VERSION 5.8 ;
BUSBITCHARS "[]" ;
DIVIDERCHAR "/" ;
UNITS
    DATABASE MICRONS 1000 ;
END UNITS

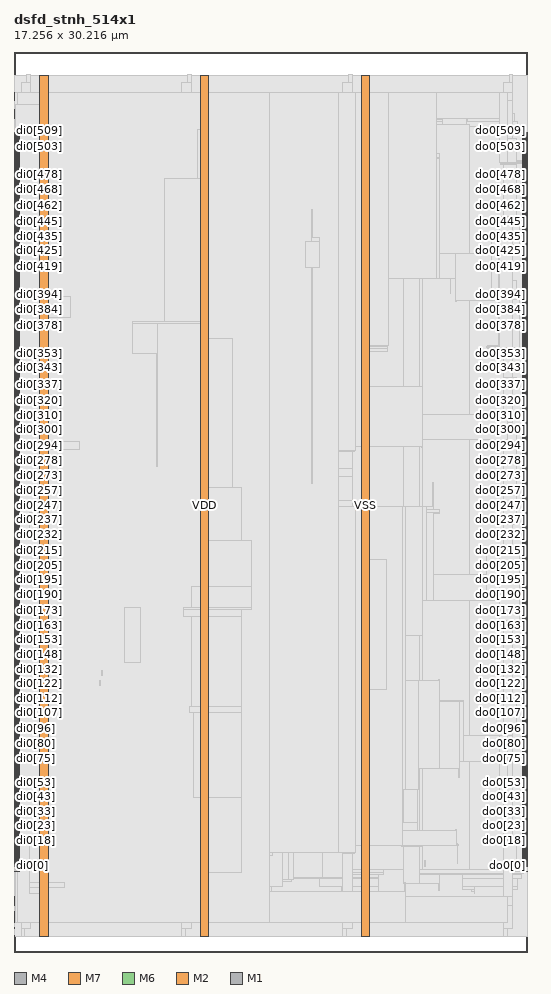
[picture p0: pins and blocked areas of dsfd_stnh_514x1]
MACRO dsfd_stnh_514x1
  FOREIGN dsfd_stnh_514x1 0 0 ;
  CLASS BLOCK ;
  SIZE 17.256 BY 30.216 ;
  PIN di0[0]
    DIRECTION INPUT ;
    USE SIGNAL ;
    PORT
      LAYER M4 ;
        RECT  0 2.88 0.192 2.904 ;
    END
  END di0[0]
  PIN di0[100]
    DIRECTION INPUT ;
    USE SIGNAL ;
    PORT
      LAYER M4 ;
        RECT  0 7.68 0.192 7.704 ;
    END
  END di0[100]
  PIN di0[101]
    DIRECTION INPUT ;
    USE SIGNAL ;
    PORT
      LAYER M4 ;
        RECT  0 7.728 0.192 7.752 ;
    END
  END di0[101]
  PIN di0[102]
    DIRECTION INPUT ;
    USE SIGNAL ;
    PORT
      LAYER M4 ;
        RECT  0 7.776 0.192 7.8 ;
    END
  END di0[102]
  PIN di0[103]
    DIRECTION INPUT ;
    USE SIGNAL ;
    PORT
      LAYER M4 ;
        RECT  0 7.824 0.192 7.848 ;
    END
  END di0[103]
  PIN di0[104]
    DIRECTION INPUT ;
    USE SIGNAL ;
    PORT
      LAYER M4 ;
        RECT  0 7.872 0.192 7.896 ;
    END
  END di0[104]
  PIN di0[105]
    DIRECTION INPUT ;
    USE SIGNAL ;
    PORT
      LAYER M4 ;
        RECT  0 7.92 0.192 7.944 ;
    END
  END di0[105]
  PIN di0[106]
    DIRECTION INPUT ;
    USE SIGNAL ;
    PORT
      LAYER M4 ;
        RECT  0 7.968 0.192 7.992 ;
    END
  END di0[106]
  PIN di0[107]
    DIRECTION INPUT ;
    USE SIGNAL ;
    PORT
      LAYER M4 ;
        RECT  0 8.016 0.192 8.04 ;
    END
  END di0[107]
  PIN di0[108]
    DIRECTION INPUT ;
    USE SIGNAL ;
    PORT
      LAYER M4 ;
        RECT  0 8.064 0.192 8.088 ;
    END
  END di0[108]
  PIN di0[109]
    DIRECTION INPUT ;
    USE SIGNAL ;
    PORT
      LAYER M4 ;
        RECT  0 8.112 0.192 8.136 ;
    END
  END di0[109]
  PIN di0[10]
    DIRECTION INPUT ;
    USE SIGNAL ;
    PORT
      LAYER M4 ;
        RECT  0 3.36 0.192 3.384 ;
    END
  END di0[10]
  PIN di0[110]
    DIRECTION INPUT ;
    USE SIGNAL ;
    PORT
      LAYER M4 ;
        RECT  0 8.16 0.192 8.184 ;
    END
  END di0[110]
  PIN di0[111]
    DIRECTION INPUT ;
    USE SIGNAL ;
    PORT
      LAYER M4 ;
        RECT  0 8.208 0.192 8.232 ;
    END
  END di0[111]
  PIN di0[112]
    DIRECTION INPUT ;
    USE SIGNAL ;
    PORT
      LAYER M4 ;
        RECT  0 8.256 0.192 8.28 ;
    END
  END di0[112]
  PIN di0[113]
    DIRECTION INPUT ;
    USE SIGNAL ;
    PORT
      LAYER M4 ;
        RECT  0 8.304 0.192 8.328 ;
    END
  END di0[113]
  PIN di0[114]
    DIRECTION INPUT ;
    USE SIGNAL ;
    PORT
      LAYER M4 ;
        RECT  0 8.352 0.192 8.376 ;
    END
  END di0[114]
  PIN di0[115]
    DIRECTION INPUT ;
    USE SIGNAL ;
    PORT
      LAYER M4 ;
        RECT  0 8.4 0.192 8.424 ;
    END
  END di0[115]
  PIN di0[116]
    DIRECTION INPUT ;
    USE SIGNAL ;
    PORT
      LAYER M4 ;
        RECT  0 8.448 0.192 8.472 ;
    END
  END di0[116]
  PIN di0[117]
    DIRECTION INPUT ;
    USE SIGNAL ;
    PORT
      LAYER M4 ;
        RECT  0 8.496 0.192 8.52 ;
    END
  END di0[117]
  PIN di0[118]
    DIRECTION INPUT ;
    USE SIGNAL ;
    PORT
      LAYER M4 ;
        RECT  0 8.544 0.192 8.568 ;
    END
  END di0[118]
  PIN di0[119]
    DIRECTION INPUT ;
    USE SIGNAL ;
    PORT
      LAYER M4 ;
        RECT  0 8.592 0.192 8.616 ;
    END
  END di0[119]
  PIN di0[11]
    DIRECTION INPUT ;
    USE SIGNAL ;
    PORT
      LAYER M4 ;
        RECT  0 3.408 0.192 3.432 ;
    END
  END di0[11]
  PIN di0[120]
    DIRECTION INPUT ;
    USE SIGNAL ;
    PORT
      LAYER M4 ;
        RECT  0 8.64 0.192 8.664 ;
    END
  END di0[120]
  PIN di0[121]
    DIRECTION INPUT ;
    USE SIGNAL ;
    PORT
      LAYER M4 ;
        RECT  0 8.688 0.192 8.712 ;
    END
  END di0[121]
  PIN di0[122]
    DIRECTION INPUT ;
    USE SIGNAL ;
    PORT
      LAYER M4 ;
        RECT  0 8.736 0.192 8.76 ;
    END
  END di0[122]
  PIN di0[123]
    DIRECTION INPUT ;
    USE SIGNAL ;
    PORT
      LAYER M4 ;
        RECT  0 8.784 0.192 8.808 ;
    END
  END di0[123]
  PIN di0[124]
    DIRECTION INPUT ;
    USE SIGNAL ;
    PORT
      LAYER M4 ;
        RECT  0 8.832 0.192 8.856 ;
    END
  END di0[124]
  PIN di0[125]
    DIRECTION INPUT ;
    USE SIGNAL ;
    PORT
      LAYER M4 ;
        RECT  0 8.88 0.192 8.904 ;
    END
  END di0[125]
  PIN di0[126]
    DIRECTION INPUT ;
    USE SIGNAL ;
    PORT
      LAYER M4 ;
        RECT  0 8.928 0.192 8.952 ;
    END
  END di0[126]
  PIN di0[127]
    DIRECTION INPUT ;
    USE SIGNAL ;
    PORT
      LAYER M4 ;
        RECT  0 8.976 0.192 9 ;
    END
  END di0[127]
  PIN di0[128]
    DIRECTION INPUT ;
    USE SIGNAL ;
    PORT
      LAYER M4 ;
        RECT  0 9.024 0.192 9.048 ;
    END
  END di0[128]
  PIN di0[129]
    DIRECTION INPUT ;
    USE SIGNAL ;
    PORT
      LAYER M4 ;
        RECT  0 9.072 0.192 9.096 ;
    END
  END di0[129]
  PIN di0[12]
    DIRECTION INPUT ;
    USE SIGNAL ;
    PORT
      LAYER M4 ;
        RECT  0 3.456 0.192 3.48 ;
    END
  END di0[12]
  PIN di0[130]
    DIRECTION INPUT ;
    USE SIGNAL ;
    PORT
      LAYER M4 ;
        RECT  0 9.12 0.192 9.144 ;
    END
  END di0[130]
  PIN di0[131]
    DIRECTION INPUT ;
    USE SIGNAL ;
    PORT
      LAYER M4 ;
        RECT  0 9.168 0.192 9.192 ;
    END
  END di0[131]
  PIN di0[132]
    DIRECTION INPUT ;
    USE SIGNAL ;
    PORT
      LAYER M4 ;
        RECT  0 9.216 0.192 9.24 ;
    END
  END di0[132]
  PIN di0[133]
    DIRECTION INPUT ;
    USE SIGNAL ;
    PORT
      LAYER M4 ;
        RECT  0 9.264 0.192 9.288 ;
    END
  END di0[133]
  PIN di0[134]
    DIRECTION INPUT ;
    USE SIGNAL ;
    PORT
      LAYER M4 ;
        RECT  0 9.312 0.192 9.336 ;
    END
  END di0[134]
  PIN di0[135]
    DIRECTION INPUT ;
    USE SIGNAL ;
    PORT
      LAYER M4 ;
        RECT  0 9.36 0.192 9.384 ;
    END
  END di0[135]
  PIN di0[136]
    DIRECTION INPUT ;
    USE SIGNAL ;
    PORT
      LAYER M4 ;
        RECT  0 9.408 0.192 9.432 ;
    END
  END di0[136]
  PIN di0[137]
    DIRECTION INPUT ;
    USE SIGNAL ;
    PORT
      LAYER M4 ;
        RECT  0 9.456 0.192 9.48 ;
    END
  END di0[137]
  PIN di0[138]
    DIRECTION INPUT ;
    USE SIGNAL ;
    PORT
      LAYER M4 ;
        RECT  0 9.504 0.192 9.528 ;
    END
  END di0[138]
  PIN di0[139]
    DIRECTION INPUT ;
    USE SIGNAL ;
    PORT
      LAYER M4 ;
        RECT  0 9.552 0.192 9.576 ;
    END
  END di0[139]
  PIN di0[13]
    DIRECTION INPUT ;
    USE SIGNAL ;
    PORT
      LAYER M4 ;
        RECT  0 3.504 0.192 3.528 ;
    END
  END di0[13]
  PIN di0[140]
    DIRECTION INPUT ;
    USE SIGNAL ;
    PORT
      LAYER M4 ;
        RECT  0 9.6 0.192 9.624 ;
    END
  END di0[140]
  PIN di0[141]
    DIRECTION INPUT ;
    USE SIGNAL ;
    PORT
      LAYER M4 ;
        RECT  0 9.648 0.192 9.672 ;
    END
  END di0[141]
  PIN di0[142]
    DIRECTION INPUT ;
    USE SIGNAL ;
    PORT
      LAYER M4 ;
        RECT  0 9.696 0.192 9.72 ;
    END
  END di0[142]
  PIN di0[143]
    DIRECTION INPUT ;
    USE SIGNAL ;
    PORT
      LAYER M4 ;
        RECT  0 9.744 0.192 9.768 ;
    END
  END di0[143]
  PIN di0[144]
    DIRECTION INPUT ;
    USE SIGNAL ;
    PORT
      LAYER M4 ;
        RECT  0 9.792 0.192 9.816 ;
    END
  END di0[144]
  PIN di0[145]
    DIRECTION INPUT ;
    USE SIGNAL ;
    PORT
      LAYER M4 ;
        RECT  0 9.84 0.192 9.864 ;
    END
  END di0[145]
  PIN di0[146]
    DIRECTION INPUT ;
    USE SIGNAL ;
    PORT
      LAYER M4 ;
        RECT  0 9.888 0.192 9.912 ;
    END
  END di0[146]
  PIN di0[147]
    DIRECTION INPUT ;
    USE SIGNAL ;
    PORT
      LAYER M4 ;
        RECT  0 9.936 0.192 9.96 ;
    END
  END di0[147]
  PIN di0[148]
    DIRECTION INPUT ;
    USE SIGNAL ;
    PORT
      LAYER M4 ;
        RECT  0 9.984 0.192 10.008 ;
    END
  END di0[148]
  PIN di0[149]
    DIRECTION INPUT ;
    USE SIGNAL ;
    PORT
      LAYER M4 ;
        RECT  0 10.032 0.192 10.056 ;
    END
  END di0[149]
  PIN di0[14]
    DIRECTION INPUT ;
    USE SIGNAL ;
    PORT
      LAYER M4 ;
        RECT  0 3.552 0.192 3.576 ;
    END
  END di0[14]
  PIN di0[150]
    DIRECTION INPUT ;
    USE SIGNAL ;
    PORT
      LAYER M4 ;
        RECT  0 10.08 0.192 10.104 ;
    END
  END di0[150]
  PIN di0[151]
    DIRECTION INPUT ;
    USE SIGNAL ;
    PORT
      LAYER M4 ;
        RECT  0 10.128 0.192 10.152 ;
    END
  END di0[151]
  PIN di0[152]
    DIRECTION INPUT ;
    USE SIGNAL ;
    PORT
      LAYER M4 ;
        RECT  0 10.176 0.192 10.2 ;
    END
  END di0[152]
  PIN di0[153]
    DIRECTION INPUT ;
    USE SIGNAL ;
    PORT
      LAYER M4 ;
        RECT  0 10.224 0.192 10.248 ;
    END
  END di0[153]
  PIN di0[154]
    DIRECTION INPUT ;
    USE SIGNAL ;
    PORT
      LAYER M4 ;
        RECT  0 10.272 0.192 10.296 ;
    END
  END di0[154]
  PIN di0[155]
    DIRECTION INPUT ;
    USE SIGNAL ;
    PORT
      LAYER M4 ;
        RECT  0 10.32 0.192 10.344 ;
    END
  END di0[155]
  PIN di0[156]
    DIRECTION INPUT ;
    USE SIGNAL ;
    PORT
      LAYER M4 ;
        RECT  0 10.368 0.192 10.392 ;
    END
  END di0[156]
  PIN di0[157]
    DIRECTION INPUT ;
    USE SIGNAL ;
    PORT
      LAYER M4 ;
        RECT  0 10.416 0.192 10.44 ;
    END
  END di0[157]
  PIN di0[158]
    DIRECTION INPUT ;
    USE SIGNAL ;
    PORT
      LAYER M4 ;
        RECT  0 10.464 0.192 10.488 ;
    END
  END di0[158]
  PIN di0[159]
    DIRECTION INPUT ;
    USE SIGNAL ;
    PORT
      LAYER M4 ;
        RECT  0 10.512 0.192 10.536 ;
    END
  END di0[159]
  PIN di0[15]
    DIRECTION INPUT ;
    USE SIGNAL ;
    PORT
      LAYER M4 ;
        RECT  0 3.6 0.192 3.624 ;
    END
  END di0[15]
  PIN di0[160]
    DIRECTION INPUT ;
    USE SIGNAL ;
    PORT
      LAYER M4 ;
        RECT  0 10.56 0.192 10.584 ;
    END
  END di0[160]
  PIN di0[161]
    DIRECTION INPUT ;
    USE SIGNAL ;
    PORT
      LAYER M4 ;
        RECT  0 10.608 0.192 10.632 ;
    END
  END di0[161]
  PIN di0[162]
    DIRECTION INPUT ;
    USE SIGNAL ;
    PORT
      LAYER M4 ;
        RECT  0 10.656 0.192 10.68 ;
    END
  END di0[162]
  PIN di0[163]
    DIRECTION INPUT ;
    USE SIGNAL ;
    PORT
      LAYER M4 ;
        RECT  0 10.704 0.192 10.728 ;
    END
  END di0[163]
  PIN di0[164]
    DIRECTION INPUT ;
    USE SIGNAL ;
    PORT
      LAYER M4 ;
        RECT  0 10.752 0.192 10.776 ;
    END
  END di0[164]
  PIN di0[165]
    DIRECTION INPUT ;
    USE SIGNAL ;
    PORT
      LAYER M4 ;
        RECT  0 10.8 0.192 10.824 ;
    END
  END di0[165]
  PIN di0[166]
    DIRECTION INPUT ;
    USE SIGNAL ;
    PORT
      LAYER M4 ;
        RECT  0 10.848 0.192 10.872 ;
    END
  END di0[166]
  PIN di0[167]
    DIRECTION INPUT ;
    USE SIGNAL ;
    PORT
      LAYER M4 ;
        RECT  0 10.896 0.192 10.92 ;
    END
  END di0[167]
  PIN di0[168]
    DIRECTION INPUT ;
    USE SIGNAL ;
    PORT
      LAYER M4 ;
        RECT  0 10.944 0.192 10.968 ;
    END
  END di0[168]
  PIN di0[169]
    DIRECTION INPUT ;
    USE SIGNAL ;
    PORT
      LAYER M4 ;
        RECT  0 10.992 0.192 11.016 ;
    END
  END di0[169]
  PIN di0[16]
    DIRECTION INPUT ;
    USE SIGNAL ;
    PORT
      LAYER M4 ;
        RECT  0 3.648 0.192 3.672 ;
    END
  END di0[16]
  PIN di0[170]
    DIRECTION INPUT ;
    USE SIGNAL ;
    PORT
      LAYER M4 ;
        RECT  0 11.04 0.192 11.064 ;
    END
  END di0[170]
  PIN di0[171]
    DIRECTION INPUT ;
    USE SIGNAL ;
    PORT
      LAYER M4 ;
        RECT  0 11.088 0.192 11.112 ;
    END
  END di0[171]
  PIN di0[172]
    DIRECTION INPUT ;
    USE SIGNAL ;
    PORT
      LAYER M4 ;
        RECT  0 11.136 0.192 11.16 ;
    END
  END di0[172]
  PIN di0[173]
    DIRECTION INPUT ;
    USE SIGNAL ;
    PORT
      LAYER M4 ;
        RECT  0 11.184 0.192 11.208 ;
    END
  END di0[173]
  PIN di0[174]
    DIRECTION INPUT ;
    USE SIGNAL ;
    PORT
      LAYER M4 ;
        RECT  0 11.232 0.192 11.256 ;
    END
  END di0[174]
  PIN di0[175]
    DIRECTION INPUT ;
    USE SIGNAL ;
    PORT
      LAYER M4 ;
        RECT  0 11.28 0.192 11.304 ;
    END
  END di0[175]
  PIN di0[176]
    DIRECTION INPUT ;
    USE SIGNAL ;
    PORT
      LAYER M4 ;
        RECT  0 11.328 0.192 11.352 ;
    END
  END di0[176]
  PIN di0[177]
    DIRECTION INPUT ;
    USE SIGNAL ;
    PORT
      LAYER M4 ;
        RECT  0 11.376 0.192 11.4 ;
    END
  END di0[177]
  PIN di0[178]
    DIRECTION INPUT ;
    USE SIGNAL ;
    PORT
      LAYER M4 ;
        RECT  0 11.424 0.192 11.448 ;
    END
  END di0[178]
  PIN di0[179]
    DIRECTION INPUT ;
    USE SIGNAL ;
    PORT
      LAYER M4 ;
        RECT  0 11.472 0.192 11.496 ;
    END
  END di0[179]
  PIN di0[17]
    DIRECTION INPUT ;
    USE SIGNAL ;
    PORT
      LAYER M4 ;
        RECT  0 3.696 0.192 3.72 ;
    END
  END di0[17]
  PIN di0[180]
    DIRECTION INPUT ;
    USE SIGNAL ;
    PORT
      LAYER M4 ;
        RECT  0 11.52 0.192 11.544 ;
    END
  END di0[180]
  PIN di0[181]
    DIRECTION INPUT ;
    USE SIGNAL ;
    PORT
      LAYER M4 ;
        RECT  0 11.568 0.192 11.592 ;
    END
  END di0[181]
  PIN di0[182]
    DIRECTION INPUT ;
    USE SIGNAL ;
    PORT
      LAYER M4 ;
        RECT  0 11.616 0.192 11.64 ;
    END
  END di0[182]
  PIN di0[183]
    DIRECTION INPUT ;
    USE SIGNAL ;
    PORT
      LAYER M4 ;
        RECT  0 11.664 0.192 11.688 ;
    END
  END di0[183]
  PIN di0[184]
    DIRECTION INPUT ;
    USE SIGNAL ;
    PORT
      LAYER M4 ;
        RECT  0 11.712 0.192 11.736 ;
    END
  END di0[184]
  PIN di0[185]
    DIRECTION INPUT ;
    USE SIGNAL ;
    PORT
      LAYER M4 ;
        RECT  0 11.76 0.192 11.784 ;
    END
  END di0[185]
  PIN di0[186]
    DIRECTION INPUT ;
    USE SIGNAL ;
    PORT
      LAYER M4 ;
        RECT  0 11.808 0.192 11.832 ;
    END
  END di0[186]
  PIN di0[187]
    DIRECTION INPUT ;
    USE SIGNAL ;
    PORT
      LAYER M4 ;
        RECT  0 11.856 0.192 11.88 ;
    END
  END di0[187]
  PIN di0[188]
    DIRECTION INPUT ;
    USE SIGNAL ;
    PORT
      LAYER M4 ;
        RECT  0 11.904 0.192 11.928 ;
    END
  END di0[188]
  PIN di0[189]
    DIRECTION INPUT ;
    USE SIGNAL ;
    PORT
      LAYER M4 ;
        RECT  0 11.952 0.192 11.976 ;
    END
  END di0[189]
  PIN di0[18]
    DIRECTION INPUT ;
    USE SIGNAL ;
    PORT
      LAYER M4 ;
        RECT  0 3.744 0.192 3.768 ;
    END
  END di0[18]
  PIN di0[190]
    DIRECTION INPUT ;
    USE SIGNAL ;
    PORT
      LAYER M4 ;
        RECT  0 12 0.192 12.024 ;
    END
  END di0[190]
  PIN di0[191]
    DIRECTION INPUT ;
    USE SIGNAL ;
    PORT
      LAYER M4 ;
        RECT  0 12.048 0.192 12.072 ;
    END
  END di0[191]
  PIN di0[192]
    DIRECTION INPUT ;
    USE SIGNAL ;
    PORT
      LAYER M4 ;
        RECT  0 12.096 0.192 12.12 ;
    END
  END di0[192]
  PIN di0[193]
    DIRECTION INPUT ;
    USE SIGNAL ;
    PORT
      LAYER M4 ;
        RECT  0 12.144 0.192 12.168 ;
    END
  END di0[193]
  PIN di0[194]
    DIRECTION INPUT ;
    USE SIGNAL ;
    PORT
      LAYER M4 ;
        RECT  0 12.192 0.192 12.216 ;
    END
  END di0[194]
  PIN di0[195]
    DIRECTION INPUT ;
    USE SIGNAL ;
    PORT
      LAYER M4 ;
        RECT  0 12.24 0.192 12.264 ;
    END
  END di0[195]
  PIN di0[196]
    DIRECTION INPUT ;
    USE SIGNAL ;
    PORT
      LAYER M4 ;
        RECT  0 12.288 0.192 12.312 ;
    END
  END di0[196]
  PIN di0[197]
    DIRECTION INPUT ;
    USE SIGNAL ;
    PORT
      LAYER M4 ;
        RECT  0 12.336 0.192 12.36 ;
    END
  END di0[197]
  PIN di0[198]
    DIRECTION INPUT ;
    USE SIGNAL ;
    PORT
      LAYER M4 ;
        RECT  0 12.384 0.192 12.408 ;
    END
  END di0[198]
  PIN di0[199]
    DIRECTION INPUT ;
    USE SIGNAL ;
    PORT
      LAYER M4 ;
        RECT  0 12.432 0.192 12.456 ;
    END
  END di0[199]
  PIN di0[19]
    DIRECTION INPUT ;
    USE SIGNAL ;
    PORT
      LAYER M4 ;
        RECT  0 3.792 0.192 3.816 ;
    END
  END di0[19]
  PIN di0[1]
    DIRECTION INPUT ;
    USE SIGNAL ;
    PORT
      LAYER M4 ;
        RECT  0 2.928 0.192 2.952 ;
    END
  END di0[1]
  PIN di0[200]
    DIRECTION INPUT ;
    USE SIGNAL ;
    PORT
      LAYER M4 ;
        RECT  0 12.48 0.192 12.504 ;
    END
  END di0[200]
  PIN di0[201]
    DIRECTION INPUT ;
    USE SIGNAL ;
    PORT
      LAYER M4 ;
        RECT  0 12.528 0.192 12.552 ;
    END
  END di0[201]
  PIN di0[202]
    DIRECTION INPUT ;
    USE SIGNAL ;
    PORT
      LAYER M4 ;
        RECT  0 12.576 0.192 12.6 ;
    END
  END di0[202]
  PIN di0[203]
    DIRECTION INPUT ;
    USE SIGNAL ;
    PORT
      LAYER M4 ;
        RECT  0 12.624 0.192 12.648 ;
    END
  END di0[203]
  PIN di0[204]
    DIRECTION INPUT ;
    USE SIGNAL ;
    PORT
      LAYER M4 ;
        RECT  0 12.672 0.192 12.696 ;
    END
  END di0[204]
  PIN di0[205]
    DIRECTION INPUT ;
    USE SIGNAL ;
    PORT
      LAYER M4 ;
        RECT  0 12.72 0.192 12.744 ;
    END
  END di0[205]
  PIN di0[206]
    DIRECTION INPUT ;
    USE SIGNAL ;
    PORT
      LAYER M4 ;
        RECT  0 12.768 0.192 12.792 ;
    END
  END di0[206]
  PIN di0[207]
    DIRECTION INPUT ;
    USE SIGNAL ;
    PORT
      LAYER M4 ;
        RECT  0 12.816 0.192 12.84 ;
    END
  END di0[207]
  PIN di0[208]
    DIRECTION INPUT ;
    USE SIGNAL ;
    PORT
      LAYER M4 ;
        RECT  0 12.864 0.192 12.888 ;
    END
  END di0[208]
  PIN di0[209]
    DIRECTION INPUT ;
    USE SIGNAL ;
    PORT
      LAYER M4 ;
        RECT  0 12.912 0.192 12.936 ;
    END
  END di0[209]
  PIN di0[20]
    DIRECTION INPUT ;
    USE SIGNAL ;
    PORT
      LAYER M4 ;
        RECT  0 3.84 0.192 3.864 ;
    END
  END di0[20]
  PIN di0[210]
    DIRECTION INPUT ;
    USE SIGNAL ;
    PORT
      LAYER M4 ;
        RECT  0 12.96 0.192 12.984 ;
    END
  END di0[210]
  PIN di0[211]
    DIRECTION INPUT ;
    USE SIGNAL ;
    PORT
      LAYER M4 ;
        RECT  0 13.008 0.192 13.032 ;
    END
  END di0[211]
  PIN di0[212]
    DIRECTION INPUT ;
    USE SIGNAL ;
    PORT
      LAYER M4 ;
        RECT  0 13.056 0.192 13.08 ;
    END
  END di0[212]
  PIN di0[213]
    DIRECTION INPUT ;
    USE SIGNAL ;
    PORT
      LAYER M4 ;
        RECT  0 13.104 0.192 13.128 ;
    END
  END di0[213]
  PIN di0[214]
    DIRECTION INPUT ;
    USE SIGNAL ;
    PORT
      LAYER M4 ;
        RECT  0 13.152 0.192 13.176 ;
    END
  END di0[214]
  PIN di0[215]
    DIRECTION INPUT ;
    USE SIGNAL ;
    PORT
      LAYER M4 ;
        RECT  0 13.2 0.192 13.224 ;
    END
  END di0[215]
  PIN di0[216]
    DIRECTION INPUT ;
    USE SIGNAL ;
    PORT
      LAYER M4 ;
        RECT  0 13.248 0.192 13.272 ;
    END
  END di0[216]
  PIN di0[217]
    DIRECTION INPUT ;
    USE SIGNAL ;
    PORT
      LAYER M4 ;
        RECT  0 13.296 0.192 13.32 ;
    END
  END di0[217]
  PIN di0[218]
    DIRECTION INPUT ;
    USE SIGNAL ;
    PORT
      LAYER M4 ;
        RECT  0 13.344 0.192 13.368 ;
    END
  END di0[218]
  PIN di0[219]
    DIRECTION INPUT ;
    USE SIGNAL ;
    PORT
      LAYER M4 ;
        RECT  0 13.392 0.192 13.416 ;
    END
  END di0[219]
  PIN di0[21]
    DIRECTION INPUT ;
    USE SIGNAL ;
    PORT
      LAYER M4 ;
        RECT  0 3.888 0.192 3.912 ;
    END
  END di0[21]
  PIN di0[220]
    DIRECTION INPUT ;
    USE SIGNAL ;
    PORT
      LAYER M4 ;
        RECT  0 13.44 0.192 13.464 ;
    END
  END di0[220]
  PIN di0[221]
    DIRECTION INPUT ;
    USE SIGNAL ;
    PORT
      LAYER M4 ;
        RECT  0 13.488 0.192 13.512 ;
    END
  END di0[221]
  PIN di0[222]
    DIRECTION INPUT ;
    USE SIGNAL ;
    PORT
      LAYER M4 ;
        RECT  0 13.536 0.192 13.56 ;
    END
  END di0[222]
  PIN di0[223]
    DIRECTION INPUT ;
    USE SIGNAL ;
    PORT
      LAYER M4 ;
        RECT  0 13.584 0.192 13.608 ;
    END
  END di0[223]
  PIN di0[224]
    DIRECTION INPUT ;
    USE SIGNAL ;
    PORT
      LAYER M4 ;
        RECT  0 13.632 0.192 13.656 ;
    END
  END di0[224]
  PIN di0[225]
    DIRECTION INPUT ;
    USE SIGNAL ;
    PORT
      LAYER M4 ;
        RECT  0 13.68 0.192 13.704 ;
    END
  END di0[225]
  PIN di0[226]
    DIRECTION INPUT ;
    USE SIGNAL ;
    PORT
      LAYER M4 ;
        RECT  0 13.728 0.192 13.752 ;
    END
  END di0[226]
  PIN di0[227]
    DIRECTION INPUT ;
    USE SIGNAL ;
    PORT
      LAYER M4 ;
        RECT  0 13.776 0.192 13.8 ;
    END
  END di0[227]
  PIN di0[228]
    DIRECTION INPUT ;
    USE SIGNAL ;
    PORT
      LAYER M4 ;
        RECT  0 13.824 0.192 13.848 ;
    END
  END di0[228]
  PIN di0[229]
    DIRECTION INPUT ;
    USE SIGNAL ;
    PORT
      LAYER M4 ;
        RECT  0 13.872 0.192 13.896 ;
    END
  END di0[229]
  PIN di0[22]
    DIRECTION INPUT ;
    USE SIGNAL ;
    PORT
      LAYER M4 ;
        RECT  0 3.936 0.192 3.96 ;
    END
  END di0[22]
  PIN di0[230]
    DIRECTION INPUT ;
    USE SIGNAL ;
    PORT
      LAYER M4 ;
        RECT  0 13.92 0.192 13.944 ;
    END
  END di0[230]
  PIN di0[231]
    DIRECTION INPUT ;
    USE SIGNAL ;
    PORT
      LAYER M4 ;
        RECT  0 13.968 0.192 13.992 ;
    END
  END di0[231]
  PIN di0[232]
    DIRECTION INPUT ;
    USE SIGNAL ;
    PORT
      LAYER M4 ;
        RECT  0 14.016 0.192 14.04 ;
    END
  END di0[232]
  PIN di0[233]
    DIRECTION INPUT ;
    USE SIGNAL ;
    PORT
      LAYER M4 ;
        RECT  0 14.064 0.192 14.088 ;
    END
  END di0[233]
  PIN di0[234]
    DIRECTION INPUT ;
    USE SIGNAL ;
    PORT
      LAYER M4 ;
        RECT  0 14.112 0.192 14.136 ;
    END
  END di0[234]
  PIN di0[235]
    DIRECTION INPUT ;
    USE SIGNAL ;
    PORT
      LAYER M4 ;
        RECT  0 14.16 0.192 14.184 ;
    END
  END di0[235]
  PIN di0[236]
    DIRECTION INPUT ;
    USE SIGNAL ;
    PORT
      LAYER M4 ;
        RECT  0 14.208 0.192 14.232 ;
    END
  END di0[236]
  PIN di0[237]
    DIRECTION INPUT ;
    USE SIGNAL ;
    PORT
      LAYER M4 ;
        RECT  0 14.256 0.192 14.28 ;
    END
  END di0[237]
  PIN di0[238]
    DIRECTION INPUT ;
    USE SIGNAL ;
    PORT
      LAYER M4 ;
        RECT  0 14.304 0.192 14.328 ;
    END
  END di0[238]
  PIN di0[239]
    DIRECTION INPUT ;
    USE SIGNAL ;
    PORT
      LAYER M4 ;
        RECT  0 14.352 0.192 14.376 ;
    END
  END di0[239]
  PIN di0[23]
    DIRECTION INPUT ;
    USE SIGNAL ;
    PORT
      LAYER M4 ;
        RECT  0 3.984 0.192 4.008 ;
    END
  END di0[23]
  PIN di0[240]
    DIRECTION INPUT ;
    USE SIGNAL ;
    PORT
      LAYER M4 ;
        RECT  0 14.4 0.192 14.424 ;
    END
  END di0[240]
  PIN di0[241]
    DIRECTION INPUT ;
    USE SIGNAL ;
    PORT
      LAYER M4 ;
        RECT  0 14.448 0.192 14.472 ;
    END
  END di0[241]
  PIN di0[242]
    DIRECTION INPUT ;
    USE SIGNAL ;
    PORT
      LAYER M4 ;
        RECT  0 14.496 0.192 14.52 ;
    END
  END di0[242]
  PIN di0[243]
    DIRECTION INPUT ;
    USE SIGNAL ;
    PORT
      LAYER M4 ;
        RECT  0 14.544 0.192 14.568 ;
    END
  END di0[243]
  PIN di0[244]
    DIRECTION INPUT ;
    USE SIGNAL ;
    PORT
      LAYER M4 ;
        RECT  0 14.592 0.192 14.616 ;
    END
  END di0[244]
  PIN di0[245]
    DIRECTION INPUT ;
    USE SIGNAL ;
    PORT
      LAYER M4 ;
        RECT  0 14.64 0.192 14.664 ;
    END
  END di0[245]
  PIN di0[246]
    DIRECTION INPUT ;
    USE SIGNAL ;
    PORT
      LAYER M4 ;
        RECT  0 14.688 0.192 14.712 ;
    END
  END di0[246]
  PIN di0[247]
    DIRECTION INPUT ;
    USE SIGNAL ;
    PORT
      LAYER M4 ;
        RECT  0 14.736 0.192 14.76 ;
    END
  END di0[247]
  PIN di0[248]
    DIRECTION INPUT ;
    USE SIGNAL ;
    PORT
      LAYER M4 ;
        RECT  0 14.784 0.192 14.808 ;
    END
  END di0[248]
  PIN di0[249]
    DIRECTION INPUT ;
    USE SIGNAL ;
    PORT
      LAYER M4 ;
        RECT  0 14.832 0.192 14.856 ;
    END
  END di0[249]
  PIN di0[24]
    DIRECTION INPUT ;
    USE SIGNAL ;
    PORT
      LAYER M4 ;
        RECT  0 4.032 0.192 4.056 ;
    END
  END di0[24]
  PIN di0[250]
    DIRECTION INPUT ;
    USE SIGNAL ;
    PORT
      LAYER M4 ;
        RECT  0 14.88 0.192 14.904 ;
    END
  END di0[250]
  PIN di0[251]
    DIRECTION INPUT ;
    USE SIGNAL ;
    PORT
      LAYER M4 ;
        RECT  0 14.928 0.192 14.952 ;
    END
  END di0[251]
  PIN di0[252]
    DIRECTION INPUT ;
    USE SIGNAL ;
    PORT
      LAYER M4 ;
        RECT  0 14.976 0.192 15 ;
    END
  END di0[252]
  PIN di0[253]
    DIRECTION INPUT ;
    USE SIGNAL ;
    PORT
      LAYER M4 ;
        RECT  0 15.024 0.192 15.048 ;
    END
  END di0[253]
  PIN di0[254]
    DIRECTION INPUT ;
    USE SIGNAL ;
    PORT
      LAYER M4 ;
        RECT  0 15.072 0.192 15.096 ;
    END
  END di0[254]
  PIN di0[255]
    DIRECTION INPUT ;
    USE SIGNAL ;
    PORT
      LAYER M4 ;
        RECT  0 15.12 0.192 15.144 ;
    END
  END di0[255]
  PIN di0[256]
    DIRECTION INPUT ;
    USE SIGNAL ;
    PORT
      LAYER M4 ;
        RECT  0 15.168 0.192 15.192 ;
    END
  END di0[256]
  PIN di0[257]
    DIRECTION INPUT ;
    USE SIGNAL ;
    PORT
      LAYER M4 ;
        RECT  0 15.216 0.192 15.24 ;
    END
  END di0[257]
  PIN di0[258]
    DIRECTION INPUT ;
    USE SIGNAL ;
    PORT
      LAYER M4 ;
        RECT  0 15.264 0.192 15.288 ;
    END
  END di0[258]
  PIN di0[259]
    DIRECTION INPUT ;
    USE SIGNAL ;
    PORT
      LAYER M4 ;
        RECT  0 15.312 0.192 15.336 ;
    END
  END di0[259]
  PIN di0[25]
    DIRECTION INPUT ;
    USE SIGNAL ;
    PORT
      LAYER M4 ;
        RECT  0 4.08 0.192 4.104 ;
    END
  END di0[25]
  PIN di0[260]
    DIRECTION INPUT ;
    USE SIGNAL ;
    PORT
      LAYER M4 ;
        RECT  0 15.36 0.192 15.384 ;
    END
  END di0[260]
  PIN di0[261]
    DIRECTION INPUT ;
    USE SIGNAL ;
    PORT
      LAYER M4 ;
        RECT  0 15.408 0.192 15.432 ;
    END
  END di0[261]
  PIN di0[262]
    DIRECTION INPUT ;
    USE SIGNAL ;
    PORT
      LAYER M4 ;
        RECT  0 15.456 0.192 15.48 ;
    END
  END di0[262]
  PIN di0[263]
    DIRECTION INPUT ;
    USE SIGNAL ;
    PORT
      LAYER M4 ;
        RECT  0 15.504 0.192 15.528 ;
    END
  END di0[263]
  PIN di0[264]
    DIRECTION INPUT ;
    USE SIGNAL ;
    PORT
      LAYER M4 ;
        RECT  0 15.552 0.192 15.576 ;
    END
  END di0[264]
  PIN di0[265]
    DIRECTION INPUT ;
    USE SIGNAL ;
    PORT
      LAYER M4 ;
        RECT  0 15.6 0.192 15.624 ;
    END
  END di0[265]
  PIN di0[266]
    DIRECTION INPUT ;
    USE SIGNAL ;
    PORT
      LAYER M4 ;
        RECT  0 15.648 0.192 15.672 ;
    END
  END di0[266]
  PIN di0[267]
    DIRECTION INPUT ;
    USE SIGNAL ;
    PORT
      LAYER M4 ;
        RECT  0 15.696 0.192 15.72 ;
    END
  END di0[267]
  PIN di0[268]
    DIRECTION INPUT ;
    USE SIGNAL ;
    PORT
      LAYER M4 ;
        RECT  0 15.744 0.192 15.768 ;
    END
  END di0[268]
  PIN di0[269]
    DIRECTION INPUT ;
    USE SIGNAL ;
    PORT
      LAYER M4 ;
        RECT  0 15.792 0.192 15.816 ;
    END
  END di0[269]
  PIN di0[26]
    DIRECTION INPUT ;
    USE SIGNAL ;
    PORT
      LAYER M4 ;
        RECT  0 4.128 0.192 4.152 ;
    END
  END di0[26]
  PIN di0[270]
    DIRECTION INPUT ;
    USE SIGNAL ;
    PORT
      LAYER M4 ;
        RECT  0 15.84 0.192 15.864 ;
    END
  END di0[270]
  PIN di0[271]
    DIRECTION INPUT ;
    USE SIGNAL ;
    PORT
      LAYER M4 ;
        RECT  0 15.888 0.192 15.912 ;
    END
  END di0[271]
  PIN di0[272]
    DIRECTION INPUT ;
    USE SIGNAL ;
    PORT
      LAYER M4 ;
        RECT  0 15.936 0.192 15.96 ;
    END
  END di0[272]
  PIN di0[273]
    DIRECTION INPUT ;
    USE SIGNAL ;
    PORT
      LAYER M4 ;
        RECT  0 15.984 0.192 16.008 ;
    END
  END di0[273]
  PIN di0[274]
    DIRECTION INPUT ;
    USE SIGNAL ;
    PORT
      LAYER M4 ;
        RECT  0 16.032 0.192 16.056 ;
    END
  END di0[274]
  PIN di0[275]
    DIRECTION INPUT ;
    USE SIGNAL ;
    PORT
      LAYER M4 ;
        RECT  0 16.08 0.192 16.104 ;
    END
  END di0[275]
  PIN di0[276]
    DIRECTION INPUT ;
    USE SIGNAL ;
    PORT
      LAYER M4 ;
        RECT  0 16.128 0.192 16.152 ;
    END
  END di0[276]
  PIN di0[277]
    DIRECTION INPUT ;
    USE SIGNAL ;
    PORT
      LAYER M4 ;
        RECT  0 16.176 0.192 16.2 ;
    END
  END di0[277]
  PIN di0[278]
    DIRECTION INPUT ;
    USE SIGNAL ;
    PORT
      LAYER M4 ;
        RECT  0 16.224 0.192 16.248 ;
    END
  END di0[278]
  PIN di0[279]
    DIRECTION INPUT ;
    USE SIGNAL ;
    PORT
      LAYER M4 ;
        RECT  0 16.272 0.192 16.296 ;
    END
  END di0[279]
  PIN di0[27]
    DIRECTION INPUT ;
    USE SIGNAL ;
    PORT
      LAYER M4 ;
        RECT  0 4.176 0.192 4.2 ;
    END
  END di0[27]
  PIN di0[280]
    DIRECTION INPUT ;
    USE SIGNAL ;
    PORT
      LAYER M4 ;
        RECT  0 16.32 0.192 16.344 ;
    END
  END di0[280]
  PIN di0[281]
    DIRECTION INPUT ;
    USE SIGNAL ;
    PORT
      LAYER M4 ;
        RECT  0 16.368 0.192 16.392 ;
    END
  END di0[281]
  PIN di0[282]
    DIRECTION INPUT ;
    USE SIGNAL ;
    PORT
      LAYER M4 ;
        RECT  0 16.416 0.192 16.44 ;
    END
  END di0[282]
  PIN di0[283]
    DIRECTION INPUT ;
    USE SIGNAL ;
    PORT
      LAYER M4 ;
        RECT  0 16.464 0.192 16.488 ;
    END
  END di0[283]
  PIN di0[284]
    DIRECTION INPUT ;
    USE SIGNAL ;
    PORT
      LAYER M4 ;
        RECT  0 16.512 0.192 16.536 ;
    END
  END di0[284]
  PIN di0[285]
    DIRECTION INPUT ;
    USE SIGNAL ;
    PORT
      LAYER M4 ;
        RECT  0 16.56 0.192 16.584 ;
    END
  END di0[285]
  PIN di0[286]
    DIRECTION INPUT ;
    USE SIGNAL ;
    PORT
      LAYER M4 ;
        RECT  0 16.608 0.192 16.632 ;
    END
  END di0[286]
  PIN di0[287]
    DIRECTION INPUT ;
    USE SIGNAL ;
    PORT
      LAYER M4 ;
        RECT  0 16.656 0.192 16.68 ;
    END
  END di0[287]
  PIN di0[288]
    DIRECTION INPUT ;
    USE SIGNAL ;
    PORT
      LAYER M4 ;
        RECT  0 16.704 0.192 16.728 ;
    END
  END di0[288]
  PIN di0[289]
    DIRECTION INPUT ;
    USE SIGNAL ;
    PORT
      LAYER M4 ;
        RECT  0 16.752 0.192 16.776 ;
    END
  END di0[289]
  PIN di0[28]
    DIRECTION INPUT ;
    USE SIGNAL ;
    PORT
      LAYER M4 ;
        RECT  0 4.224 0.192 4.248 ;
    END
  END di0[28]
  PIN di0[290]
    DIRECTION INPUT ;
    USE SIGNAL ;
    PORT
      LAYER M4 ;
        RECT  0 16.8 0.192 16.824 ;
    END
  END di0[290]
  PIN di0[291]
    DIRECTION INPUT ;
    USE SIGNAL ;
    PORT
      LAYER M4 ;
        RECT  0 16.848 0.192 16.872 ;
    END
  END di0[291]
  PIN di0[292]
    DIRECTION INPUT ;
    USE SIGNAL ;
    PORT
      LAYER M4 ;
        RECT  0 16.896 0.192 16.92 ;
    END
  END di0[292]
  PIN di0[293]
    DIRECTION INPUT ;
    USE SIGNAL ;
    PORT
      LAYER M4 ;
        RECT  0 16.944 0.192 16.968 ;
    END
  END di0[293]
  PIN di0[294]
    DIRECTION INPUT ;
    USE SIGNAL ;
    PORT
      LAYER M4 ;
        RECT  0 16.992 0.192 17.016 ;
    END
  END di0[294]
  PIN di0[295]
    DIRECTION INPUT ;
    USE SIGNAL ;
    PORT
      LAYER M4 ;
        RECT  0 17.04 0.192 17.064 ;
    END
  END di0[295]
  PIN di0[296]
    DIRECTION INPUT ;
    USE SIGNAL ;
    PORT
      LAYER M4 ;
        RECT  0 17.088 0.192 17.112 ;
    END
  END di0[296]
  PIN di0[297]
    DIRECTION INPUT ;
    USE SIGNAL ;
    PORT
      LAYER M4 ;
        RECT  0 17.136 0.192 17.16 ;
    END
  END di0[297]
  PIN di0[298]
    DIRECTION INPUT ;
    USE SIGNAL ;
    PORT
      LAYER M4 ;
        RECT  0 17.184 0.192 17.208 ;
    END
  END di0[298]
  PIN di0[299]
    DIRECTION INPUT ;
    USE SIGNAL ;
    PORT
      LAYER M4 ;
        RECT  0 17.232 0.192 17.256 ;
    END
  END di0[299]
  PIN di0[29]
    DIRECTION INPUT ;
    USE SIGNAL ;
    PORT
      LAYER M4 ;
        RECT  0 4.272 0.192 4.296 ;
    END
  END di0[29]
  PIN di0[2]
    DIRECTION INPUT ;
    USE SIGNAL ;
    PORT
      LAYER M4 ;
        RECT  0 2.976 0.192 3 ;
    END
  END di0[2]
  PIN di0[300]
    DIRECTION INPUT ;
    USE SIGNAL ;
    PORT
      LAYER M4 ;
        RECT  0 17.28 0.192 17.304 ;
    END
  END di0[300]
  PIN di0[301]
    DIRECTION INPUT ;
    USE SIGNAL ;
    PORT
      LAYER M4 ;
        RECT  0 17.328 0.192 17.352 ;
    END
  END di0[301]
  PIN di0[302]
    DIRECTION INPUT ;
    USE SIGNAL ;
    PORT
      LAYER M4 ;
        RECT  0 17.376 0.192 17.4 ;
    END
  END di0[302]
  PIN di0[303]
    DIRECTION INPUT ;
    USE SIGNAL ;
    PORT
      LAYER M4 ;
        RECT  0 17.424 0.192 17.448 ;
    END
  END di0[303]
  PIN di0[304]
    DIRECTION INPUT ;
    USE SIGNAL ;
    PORT
      LAYER M4 ;
        RECT  0 17.472 0.192 17.496 ;
    END
  END di0[304]
  PIN di0[305]
    DIRECTION INPUT ;
    USE SIGNAL ;
    PORT
      LAYER M4 ;
        RECT  0 17.52 0.192 17.544 ;
    END
  END di0[305]
  PIN di0[306]
    DIRECTION INPUT ;
    USE SIGNAL ;
    PORT
      LAYER M4 ;
        RECT  0 17.568 0.192 17.592 ;
    END
  END di0[306]
  PIN di0[307]
    DIRECTION INPUT ;
    USE SIGNAL ;
    PORT
      LAYER M4 ;
        RECT  0 17.616 0.192 17.64 ;
    END
  END di0[307]
  PIN di0[308]
    DIRECTION INPUT ;
    USE SIGNAL ;
    PORT
      LAYER M4 ;
        RECT  0 17.664 0.192 17.688 ;
    END
  END di0[308]
  PIN di0[309]
    DIRECTION INPUT ;
    USE SIGNAL ;
    PORT
      LAYER M4 ;
        RECT  0 17.712 0.192 17.736 ;
    END
  END di0[309]
  PIN di0[30]
    DIRECTION INPUT ;
    USE SIGNAL ;
    PORT
      LAYER M4 ;
        RECT  0 4.32 0.192 4.344 ;
    END
  END di0[30]
  PIN di0[310]
    DIRECTION INPUT ;
    USE SIGNAL ;
    PORT
      LAYER M4 ;
        RECT  0 17.76 0.192 17.784 ;
    END
  END di0[310]
  PIN di0[311]
    DIRECTION INPUT ;
    USE SIGNAL ;
    PORT
      LAYER M4 ;
        RECT  0 17.808 0.192 17.832 ;
    END
  END di0[311]
  PIN di0[312]
    DIRECTION INPUT ;
    USE SIGNAL ;
    PORT
      LAYER M4 ;
        RECT  0 17.856 0.192 17.88 ;
    END
  END di0[312]
  PIN di0[313]
    DIRECTION INPUT ;
    USE SIGNAL ;
    PORT
      LAYER M4 ;
        RECT  0 17.904 0.192 17.928 ;
    END
  END di0[313]
  PIN di0[314]
    DIRECTION INPUT ;
    USE SIGNAL ;
    PORT
      LAYER M4 ;
        RECT  0 17.952 0.192 17.976 ;
    END
  END di0[314]
  PIN di0[315]
    DIRECTION INPUT ;
    USE SIGNAL ;
    PORT
      LAYER M4 ;
        RECT  0 18 0.192 18.024 ;
    END
  END di0[315]
  PIN di0[316]
    DIRECTION INPUT ;
    USE SIGNAL ;
    PORT
      LAYER M4 ;
        RECT  0 18.048 0.192 18.072 ;
    END
  END di0[316]
  PIN di0[317]
    DIRECTION INPUT ;
    USE SIGNAL ;
    PORT
      LAYER M4 ;
        RECT  0 18.096 0.192 18.12 ;
    END
  END di0[317]
  PIN di0[318]
    DIRECTION INPUT ;
    USE SIGNAL ;
    PORT
      LAYER M4 ;
        RECT  0 18.144 0.192 18.168 ;
    END
  END di0[318]
  PIN di0[319]
    DIRECTION INPUT ;
    USE SIGNAL ;
    PORT
      LAYER M4 ;
        RECT  0 18.192 0.192 18.216 ;
    END
  END di0[319]
  PIN di0[31]
    DIRECTION INPUT ;
    USE SIGNAL ;
    PORT
      LAYER M4 ;
        RECT  0 4.368 0.192 4.392 ;
    END
  END di0[31]
  PIN di0[320]
    DIRECTION INPUT ;
    USE SIGNAL ;
    PORT
      LAYER M4 ;
        RECT  0 18.24 0.192 18.264 ;
    END
  END di0[320]
  PIN di0[321]
    DIRECTION INPUT ;
    USE SIGNAL ;
    PORT
      LAYER M4 ;
        RECT  0 18.288 0.192 18.312 ;
    END
  END di0[321]
  PIN di0[322]
    DIRECTION INPUT ;
    USE SIGNAL ;
    PORT
      LAYER M4 ;
        RECT  0 18.336 0.192 18.36 ;
    END
  END di0[322]
  PIN di0[323]
    DIRECTION INPUT ;
    USE SIGNAL ;
    PORT
      LAYER M4 ;
        RECT  0 18.384 0.192 18.408 ;
    END
  END di0[323]
  PIN di0[324]
    DIRECTION INPUT ;
    USE SIGNAL ;
    PORT
      LAYER M4 ;
        RECT  0 18.432 0.192 18.456 ;
    END
  END di0[324]
  PIN di0[325]
    DIRECTION INPUT ;
    USE SIGNAL ;
    PORT
      LAYER M4 ;
        RECT  0 18.48 0.192 18.504 ;
    END
  END di0[325]
  PIN di0[326]
    DIRECTION INPUT ;
    USE SIGNAL ;
    PORT
      LAYER M4 ;
        RECT  0 18.528 0.192 18.552 ;
    END
  END di0[326]
  PIN di0[327]
    DIRECTION INPUT ;
    USE SIGNAL ;
    PORT
      LAYER M4 ;
        RECT  0 18.576 0.192 18.6 ;
    END
  END di0[327]
  PIN di0[328]
    DIRECTION INPUT ;
    USE SIGNAL ;
    PORT
      LAYER M4 ;
        RECT  0 18.624 0.192 18.648 ;
    END
  END di0[328]
  PIN di0[329]
    DIRECTION INPUT ;
    USE SIGNAL ;
    PORT
      LAYER M4 ;
        RECT  0 18.672 0.192 18.696 ;
    END
  END di0[329]
  PIN di0[32]
    DIRECTION INPUT ;
    USE SIGNAL ;
    PORT
      LAYER M4 ;
        RECT  0 4.416 0.192 4.44 ;
    END
  END di0[32]
  PIN di0[330]
    DIRECTION INPUT ;
    USE SIGNAL ;
    PORT
      LAYER M4 ;
        RECT  0 18.72 0.192 18.744 ;
    END
  END di0[330]
  PIN di0[331]
    DIRECTION INPUT ;
    USE SIGNAL ;
    PORT
      LAYER M4 ;
        RECT  0 18.768 0.192 18.792 ;
    END
  END di0[331]
  PIN di0[332]
    DIRECTION INPUT ;
    USE SIGNAL ;
    PORT
      LAYER M4 ;
        RECT  0 18.816 0.192 18.84 ;
    END
  END di0[332]
  PIN di0[333]
    DIRECTION INPUT ;
    USE SIGNAL ;
    PORT
      LAYER M4 ;
        RECT  0 18.864 0.192 18.888 ;
    END
  END di0[333]
  PIN di0[334]
    DIRECTION INPUT ;
    USE SIGNAL ;
    PORT
      LAYER M4 ;
        RECT  0 18.912 0.192 18.936 ;
    END
  END di0[334]
  PIN di0[335]
    DIRECTION INPUT ;
    USE SIGNAL ;
    PORT
      LAYER M4 ;
        RECT  0 18.96 0.192 18.984 ;
    END
  END di0[335]
  PIN di0[336]
    DIRECTION INPUT ;
    USE SIGNAL ;
    PORT
      LAYER M4 ;
        RECT  0 19.008 0.192 19.032 ;
    END
  END di0[336]
  PIN di0[337]
    DIRECTION INPUT ;
    USE SIGNAL ;
    PORT
      LAYER M4 ;
        RECT  0 19.056 0.192 19.08 ;
    END
  END di0[337]
  PIN di0[338]
    DIRECTION INPUT ;
    USE SIGNAL ;
    PORT
      LAYER M4 ;
        RECT  0 19.104 0.192 19.128 ;
    END
  END di0[338]
  PIN di0[339]
    DIRECTION INPUT ;
    USE SIGNAL ;
    PORT
      LAYER M4 ;
        RECT  0 19.152 0.192 19.176 ;
    END
  END di0[339]
  PIN di0[33]
    DIRECTION INPUT ;
    USE SIGNAL ;
    PORT
      LAYER M4 ;
        RECT  0 4.464 0.192 4.488 ;
    END
  END di0[33]
  PIN di0[340]
    DIRECTION INPUT ;
    USE SIGNAL ;
    PORT
      LAYER M4 ;
        RECT  0 19.2 0.192 19.224 ;
    END
  END di0[340]
  PIN di0[341]
    DIRECTION INPUT ;
    USE SIGNAL ;
    PORT
      LAYER M4 ;
        RECT  0 19.248 0.192 19.272 ;
    END
  END di0[341]
  PIN di0[342]
    DIRECTION INPUT ;
    USE SIGNAL ;
    PORT
      LAYER M4 ;
        RECT  0 19.296 0.192 19.32 ;
    END
  END di0[342]
  PIN di0[343]
    DIRECTION INPUT ;
    USE SIGNAL ;
    PORT
      LAYER M4 ;
        RECT  0 19.344 0.192 19.368 ;
    END
  END di0[343]
  PIN di0[344]
    DIRECTION INPUT ;
    USE SIGNAL ;
    PORT
      LAYER M4 ;
        RECT  0 19.392 0.192 19.416 ;
    END
  END di0[344]
  PIN di0[345]
    DIRECTION INPUT ;
    USE SIGNAL ;
    PORT
      LAYER M4 ;
        RECT  0 19.44 0.192 19.464 ;
    END
  END di0[345]
  PIN di0[346]
    DIRECTION INPUT ;
    USE SIGNAL ;
    PORT
      LAYER M4 ;
        RECT  0 19.488 0.192 19.512 ;
    END
  END di0[346]
  PIN di0[347]
    DIRECTION INPUT ;
    USE SIGNAL ;
    PORT
      LAYER M4 ;
        RECT  0 19.536 0.192 19.56 ;
    END
  END di0[347]
  PIN di0[348]
    DIRECTION INPUT ;
    USE SIGNAL ;
    PORT
      LAYER M4 ;
        RECT  0 19.584 0.192 19.608 ;
    END
  END di0[348]
  PIN di0[349]
    DIRECTION INPUT ;
    USE SIGNAL ;
    PORT
      LAYER M4 ;
        RECT  0 19.632 0.192 19.656 ;
    END
  END di0[349]
  PIN di0[34]
    DIRECTION INPUT ;
    USE SIGNAL ;
    PORT
      LAYER M4 ;
        RECT  0 4.512 0.192 4.536 ;
    END
  END di0[34]
  PIN di0[350]
    DIRECTION INPUT ;
    USE SIGNAL ;
    PORT
      LAYER M4 ;
        RECT  0 19.68 0.192 19.704 ;
    END
  END di0[350]
  PIN di0[351]
    DIRECTION INPUT ;
    USE SIGNAL ;
    PORT
      LAYER M4 ;
        RECT  0 19.728 0.192 19.752 ;
    END
  END di0[351]
  PIN di0[352]
    DIRECTION INPUT ;
    USE SIGNAL ;
    PORT
      LAYER M4 ;
        RECT  0 19.776 0.192 19.8 ;
    END
  END di0[352]
  PIN di0[353]
    DIRECTION INPUT ;
    USE SIGNAL ;
    PORT
      LAYER M4 ;
        RECT  0 19.824 0.192 19.848 ;
    END
  END di0[353]
  PIN di0[354]
    DIRECTION INPUT ;
    USE SIGNAL ;
    PORT
      LAYER M4 ;
        RECT  0 19.872 0.192 19.896 ;
    END
  END di0[354]
  PIN di0[355]
    DIRECTION INPUT ;
    USE SIGNAL ;
    PORT
      LAYER M4 ;
        RECT  0 19.92 0.192 19.944 ;
    END
  END di0[355]
  PIN di0[356]
    DIRECTION INPUT ;
    USE SIGNAL ;
    PORT
      LAYER M4 ;
        RECT  0 19.968 0.192 19.992 ;
    END
  END di0[356]
  PIN di0[357]
    DIRECTION INPUT ;
    USE SIGNAL ;
    PORT
      LAYER M4 ;
        RECT  0 20.016 0.192 20.04 ;
    END
  END di0[357]
  PIN di0[358]
    DIRECTION INPUT ;
    USE SIGNAL ;
    PORT
      LAYER M4 ;
        RECT  0 20.064 0.192 20.088 ;
    END
  END di0[358]
  PIN di0[359]
    DIRECTION INPUT ;
    USE SIGNAL ;
    PORT
      LAYER M4 ;
        RECT  0 20.112 0.192 20.136 ;
    END
  END di0[359]
  PIN di0[35]
    DIRECTION INPUT ;
    USE SIGNAL ;
    PORT
      LAYER M4 ;
        RECT  0 4.56 0.192 4.584 ;
    END
  END di0[35]
  PIN di0[360]
    DIRECTION INPUT ;
    USE SIGNAL ;
    PORT
      LAYER M4 ;
        RECT  0 20.16 0.192 20.184 ;
    END
  END di0[360]
  PIN di0[361]
    DIRECTION INPUT ;
    USE SIGNAL ;
    PORT
      LAYER M4 ;
        RECT  0 20.208 0.192 20.232 ;
    END
  END di0[361]
  PIN di0[362]
    DIRECTION INPUT ;
    USE SIGNAL ;
    PORT
      LAYER M4 ;
        RECT  0 20.256 0.192 20.28 ;
    END
  END di0[362]
  PIN di0[363]
    DIRECTION INPUT ;
    USE SIGNAL ;
    PORT
      LAYER M4 ;
        RECT  0 20.304 0.192 20.328 ;
    END
  END di0[363]
  PIN di0[364]
    DIRECTION INPUT ;
    USE SIGNAL ;
    PORT
      LAYER M4 ;
        RECT  0 20.352 0.192 20.376 ;
    END
  END di0[364]
  PIN di0[365]
    DIRECTION INPUT ;
    USE SIGNAL ;
    PORT
      LAYER M4 ;
        RECT  0 20.4 0.192 20.424 ;
    END
  END di0[365]
  PIN di0[366]
    DIRECTION INPUT ;
    USE SIGNAL ;
    PORT
      LAYER M4 ;
        RECT  0 20.448 0.192 20.472 ;
    END
  END di0[366]
  PIN di0[367]
    DIRECTION INPUT ;
    USE SIGNAL ;
    PORT
      LAYER M4 ;
        RECT  0 20.496 0.192 20.52 ;
    END
  END di0[367]
  PIN di0[368]
    DIRECTION INPUT ;
    USE SIGNAL ;
    PORT
      LAYER M4 ;
        RECT  0 20.544 0.192 20.568 ;
    END
  END di0[368]
  PIN di0[369]
    DIRECTION INPUT ;
    USE SIGNAL ;
    PORT
      LAYER M4 ;
        RECT  0 20.592 0.192 20.616 ;
    END
  END di0[369]
  PIN di0[36]
    DIRECTION INPUT ;
    USE SIGNAL ;
    PORT
      LAYER M4 ;
        RECT  0 4.608 0.192 4.632 ;
    END
  END di0[36]
  PIN di0[370]
    DIRECTION INPUT ;
    USE SIGNAL ;
    PORT
      LAYER M4 ;
        RECT  0 20.64 0.192 20.664 ;
    END
  END di0[370]
  PIN di0[371]
    DIRECTION INPUT ;
    USE SIGNAL ;
    PORT
      LAYER M4 ;
        RECT  0 20.688 0.192 20.712 ;
    END
  END di0[371]
  PIN di0[372]
    DIRECTION INPUT ;
    USE SIGNAL ;
    PORT
      LAYER M4 ;
        RECT  0 20.736 0.192 20.76 ;
    END
  END di0[372]
  PIN di0[373]
    DIRECTION INPUT ;
    USE SIGNAL ;
    PORT
      LAYER M4 ;
        RECT  0 20.784 0.192 20.808 ;
    END
  END di0[373]
  PIN di0[374]
    DIRECTION INPUT ;
    USE SIGNAL ;
    PORT
      LAYER M4 ;
        RECT  0 20.832 0.192 20.856 ;
    END
  END di0[374]
  PIN di0[375]
    DIRECTION INPUT ;
    USE SIGNAL ;
    PORT
      LAYER M4 ;
        RECT  0 20.88 0.192 20.904 ;
    END
  END di0[375]
  PIN di0[376]
    DIRECTION INPUT ;
    USE SIGNAL ;
    PORT
      LAYER M4 ;
        RECT  0 20.928 0.192 20.952 ;
    END
  END di0[376]
  PIN di0[377]
    DIRECTION INPUT ;
    USE SIGNAL ;
    PORT
      LAYER M4 ;
        RECT  0 20.976 0.192 21 ;
    END
  END di0[377]
  PIN di0[378]
    DIRECTION INPUT ;
    USE SIGNAL ;
    PORT
      LAYER M4 ;
        RECT  0 21.024 0.192 21.048 ;
    END
  END di0[378]
  PIN di0[379]
    DIRECTION INPUT ;
    USE SIGNAL ;
    PORT
      LAYER M4 ;
        RECT  0 21.072 0.192 21.096 ;
    END
  END di0[379]
  PIN di0[37]
    DIRECTION INPUT ;
    USE SIGNAL ;
    PORT
      LAYER M4 ;
        RECT  0 4.656 0.192 4.68 ;
    END
  END di0[37]
  PIN di0[380]
    DIRECTION INPUT ;
    USE SIGNAL ;
    PORT
      LAYER M4 ;
        RECT  0 21.12 0.192 21.144 ;
    END
  END di0[380]
  PIN di0[381]
    DIRECTION INPUT ;
    USE SIGNAL ;
    PORT
      LAYER M4 ;
        RECT  0 21.168 0.192 21.192 ;
    END
  END di0[381]
  PIN di0[382]
    DIRECTION INPUT ;
    USE SIGNAL ;
    PORT
      LAYER M4 ;
        RECT  0 21.216 0.192 21.24 ;
    END
  END di0[382]
  PIN di0[383]
    DIRECTION INPUT ;
    USE SIGNAL ;
    PORT
      LAYER M4 ;
        RECT  0 21.264 0.192 21.288 ;
    END
  END di0[383]
  PIN di0[384]
    DIRECTION INPUT ;
    USE SIGNAL ;
    PORT
      LAYER M4 ;
        RECT  0 21.312 0.192 21.336 ;
    END
  END di0[384]
  PIN di0[385]
    DIRECTION INPUT ;
    USE SIGNAL ;
    PORT
      LAYER M4 ;
        RECT  0 21.36 0.192 21.384 ;
    END
  END di0[385]
  PIN di0[386]
    DIRECTION INPUT ;
    USE SIGNAL ;
    PORT
      LAYER M4 ;
        RECT  0 21.408 0.192 21.432 ;
    END
  END di0[386]
  PIN di0[387]
    DIRECTION INPUT ;
    USE SIGNAL ;
    PORT
      LAYER M4 ;
        RECT  0 21.456 0.192 21.48 ;
    END
  END di0[387]
  PIN di0[388]
    DIRECTION INPUT ;
    USE SIGNAL ;
    PORT
      LAYER M4 ;
        RECT  0 21.504 0.192 21.528 ;
    END
  END di0[388]
  PIN di0[389]
    DIRECTION INPUT ;
    USE SIGNAL ;
    PORT
      LAYER M4 ;
        RECT  0 21.552 0.192 21.576 ;
    END
  END di0[389]
  PIN di0[38]
    DIRECTION INPUT ;
    USE SIGNAL ;
    PORT
      LAYER M4 ;
        RECT  0 4.704 0.192 4.728 ;
    END
  END di0[38]
  PIN di0[390]
    DIRECTION INPUT ;
    USE SIGNAL ;
    PORT
      LAYER M4 ;
        RECT  0 21.6 0.192 21.624 ;
    END
  END di0[390]
  PIN di0[391]
    DIRECTION INPUT ;
    USE SIGNAL ;
    PORT
      LAYER M4 ;
        RECT  0 21.648 0.192 21.672 ;
    END
  END di0[391]
  PIN di0[392]
    DIRECTION INPUT ;
    USE SIGNAL ;
    PORT
      LAYER M4 ;
        RECT  0 21.696 0.192 21.72 ;
    END
  END di0[392]
  PIN di0[393]
    DIRECTION INPUT ;
    USE SIGNAL ;
    PORT
      LAYER M4 ;
        RECT  0 21.744 0.192 21.768 ;
    END
  END di0[393]
  PIN di0[394]
    DIRECTION INPUT ;
    USE SIGNAL ;
    PORT
      LAYER M4 ;
        RECT  0 21.792 0.192 21.816 ;
    END
  END di0[394]
  PIN di0[395]
    DIRECTION INPUT ;
    USE SIGNAL ;
    PORT
      LAYER M4 ;
        RECT  0 21.84 0.192 21.864 ;
    END
  END di0[395]
  PIN di0[396]
    DIRECTION INPUT ;
    USE SIGNAL ;
    PORT
      LAYER M4 ;
        RECT  0 21.888 0.192 21.912 ;
    END
  END di0[396]
  PIN di0[397]
    DIRECTION INPUT ;
    USE SIGNAL ;
    PORT
      LAYER M4 ;
        RECT  0 21.936 0.192 21.96 ;
    END
  END di0[397]
  PIN di0[398]
    DIRECTION INPUT ;
    USE SIGNAL ;
    PORT
      LAYER M4 ;
        RECT  0 21.984 0.192 22.008 ;
    END
  END di0[398]
  PIN di0[399]
    DIRECTION INPUT ;
    USE SIGNAL ;
    PORT
      LAYER M4 ;
        RECT  0 22.032 0.192 22.056 ;
    END
  END di0[399]
  PIN di0[39]
    DIRECTION INPUT ;
    USE SIGNAL ;
    PORT
      LAYER M4 ;
        RECT  0 4.752 0.192 4.776 ;
    END
  END di0[39]
  PIN di0[3]
    DIRECTION INPUT ;
    USE SIGNAL ;
    PORT
      LAYER M4 ;
        RECT  0 3.024 0.192 3.048 ;
    END
  END di0[3]
  PIN di0[400]
    DIRECTION INPUT ;
    USE SIGNAL ;
    PORT
      LAYER M4 ;
        RECT  0 22.08 0.192 22.104 ;
    END
  END di0[400]
  PIN di0[401]
    DIRECTION INPUT ;
    USE SIGNAL ;
    PORT
      LAYER M4 ;
        RECT  0 22.128 0.192 22.152 ;
    END
  END di0[401]
  PIN di0[402]
    DIRECTION INPUT ;
    USE SIGNAL ;
    PORT
      LAYER M4 ;
        RECT  0 22.176 0.192 22.2 ;
    END
  END di0[402]
  PIN di0[403]
    DIRECTION INPUT ;
    USE SIGNAL ;
    PORT
      LAYER M4 ;
        RECT  0 22.224 0.192 22.248 ;
    END
  END di0[403]
  PIN di0[404]
    DIRECTION INPUT ;
    USE SIGNAL ;
    PORT
      LAYER M4 ;
        RECT  0 22.272 0.192 22.296 ;
    END
  END di0[404]
  PIN di0[405]
    DIRECTION INPUT ;
    USE SIGNAL ;
    PORT
      LAYER M4 ;
        RECT  0 22.32 0.192 22.344 ;
    END
  END di0[405]
  PIN di0[406]
    DIRECTION INPUT ;
    USE SIGNAL ;
    PORT
      LAYER M4 ;
        RECT  0 22.368 0.192 22.392 ;
    END
  END di0[406]
  PIN di0[407]
    DIRECTION INPUT ;
    USE SIGNAL ;
    PORT
      LAYER M4 ;
        RECT  0 22.416 0.192 22.44 ;
    END
  END di0[407]
  PIN di0[408]
    DIRECTION INPUT ;
    USE SIGNAL ;
    PORT
      LAYER M4 ;
        RECT  0 22.464 0.192 22.488 ;
    END
  END di0[408]
  PIN di0[409]
    DIRECTION INPUT ;
    USE SIGNAL ;
    PORT
      LAYER M4 ;
        RECT  0 22.512 0.192 22.536 ;
    END
  END di0[409]
  PIN di0[40]
    DIRECTION INPUT ;
    USE SIGNAL ;
    PORT
      LAYER M4 ;
        RECT  0 4.8 0.192 4.824 ;
    END
  END di0[40]
  PIN di0[410]
    DIRECTION INPUT ;
    USE SIGNAL ;
    PORT
      LAYER M4 ;
        RECT  0 22.56 0.192 22.584 ;
    END
  END di0[410]
  PIN di0[411]
    DIRECTION INPUT ;
    USE SIGNAL ;
    PORT
      LAYER M4 ;
        RECT  0 22.608 0.192 22.632 ;
    END
  END di0[411]
  PIN di0[412]
    DIRECTION INPUT ;
    USE SIGNAL ;
    PORT
      LAYER M4 ;
        RECT  0 22.656 0.192 22.68 ;
    END
  END di0[412]
  PIN di0[413]
    DIRECTION INPUT ;
    USE SIGNAL ;
    PORT
      LAYER M4 ;
        RECT  0 22.704 0.192 22.728 ;
    END
  END di0[413]
  PIN di0[414]
    DIRECTION INPUT ;
    USE SIGNAL ;
    PORT
      LAYER M4 ;
        RECT  0 22.752 0.192 22.776 ;
    END
  END di0[414]
  PIN di0[415]
    DIRECTION INPUT ;
    USE SIGNAL ;
    PORT
      LAYER M4 ;
        RECT  0 22.8 0.192 22.824 ;
    END
  END di0[415]
  PIN di0[416]
    DIRECTION INPUT ;
    USE SIGNAL ;
    PORT
      LAYER M4 ;
        RECT  0 22.848 0.192 22.872 ;
    END
  END di0[416]
  PIN di0[417]
    DIRECTION INPUT ;
    USE SIGNAL ;
    PORT
      LAYER M4 ;
        RECT  0 22.896 0.192 22.92 ;
    END
  END di0[417]
  PIN di0[418]
    DIRECTION INPUT ;
    USE SIGNAL ;
    PORT
      LAYER M4 ;
        RECT  0 22.944 0.192 22.968 ;
    END
  END di0[418]
  PIN di0[419]
    DIRECTION INPUT ;
    USE SIGNAL ;
    PORT
      LAYER M4 ;
        RECT  0 22.992 0.192 23.016 ;
    END
  END di0[419]
  PIN di0[41]
    DIRECTION INPUT ;
    USE SIGNAL ;
    PORT
      LAYER M4 ;
        RECT  0 4.848 0.192 4.872 ;
    END
  END di0[41]
  PIN di0[420]
    DIRECTION INPUT ;
    USE SIGNAL ;
    PORT
      LAYER M4 ;
        RECT  0 23.04 0.192 23.064 ;
    END
  END di0[420]
  PIN di0[421]
    DIRECTION INPUT ;
    USE SIGNAL ;
    PORT
      LAYER M4 ;
        RECT  0 23.088 0.192 23.112 ;
    END
  END di0[421]
  PIN di0[422]
    DIRECTION INPUT ;
    USE SIGNAL ;
    PORT
      LAYER M4 ;
        RECT  0 23.136 0.192 23.16 ;
    END
  END di0[422]
  PIN di0[423]
    DIRECTION INPUT ;
    USE SIGNAL ;
    PORT
      LAYER M4 ;
        RECT  0 23.184 0.192 23.208 ;
    END
  END di0[423]
  PIN di0[424]
    DIRECTION INPUT ;
    USE SIGNAL ;
    PORT
      LAYER M4 ;
        RECT  0 23.232 0.192 23.256 ;
    END
  END di0[424]
  PIN di0[425]
    DIRECTION INPUT ;
    USE SIGNAL ;
    PORT
      LAYER M4 ;
        RECT  0 23.28 0.192 23.304 ;
    END
  END di0[425]
  PIN di0[426]
    DIRECTION INPUT ;
    USE SIGNAL ;
    PORT
      LAYER M4 ;
        RECT  0 23.328 0.192 23.352 ;
    END
  END di0[426]
  PIN di0[427]
    DIRECTION INPUT ;
    USE SIGNAL ;
    PORT
      LAYER M4 ;
        RECT  0 23.376 0.192 23.4 ;
    END
  END di0[427]
  PIN di0[428]
    DIRECTION INPUT ;
    USE SIGNAL ;
    PORT
      LAYER M4 ;
        RECT  0 23.424 0.192 23.448 ;
    END
  END di0[428]
  PIN di0[429]
    DIRECTION INPUT ;
    USE SIGNAL ;
    PORT
      LAYER M4 ;
        RECT  0 23.472 0.192 23.496 ;
    END
  END di0[429]
  PIN di0[42]
    DIRECTION INPUT ;
    USE SIGNAL ;
    PORT
      LAYER M4 ;
        RECT  0 4.896 0.192 4.92 ;
    END
  END di0[42]
  PIN di0[430]
    DIRECTION INPUT ;
    USE SIGNAL ;
    PORT
      LAYER M4 ;
        RECT  0 23.52 0.192 23.544 ;
    END
  END di0[430]
  PIN di0[431]
    DIRECTION INPUT ;
    USE SIGNAL ;
    PORT
      LAYER M4 ;
        RECT  0 23.568 0.192 23.592 ;
    END
  END di0[431]
  PIN di0[432]
    DIRECTION INPUT ;
    USE SIGNAL ;
    PORT
      LAYER M4 ;
        RECT  0 23.616 0.192 23.64 ;
    END
  END di0[432]
  PIN di0[433]
    DIRECTION INPUT ;
    USE SIGNAL ;
    PORT
      LAYER M4 ;
        RECT  0 23.664 0.192 23.688 ;
    END
  END di0[433]
  PIN di0[434]
    DIRECTION INPUT ;
    USE SIGNAL ;
    PORT
      LAYER M4 ;
        RECT  0 23.712 0.192 23.736 ;
    END
  END di0[434]
  PIN di0[435]
    DIRECTION INPUT ;
    USE SIGNAL ;
    PORT
      LAYER M4 ;
        RECT  0 23.76 0.192 23.784 ;
    END
  END di0[435]
  PIN di0[436]
    DIRECTION INPUT ;
    USE SIGNAL ;
    PORT
      LAYER M4 ;
        RECT  0 23.808 0.192 23.832 ;
    END
  END di0[436]
  PIN di0[437]
    DIRECTION INPUT ;
    USE SIGNAL ;
    PORT
      LAYER M4 ;
        RECT  0 23.856 0.192 23.88 ;
    END
  END di0[437]
  PIN di0[438]
    DIRECTION INPUT ;
    USE SIGNAL ;
    PORT
      LAYER M4 ;
        RECT  0 23.904 0.192 23.928 ;
    END
  END di0[438]
  PIN di0[439]
    DIRECTION INPUT ;
    USE SIGNAL ;
    PORT
      LAYER M4 ;
        RECT  0 23.952 0.192 23.976 ;
    END
  END di0[439]
  PIN di0[43]
    DIRECTION INPUT ;
    USE SIGNAL ;
    PORT
      LAYER M4 ;
        RECT  0 4.944 0.192 4.968 ;
    END
  END di0[43]
  PIN di0[440]
    DIRECTION INPUT ;
    USE SIGNAL ;
    PORT
      LAYER M4 ;
        RECT  0 24 0.192 24.024 ;
    END
  END di0[440]
  PIN di0[441]
    DIRECTION INPUT ;
    USE SIGNAL ;
    PORT
      LAYER M4 ;
        RECT  0 24.048 0.192 24.072 ;
    END
  END di0[441]
  PIN di0[442]
    DIRECTION INPUT ;
    USE SIGNAL ;
    PORT
      LAYER M4 ;
        RECT  0 24.096 0.192 24.12 ;
    END
  END di0[442]
  PIN di0[443]
    DIRECTION INPUT ;
    USE SIGNAL ;
    PORT
      LAYER M4 ;
        RECT  0 24.144 0.192 24.168 ;
    END
  END di0[443]
  PIN di0[444]
    DIRECTION INPUT ;
    USE SIGNAL ;
    PORT
      LAYER M4 ;
        RECT  0 24.192 0.192 24.216 ;
    END
  END di0[444]
  PIN di0[445]
    DIRECTION INPUT ;
    USE SIGNAL ;
    PORT
      LAYER M4 ;
        RECT  0 24.24 0.192 24.264 ;
    END
  END di0[445]
  PIN di0[446]
    DIRECTION INPUT ;
    USE SIGNAL ;
    PORT
      LAYER M4 ;
        RECT  0 24.288 0.192 24.312 ;
    END
  END di0[446]
  PIN di0[447]
    DIRECTION INPUT ;
    USE SIGNAL ;
    PORT
      LAYER M4 ;
        RECT  0 24.336 0.192 24.36 ;
    END
  END di0[447]
  PIN di0[448]
    DIRECTION INPUT ;
    USE SIGNAL ;
    PORT
      LAYER M4 ;
        RECT  0 24.384 0.192 24.408 ;
    END
  END di0[448]
  PIN di0[449]
    DIRECTION INPUT ;
    USE SIGNAL ;
    PORT
      LAYER M4 ;
        RECT  0 24.432 0.192 24.456 ;
    END
  END di0[449]
  PIN di0[44]
    DIRECTION INPUT ;
    USE SIGNAL ;
    PORT
      LAYER M4 ;
        RECT  0 4.992 0.192 5.016 ;
    END
  END di0[44]
  PIN di0[450]
    DIRECTION INPUT ;
    USE SIGNAL ;
    PORT
      LAYER M4 ;
        RECT  0 24.48 0.192 24.504 ;
    END
  END di0[450]
  PIN di0[451]
    DIRECTION INPUT ;
    USE SIGNAL ;
    PORT
      LAYER M4 ;
        RECT  0 24.528 0.192 24.552 ;
    END
  END di0[451]
  PIN di0[452]
    DIRECTION INPUT ;
    USE SIGNAL ;
    PORT
      LAYER M4 ;
        RECT  0 24.576 0.192 24.6 ;
    END
  END di0[452]
  PIN di0[453]
    DIRECTION INPUT ;
    USE SIGNAL ;
    PORT
      LAYER M4 ;
        RECT  0 24.624 0.192 24.648 ;
    END
  END di0[453]
  PIN di0[454]
    DIRECTION INPUT ;
    USE SIGNAL ;
    PORT
      LAYER M4 ;
        RECT  0 24.672 0.192 24.696 ;
    END
  END di0[454]
  PIN di0[455]
    DIRECTION INPUT ;
    USE SIGNAL ;
    PORT
      LAYER M4 ;
        RECT  0 24.72 0.192 24.744 ;
    END
  END di0[455]
  PIN di0[456]
    DIRECTION INPUT ;
    USE SIGNAL ;
    PORT
      LAYER M4 ;
        RECT  0 24.768 0.192 24.792 ;
    END
  END di0[456]
  PIN di0[457]
    DIRECTION INPUT ;
    USE SIGNAL ;
    PORT
      LAYER M4 ;
        RECT  0 24.816 0.192 24.84 ;
    END
  END di0[457]
  PIN di0[458]
    DIRECTION INPUT ;
    USE SIGNAL ;
    PORT
      LAYER M4 ;
        RECT  0 24.864 0.192 24.888 ;
    END
  END di0[458]
  PIN di0[459]
    DIRECTION INPUT ;
    USE SIGNAL ;
    PORT
      LAYER M4 ;
        RECT  0 24.912 0.192 24.936 ;
    END
  END di0[459]
  PIN di0[45]
    DIRECTION INPUT ;
    USE SIGNAL ;
    PORT
      LAYER M4 ;
        RECT  0 5.04 0.192 5.064 ;
    END
  END di0[45]
  PIN di0[460]
    DIRECTION INPUT ;
    USE SIGNAL ;
    PORT
      LAYER M4 ;
        RECT  0 24.96 0.192 24.984 ;
    END
  END di0[460]
  PIN di0[461]
    DIRECTION INPUT ;
    USE SIGNAL ;
    PORT
      LAYER M4 ;
        RECT  0 25.008 0.192 25.032 ;
    END
  END di0[461]
  PIN di0[462]
    DIRECTION INPUT ;
    USE SIGNAL ;
    PORT
      LAYER M4 ;
        RECT  0 25.056 0.192 25.08 ;
    END
  END di0[462]
  PIN di0[463]
    DIRECTION INPUT ;
    USE SIGNAL ;
    PORT
      LAYER M4 ;
        RECT  0 25.104 0.192 25.128 ;
    END
  END di0[463]
  PIN di0[464]
    DIRECTION INPUT ;
    USE SIGNAL ;
    PORT
      LAYER M4 ;
        RECT  0 25.152 0.192 25.176 ;
    END
  END di0[464]
  PIN di0[465]
    DIRECTION INPUT ;
    USE SIGNAL ;
    PORT
      LAYER M4 ;
        RECT  0 25.2 0.192 25.224 ;
    END
  END di0[465]
  PIN di0[466]
    DIRECTION INPUT ;
    USE SIGNAL ;
    PORT
      LAYER M4 ;
        RECT  0 25.248 0.192 25.272 ;
    END
  END di0[466]
  PIN di0[467]
    DIRECTION INPUT ;
    USE SIGNAL ;
    PORT
      LAYER M4 ;
        RECT  0 25.296 0.192 25.32 ;
    END
  END di0[467]
  PIN di0[468]
    DIRECTION INPUT ;
    USE SIGNAL ;
    PORT
      LAYER M4 ;
        RECT  0 25.344 0.192 25.368 ;
    END
  END di0[468]
  PIN di0[469]
    DIRECTION INPUT ;
    USE SIGNAL ;
    PORT
      LAYER M4 ;
        RECT  0 25.392 0.192 25.416 ;
    END
  END di0[469]
  PIN di0[46]
    DIRECTION INPUT ;
    USE SIGNAL ;
    PORT
      LAYER M4 ;
        RECT  0 5.088 0.192 5.112 ;
    END
  END di0[46]
  PIN di0[470]
    DIRECTION INPUT ;
    USE SIGNAL ;
    PORT
      LAYER M4 ;
        RECT  0 25.44 0.192 25.464 ;
    END
  END di0[470]
  PIN di0[471]
    DIRECTION INPUT ;
    USE SIGNAL ;
    PORT
      LAYER M4 ;
        RECT  0 25.488 0.192 25.512 ;
    END
  END di0[471]
  PIN di0[472]
    DIRECTION INPUT ;
    USE SIGNAL ;
    PORT
      LAYER M4 ;
        RECT  0 25.536 0.192 25.56 ;
    END
  END di0[472]
  PIN di0[473]
    DIRECTION INPUT ;
    USE SIGNAL ;
    PORT
      LAYER M4 ;
        RECT  0 25.584 0.192 25.608 ;
    END
  END di0[473]
  PIN di0[474]
    DIRECTION INPUT ;
    USE SIGNAL ;
    PORT
      LAYER M4 ;
        RECT  0 25.632 0.192 25.656 ;
    END
  END di0[474]
  PIN di0[475]
    DIRECTION INPUT ;
    USE SIGNAL ;
    PORT
      LAYER M4 ;
        RECT  0 25.68 0.192 25.704 ;
    END
  END di0[475]
  PIN di0[476]
    DIRECTION INPUT ;
    USE SIGNAL ;
    PORT
      LAYER M4 ;
        RECT  0 25.728 0.192 25.752 ;
    END
  END di0[476]
  PIN di0[477]
    DIRECTION INPUT ;
    USE SIGNAL ;
    PORT
      LAYER M4 ;
        RECT  0 25.776 0.192 25.8 ;
    END
  END di0[477]
  PIN di0[478]
    DIRECTION INPUT ;
    USE SIGNAL ;
    PORT
      LAYER M4 ;
        RECT  0 25.824 0.192 25.848 ;
    END
  END di0[478]
  PIN di0[479]
    DIRECTION INPUT ;
    USE SIGNAL ;
    PORT
      LAYER M4 ;
        RECT  0 25.872 0.192 25.896 ;
    END
  END di0[479]
  PIN di0[47]
    DIRECTION INPUT ;
    USE SIGNAL ;
    PORT
      LAYER M4 ;
        RECT  0 5.136 0.192 5.16 ;
    END
  END di0[47]
  PIN di0[480]
    DIRECTION INPUT ;
    USE SIGNAL ;
    PORT
      LAYER M4 ;
        RECT  0 25.92 0.192 25.944 ;
    END
  END di0[480]
  PIN di0[481]
    DIRECTION INPUT ;
    USE SIGNAL ;
    PORT
      LAYER M4 ;
        RECT  0 25.968 0.192 25.992 ;
    END
  END di0[481]
  PIN di0[482]
    DIRECTION INPUT ;
    USE SIGNAL ;
    PORT
      LAYER M4 ;
        RECT  0 26.016 0.192 26.04 ;
    END
  END di0[482]
  PIN di0[483]
    DIRECTION INPUT ;
    USE SIGNAL ;
    PORT
      LAYER M4 ;
        RECT  0 26.064 0.192 26.088 ;
    END
  END di0[483]
  PIN di0[484]
    DIRECTION INPUT ;
    USE SIGNAL ;
    PORT
      LAYER M4 ;
        RECT  0 26.112 0.192 26.136 ;
    END
  END di0[484]
  PIN di0[485]
    DIRECTION INPUT ;
    USE SIGNAL ;
    PORT
      LAYER M4 ;
        RECT  0 26.16 0.192 26.184 ;
    END
  END di0[485]
  PIN di0[486]
    DIRECTION INPUT ;
    USE SIGNAL ;
    PORT
      LAYER M4 ;
        RECT  0 26.208 0.192 26.232 ;
    END
  END di0[486]
  PIN di0[487]
    DIRECTION INPUT ;
    USE SIGNAL ;
    PORT
      LAYER M4 ;
        RECT  0 26.256 0.192 26.28 ;
    END
  END di0[487]
  PIN di0[488]
    DIRECTION INPUT ;
    USE SIGNAL ;
    PORT
      LAYER M4 ;
        RECT  0 26.304 0.192 26.328 ;
    END
  END di0[488]
  PIN di0[489]
    DIRECTION INPUT ;
    USE SIGNAL ;
    PORT
      LAYER M4 ;
        RECT  0 26.352 0.192 26.376 ;
    END
  END di0[489]
  PIN di0[48]
    DIRECTION INPUT ;
    USE SIGNAL ;
    PORT
      LAYER M4 ;
        RECT  0 5.184 0.192 5.208 ;
    END
  END di0[48]
  PIN di0[490]
    DIRECTION INPUT ;
    USE SIGNAL ;
    PORT
      LAYER M4 ;
        RECT  0 26.4 0.192 26.424 ;
    END
  END di0[490]
  PIN di0[491]
    DIRECTION INPUT ;
    USE SIGNAL ;
    PORT
      LAYER M4 ;
        RECT  0 26.448 0.192 26.472 ;
    END
  END di0[491]
  PIN di0[492]
    DIRECTION INPUT ;
    USE SIGNAL ;
    PORT
      LAYER M4 ;
        RECT  0 26.496 0.192 26.52 ;
    END
  END di0[492]
  PIN di0[493]
    DIRECTION INPUT ;
    USE SIGNAL ;
    PORT
      LAYER M4 ;
        RECT  0 26.544 0.192 26.568 ;
    END
  END di0[493]
  PIN di0[494]
    DIRECTION INPUT ;
    USE SIGNAL ;
    PORT
      LAYER M4 ;
        RECT  0 26.592 0.192 26.616 ;
    END
  END di0[494]
  PIN di0[495]
    DIRECTION INPUT ;
    USE SIGNAL ;
    PORT
      LAYER M4 ;
        RECT  0 26.64 0.192 26.664 ;
    END
  END di0[495]
  PIN di0[496]
    DIRECTION INPUT ;
    USE SIGNAL ;
    PORT
      LAYER M4 ;
        RECT  0 26.688 0.192 26.712 ;
    END
  END di0[496]
  PIN di0[497]
    DIRECTION INPUT ;
    USE SIGNAL ;
    PORT
      LAYER M4 ;
        RECT  0 26.736 0.192 26.76 ;
    END
  END di0[497]
  PIN di0[498]
    DIRECTION INPUT ;
    USE SIGNAL ;
    PORT
      LAYER M4 ;
        RECT  0 26.784 0.192 26.808 ;
    END
  END di0[498]
  PIN di0[499]
    DIRECTION INPUT ;
    USE SIGNAL ;
    PORT
      LAYER M4 ;
        RECT  0 26.832 0.192 26.856 ;
    END
  END di0[499]
  PIN di0[49]
    DIRECTION INPUT ;
    USE SIGNAL ;
    PORT
      LAYER M4 ;
        RECT  0 5.232 0.192 5.256 ;
    END
  END di0[49]
  PIN di0[4]
    DIRECTION INPUT ;
    USE SIGNAL ;
    PORT
      LAYER M4 ;
        RECT  0 3.072 0.192 3.096 ;
    END
  END di0[4]
  PIN di0[500]
    DIRECTION INPUT ;
    USE SIGNAL ;
    PORT
      LAYER M4 ;
        RECT  0 26.88 0.192 26.904 ;
    END
  END di0[500]
  PIN di0[501]
    DIRECTION INPUT ;
    USE SIGNAL ;
    PORT
      LAYER M4 ;
        RECT  0 26.928 0.192 26.952 ;
    END
  END di0[501]
  PIN di0[502]
    DIRECTION INPUT ;
    USE SIGNAL ;
    PORT
      LAYER M4 ;
        RECT  0 26.976 0.192 27 ;
    END
  END di0[502]
  PIN di0[503]
    DIRECTION INPUT ;
    USE SIGNAL ;
    PORT
      LAYER M4 ;
        RECT  0 27.024 0.192 27.048 ;
    END
  END di0[503]
  PIN di0[504]
    DIRECTION INPUT ;
    USE SIGNAL ;
    PORT
      LAYER M4 ;
        RECT  0 27.072 0.192 27.096 ;
    END
  END di0[504]
  PIN di0[505]
    DIRECTION INPUT ;
    USE SIGNAL ;
    PORT
      LAYER M4 ;
        RECT  0 27.12 0.192 27.144 ;
    END
  END di0[505]
  PIN di0[506]
    DIRECTION INPUT ;
    USE SIGNAL ;
    PORT
      LAYER M4 ;
        RECT  0 27.168 0.192 27.192 ;
    END
  END di0[506]
  PIN di0[507]
    DIRECTION INPUT ;
    USE SIGNAL ;
    PORT
      LAYER M4 ;
        RECT  0 27.216 0.192 27.24 ;
    END
  END di0[507]
  PIN di0[508]
    DIRECTION INPUT ;
    USE SIGNAL ;
    PORT
      LAYER M4 ;
        RECT  0 27.264 0.192 27.288 ;
    END
  END di0[508]
  PIN di0[509]
    DIRECTION INPUT ;
    USE SIGNAL ;
    PORT
      LAYER M4 ;
        RECT  0 27.312 0.192 27.336 ;
    END
  END di0[509]
  PIN di0[50]
    DIRECTION INPUT ;
    USE SIGNAL ;
    PORT
      LAYER M4 ;
        RECT  0 5.28 0.192 5.304 ;
    END
  END di0[50]
  PIN di0[510]
    DIRECTION INPUT ;
    USE SIGNAL ;
    PORT
      LAYER M4 ;
        RECT  0 27.36 0.192 27.384 ;
    END
  END di0[510]
  PIN di0[511]
    DIRECTION INPUT ;
    USE SIGNAL ;
    PORT
      LAYER M4 ;
        RECT  0 27.408 0.192 27.432 ;
    END
  END di0[511]
  PIN di0[512]
    DIRECTION INPUT ;
    USE SIGNAL ;
    PORT
      LAYER M4 ;
        RECT  0 27.456 0.192 27.48 ;
    END
  END di0[512]
  PIN di0[513]
    DIRECTION INPUT ;
    USE SIGNAL ;
    PORT
      LAYER M4 ;
        RECT  0 27.504 0.192 27.528 ;
    END
  END di0[513]
  PIN di0[51]
    DIRECTION INPUT ;
    USE SIGNAL ;
    PORT
      LAYER M4 ;
        RECT  0 5.328 0.192 5.352 ;
    END
  END di0[51]
  PIN di0[52]
    DIRECTION INPUT ;
    USE SIGNAL ;
    PORT
      LAYER M4 ;
        RECT  0 5.376 0.192 5.4 ;
    END
  END di0[52]
  PIN di0[53]
    DIRECTION INPUT ;
    USE SIGNAL ;
    PORT
      LAYER M4 ;
        RECT  0 5.424 0.192 5.448 ;
    END
  END di0[53]
  PIN di0[54]
    DIRECTION INPUT ;
    USE SIGNAL ;
    PORT
      LAYER M4 ;
        RECT  0 5.472 0.192 5.496 ;
    END
  END di0[54]
  PIN di0[55]
    DIRECTION INPUT ;
    USE SIGNAL ;
    PORT
      LAYER M4 ;
        RECT  0 5.52 0.192 5.544 ;
    END
  END di0[55]
  PIN di0[56]
    DIRECTION INPUT ;
    USE SIGNAL ;
    PORT
      LAYER M4 ;
        RECT  0 5.568 0.192 5.592 ;
    END
  END di0[56]
  PIN di0[57]
    DIRECTION INPUT ;
    USE SIGNAL ;
    PORT
      LAYER M4 ;
        RECT  0 5.616 0.192 5.64 ;
    END
  END di0[57]
  PIN di0[58]
    DIRECTION INPUT ;
    USE SIGNAL ;
    PORT
      LAYER M4 ;
        RECT  0 5.664 0.192 5.688 ;
    END
  END di0[58]
  PIN di0[59]
    DIRECTION INPUT ;
    USE SIGNAL ;
    PORT
      LAYER M4 ;
        RECT  0 5.712 0.192 5.736 ;
    END
  END di0[59]
  PIN di0[5]
    DIRECTION INPUT ;
    USE SIGNAL ;
    PORT
      LAYER M4 ;
        RECT  0 3.12 0.192 3.144 ;
    END
  END di0[5]
  PIN di0[60]
    DIRECTION INPUT ;
    USE SIGNAL ;
    PORT
      LAYER M4 ;
        RECT  0 5.76 0.192 5.784 ;
    END
  END di0[60]
  PIN di0[61]
    DIRECTION INPUT ;
    USE SIGNAL ;
    PORT
      LAYER M4 ;
        RECT  0 5.808 0.192 5.832 ;
    END
  END di0[61]
  PIN di0[62]
    DIRECTION INPUT ;
    USE SIGNAL ;
    PORT
      LAYER M4 ;
        RECT  0 5.856 0.192 5.88 ;
    END
  END di0[62]
  PIN di0[63]
    DIRECTION INPUT ;
    USE SIGNAL ;
    PORT
      LAYER M4 ;
        RECT  0 5.904 0.192 5.928 ;
    END
  END di0[63]
  PIN di0[64]
    DIRECTION INPUT ;
    USE SIGNAL ;
    PORT
      LAYER M4 ;
        RECT  0 5.952 0.192 5.976 ;
    END
  END di0[64]
  PIN di0[65]
    DIRECTION INPUT ;
    USE SIGNAL ;
    PORT
      LAYER M4 ;
        RECT  0 6 0.192 6.024 ;
    END
  END di0[65]
  PIN di0[66]
    DIRECTION INPUT ;
    USE SIGNAL ;
    PORT
      LAYER M4 ;
        RECT  0 6.048 0.192 6.072 ;
    END
  END di0[66]
  PIN di0[67]
    DIRECTION INPUT ;
    USE SIGNAL ;
    PORT
      LAYER M4 ;
        RECT  0 6.096 0.192 6.12 ;
    END
  END di0[67]
  PIN di0[68]
    DIRECTION INPUT ;
    USE SIGNAL ;
    PORT
      LAYER M4 ;
        RECT  0 6.144 0.192 6.168 ;
    END
  END di0[68]
  PIN di0[69]
    DIRECTION INPUT ;
    USE SIGNAL ;
    PORT
      LAYER M4 ;
        RECT  0 6.192 0.192 6.216 ;
    END
  END di0[69]
  PIN di0[6]
    DIRECTION INPUT ;
    USE SIGNAL ;
    PORT
      LAYER M4 ;
        RECT  0 3.168 0.192 3.192 ;
    END
  END di0[6]
  PIN di0[70]
    DIRECTION INPUT ;
    USE SIGNAL ;
    PORT
      LAYER M4 ;
        RECT  0 6.24 0.192 6.264 ;
    END
  END di0[70]
  PIN di0[71]
    DIRECTION INPUT ;
    USE SIGNAL ;
    PORT
      LAYER M4 ;
        RECT  0 6.288 0.192 6.312 ;
    END
  END di0[71]
  PIN di0[72]
    DIRECTION INPUT ;
    USE SIGNAL ;
    PORT
      LAYER M4 ;
        RECT  0 6.336 0.192 6.36 ;
    END
  END di0[72]
  PIN di0[73]
    DIRECTION INPUT ;
    USE SIGNAL ;
    PORT
      LAYER M4 ;
        RECT  0 6.384 0.192 6.408 ;
    END
  END di0[73]
  PIN di0[74]
    DIRECTION INPUT ;
    USE SIGNAL ;
    PORT
      LAYER M4 ;
        RECT  0 6.432 0.192 6.456 ;
    END
  END di0[74]
  PIN di0[75]
    DIRECTION INPUT ;
    USE SIGNAL ;
    PORT
      LAYER M4 ;
        RECT  0 6.48 0.192 6.504 ;
    END
  END di0[75]
  PIN di0[76]
    DIRECTION INPUT ;
    USE SIGNAL ;
    PORT
      LAYER M4 ;
        RECT  0 6.528 0.192 6.552 ;
    END
  END di0[76]
  PIN di0[77]
    DIRECTION INPUT ;
    USE SIGNAL ;
    PORT
      LAYER M4 ;
        RECT  0 6.576 0.192 6.6 ;
    END
  END di0[77]
  PIN di0[78]
    DIRECTION INPUT ;
    USE SIGNAL ;
    PORT
      LAYER M4 ;
        RECT  0 6.624 0.192 6.648 ;
    END
  END di0[78]
  PIN di0[79]
    DIRECTION INPUT ;
    USE SIGNAL ;
    PORT
      LAYER M4 ;
        RECT  0 6.672 0.192 6.696 ;
    END
  END di0[79]
  PIN di0[7]
    DIRECTION INPUT ;
    USE SIGNAL ;
    PORT
      LAYER M4 ;
        RECT  0 3.216 0.192 3.24 ;
    END
  END di0[7]
  PIN di0[80]
    DIRECTION INPUT ;
    USE SIGNAL ;
    PORT
      LAYER M4 ;
        RECT  0 6.72 0.192 6.744 ;
    END
  END di0[80]
  PIN di0[81]
    DIRECTION INPUT ;
    USE SIGNAL ;
    PORT
      LAYER M4 ;
        RECT  0 6.768 0.192 6.792 ;
    END
  END di0[81]
  PIN di0[82]
    DIRECTION INPUT ;
    USE SIGNAL ;
    PORT
      LAYER M4 ;
        RECT  0 6.816 0.192 6.84 ;
    END
  END di0[82]
  PIN di0[83]
    DIRECTION INPUT ;
    USE SIGNAL ;
    PORT
      LAYER M4 ;
        RECT  0 6.864 0.192 6.888 ;
    END
  END di0[83]
  PIN di0[84]
    DIRECTION INPUT ;
    USE SIGNAL ;
    PORT
      LAYER M4 ;
        RECT  0 6.912 0.192 6.936 ;
    END
  END di0[84]
  PIN di0[85]
    DIRECTION INPUT ;
    USE SIGNAL ;
    PORT
      LAYER M4 ;
        RECT  0 6.96 0.192 6.984 ;
    END
  END di0[85]
  PIN di0[86]
    DIRECTION INPUT ;
    USE SIGNAL ;
    PORT
      LAYER M4 ;
        RECT  0 7.008 0.192 7.032 ;
    END
  END di0[86]
  PIN di0[87]
    DIRECTION INPUT ;
    USE SIGNAL ;
    PORT
      LAYER M4 ;
        RECT  0 7.056 0.192 7.08 ;
    END
  END di0[87]
  PIN di0[88]
    DIRECTION INPUT ;
    USE SIGNAL ;
    PORT
      LAYER M4 ;
        RECT  0 7.104 0.192 7.128 ;
    END
  END di0[88]
  PIN di0[89]
    DIRECTION INPUT ;
    USE SIGNAL ;
    PORT
      LAYER M4 ;
        RECT  0 7.152 0.192 7.176 ;
    END
  END di0[89]
  PIN di0[8]
    DIRECTION INPUT ;
    USE SIGNAL ;
    PORT
      LAYER M4 ;
        RECT  0 3.264 0.192 3.288 ;
    END
  END di0[8]
  PIN di0[90]
    DIRECTION INPUT ;
    USE SIGNAL ;
    PORT
      LAYER M4 ;
        RECT  0 7.2 0.192 7.224 ;
    END
  END di0[90]
  PIN di0[91]
    DIRECTION INPUT ;
    USE SIGNAL ;
    PORT
      LAYER M4 ;
        RECT  0 7.248 0.192 7.272 ;
    END
  END di0[91]
  PIN di0[92]
    DIRECTION INPUT ;
    USE SIGNAL ;
    PORT
      LAYER M4 ;
        RECT  0 7.296 0.192 7.32 ;
    END
  END di0[92]
  PIN di0[93]
    DIRECTION INPUT ;
    USE SIGNAL ;
    PORT
      LAYER M4 ;
        RECT  0 7.344 0.192 7.368 ;
    END
  END di0[93]
  PIN di0[94]
    DIRECTION INPUT ;
    USE SIGNAL ;
    PORT
      LAYER M4 ;
        RECT  0 7.392 0.192 7.416 ;
    END
  END di0[94]
  PIN di0[95]
    DIRECTION INPUT ;
    USE SIGNAL ;
    PORT
      LAYER M4 ;
        RECT  0 7.44 0.192 7.464 ;
    END
  END di0[95]
  PIN di0[96]
    DIRECTION INPUT ;
    USE SIGNAL ;
    PORT
      LAYER M4 ;
        RECT  0 7.488 0.192 7.512 ;
    END
  END di0[96]
  PIN di0[97]
    DIRECTION INPUT ;
    USE SIGNAL ;
    PORT
      LAYER M4 ;
        RECT  0 7.536 0.192 7.56 ;
    END
  END di0[97]
  PIN di0[98]
    DIRECTION INPUT ;
    USE SIGNAL ;
    PORT
      LAYER M4 ;
        RECT  0 7.584 0.192 7.608 ;
    END
  END di0[98]
  PIN di0[99]
    DIRECTION INPUT ;
    USE SIGNAL ;
    PORT
      LAYER M4 ;
        RECT  0 7.632 0.192 7.656 ;
    END
  END di0[99]
  PIN di0[9]
    DIRECTION INPUT ;
    USE SIGNAL ;
    PORT
      LAYER M4 ;
        RECT  0 3.312 0.192 3.336 ;
    END
  END di0[9]
  PIN do0[0]
    DIRECTION OUTPUT ;
    USE SIGNAL ;
    PORT
      LAYER M4 ;
        RECT  17.064 2.88 17.256 2.904 ;
    END
  END do0[0]
  PIN do0[100]
    DIRECTION OUTPUT ;
    USE SIGNAL ;
    PORT
      LAYER M4 ;
        RECT  17.064 7.68 17.256 7.704 ;
    END
  END do0[100]
  PIN do0[101]
    DIRECTION OUTPUT ;
    USE SIGNAL ;
    PORT
      LAYER M4 ;
        RECT  17.064 7.728 17.256 7.752 ;
    END
  END do0[101]
  PIN do0[102]
    DIRECTION OUTPUT ;
    USE SIGNAL ;
    PORT
      LAYER M4 ;
        RECT  17.064 7.776 17.256 7.8 ;
    END
  END do0[102]
  PIN do0[103]
    DIRECTION OUTPUT ;
    USE SIGNAL ;
    PORT
      LAYER M4 ;
        RECT  17.064 7.824 17.256 7.848 ;
    END
  END do0[103]
  PIN do0[104]
    DIRECTION OUTPUT ;
    USE SIGNAL ;
    PORT
      LAYER M4 ;
        RECT  17.064 7.872 17.256 7.896 ;
    END
  END do0[104]
  PIN do0[105]
    DIRECTION OUTPUT ;
    USE SIGNAL ;
    PORT
      LAYER M4 ;
        RECT  17.064 7.92 17.256 7.944 ;
    END
  END do0[105]
  PIN do0[106]
    DIRECTION OUTPUT ;
    USE SIGNAL ;
    PORT
      LAYER M4 ;
        RECT  17.064 7.968 17.256 7.992 ;
    END
  END do0[106]
  PIN do0[107]
    DIRECTION OUTPUT ;
    USE SIGNAL ;
    PORT
      LAYER M4 ;
        RECT  17.064 8.016 17.256 8.04 ;
    END
  END do0[107]
  PIN do0[108]
    DIRECTION OUTPUT ;
    USE SIGNAL ;
    PORT
      LAYER M4 ;
        RECT  17.064 8.064 17.256 8.088 ;
    END
  END do0[108]
  PIN do0[109]
    DIRECTION OUTPUT ;
    USE SIGNAL ;
    PORT
      LAYER M4 ;
        RECT  17.064 8.112 17.256 8.136 ;
    END
  END do0[109]
  PIN do0[10]
    DIRECTION OUTPUT ;
    USE SIGNAL ;
    PORT
      LAYER M4 ;
        RECT  17.064 3.36 17.256 3.384 ;
    END
  END do0[10]
  PIN do0[110]
    DIRECTION OUTPUT ;
    USE SIGNAL ;
    PORT
      LAYER M4 ;
        RECT  17.064 8.16 17.256 8.184 ;
    END
  END do0[110]
  PIN do0[111]
    DIRECTION OUTPUT ;
    USE SIGNAL ;
    PORT
      LAYER M4 ;
        RECT  17.064 8.208 17.256 8.232 ;
    END
  END do0[111]
  PIN do0[112]
    DIRECTION OUTPUT ;
    USE SIGNAL ;
    PORT
      LAYER M4 ;
        RECT  17.064 8.256 17.256 8.28 ;
    END
  END do0[112]
  PIN do0[113]
    DIRECTION OUTPUT ;
    USE SIGNAL ;
    PORT
      LAYER M4 ;
        RECT  17.064 8.304 17.256 8.328 ;
    END
  END do0[113]
  PIN do0[114]
    DIRECTION OUTPUT ;
    USE SIGNAL ;
    PORT
      LAYER M4 ;
        RECT  17.064 8.352 17.256 8.376 ;
    END
  END do0[114]
  PIN do0[115]
    DIRECTION OUTPUT ;
    USE SIGNAL ;
    PORT
      LAYER M4 ;
        RECT  17.064 8.4 17.256 8.424 ;
    END
  END do0[115]
  PIN do0[116]
    DIRECTION OUTPUT ;
    USE SIGNAL ;
    PORT
      LAYER M4 ;
        RECT  17.064 8.448 17.256 8.472 ;
    END
  END do0[116]
  PIN do0[117]
    DIRECTION OUTPUT ;
    USE SIGNAL ;
    PORT
      LAYER M4 ;
        RECT  17.064 8.496 17.256 8.52 ;
    END
  END do0[117]
  PIN do0[118]
    DIRECTION OUTPUT ;
    USE SIGNAL ;
    PORT
      LAYER M4 ;
        RECT  17.064 8.544 17.256 8.568 ;
    END
  END do0[118]
  PIN do0[119]
    DIRECTION OUTPUT ;
    USE SIGNAL ;
    PORT
      LAYER M4 ;
        RECT  17.064 8.592 17.256 8.616 ;
    END
  END do0[119]
  PIN do0[11]
    DIRECTION OUTPUT ;
    USE SIGNAL ;
    PORT
      LAYER M4 ;
        RECT  17.064 3.408 17.256 3.432 ;
    END
  END do0[11]
  PIN do0[120]
    DIRECTION OUTPUT ;
    USE SIGNAL ;
    PORT
      LAYER M4 ;
        RECT  17.064 8.64 17.256 8.664 ;
    END
  END do0[120]
  PIN do0[121]
    DIRECTION OUTPUT ;
    USE SIGNAL ;
    PORT
      LAYER M4 ;
        RECT  17.064 8.688 17.256 8.712 ;
    END
  END do0[121]
  PIN do0[122]
    DIRECTION OUTPUT ;
    USE SIGNAL ;
    PORT
      LAYER M4 ;
        RECT  17.064 8.736 17.256 8.76 ;
    END
  END do0[122]
  PIN do0[123]
    DIRECTION OUTPUT ;
    USE SIGNAL ;
    PORT
      LAYER M4 ;
        RECT  17.064 8.784 17.256 8.808 ;
    END
  END do0[123]
  PIN do0[124]
    DIRECTION OUTPUT ;
    USE SIGNAL ;
    PORT
      LAYER M4 ;
        RECT  17.064 8.832 17.256 8.856 ;
    END
  END do0[124]
  PIN do0[125]
    DIRECTION OUTPUT ;
    USE SIGNAL ;
    PORT
      LAYER M4 ;
        RECT  17.064 8.88 17.256 8.904 ;
    END
  END do0[125]
  PIN do0[126]
    DIRECTION OUTPUT ;
    USE SIGNAL ;
    PORT
      LAYER M4 ;
        RECT  17.064 8.928 17.256 8.952 ;
    END
  END do0[126]
  PIN do0[127]
    DIRECTION OUTPUT ;
    USE SIGNAL ;
    PORT
      LAYER M4 ;
        RECT  17.064 8.976 17.256 9 ;
    END
  END do0[127]
  PIN do0[128]
    DIRECTION OUTPUT ;
    USE SIGNAL ;
    PORT
      LAYER M4 ;
        RECT  17.064 9.024 17.256 9.048 ;
    END
  END do0[128]
  PIN do0[129]
    DIRECTION OUTPUT ;
    USE SIGNAL ;
    PORT
      LAYER M4 ;
        RECT  17.064 9.072 17.256 9.096 ;
    END
  END do0[129]
  PIN do0[12]
    DIRECTION OUTPUT ;
    USE SIGNAL ;
    PORT
      LAYER M4 ;
        RECT  17.064 3.456 17.256 3.48 ;
    END
  END do0[12]
  PIN do0[130]
    DIRECTION OUTPUT ;
    USE SIGNAL ;
    PORT
      LAYER M4 ;
        RECT  17.064 9.12 17.256 9.144 ;
    END
  END do0[130]
  PIN do0[131]
    DIRECTION OUTPUT ;
    USE SIGNAL ;
    PORT
      LAYER M4 ;
        RECT  17.064 9.168 17.256 9.192 ;
    END
  END do0[131]
  PIN do0[132]
    DIRECTION OUTPUT ;
    USE SIGNAL ;
    PORT
      LAYER M4 ;
        RECT  17.064 9.216 17.256 9.24 ;
    END
  END do0[132]
  PIN do0[133]
    DIRECTION OUTPUT ;
    USE SIGNAL ;
    PORT
      LAYER M4 ;
        RECT  17.064 9.264 17.256 9.288 ;
    END
  END do0[133]
  PIN do0[134]
    DIRECTION OUTPUT ;
    USE SIGNAL ;
    PORT
      LAYER M4 ;
        RECT  17.064 9.312 17.256 9.336 ;
    END
  END do0[134]
  PIN do0[135]
    DIRECTION OUTPUT ;
    USE SIGNAL ;
    PORT
      LAYER M4 ;
        RECT  17.064 9.36 17.256 9.384 ;
    END
  END do0[135]
  PIN do0[136]
    DIRECTION OUTPUT ;
    USE SIGNAL ;
    PORT
      LAYER M4 ;
        RECT  17.064 9.408 17.256 9.432 ;
    END
  END do0[136]
  PIN do0[137]
    DIRECTION OUTPUT ;
    USE SIGNAL ;
    PORT
      LAYER M4 ;
        RECT  17.064 9.456 17.256 9.48 ;
    END
  END do0[137]
  PIN do0[138]
    DIRECTION OUTPUT ;
    USE SIGNAL ;
    PORT
      LAYER M4 ;
        RECT  17.064 9.504 17.256 9.528 ;
    END
  END do0[138]
  PIN do0[139]
    DIRECTION OUTPUT ;
    USE SIGNAL ;
    PORT
      LAYER M4 ;
        RECT  17.064 9.552 17.256 9.576 ;
    END
  END do0[139]
  PIN do0[13]
    DIRECTION OUTPUT ;
    USE SIGNAL ;
    PORT
      LAYER M4 ;
        RECT  17.064 3.504 17.256 3.528 ;
    END
  END do0[13]
  PIN do0[140]
    DIRECTION OUTPUT ;
    USE SIGNAL ;
    PORT
      LAYER M4 ;
        RECT  17.064 9.6 17.256 9.624 ;
    END
  END do0[140]
  PIN do0[141]
    DIRECTION OUTPUT ;
    USE SIGNAL ;
    PORT
      LAYER M4 ;
        RECT  17.064 9.648 17.256 9.672 ;
    END
  END do0[141]
  PIN do0[142]
    DIRECTION OUTPUT ;
    USE SIGNAL ;
    PORT
      LAYER M4 ;
        RECT  17.064 9.696 17.256 9.72 ;
    END
  END do0[142]
  PIN do0[143]
    DIRECTION OUTPUT ;
    USE SIGNAL ;
    PORT
      LAYER M4 ;
        RECT  17.064 9.744 17.256 9.768 ;
    END
  END do0[143]
  PIN do0[144]
    DIRECTION OUTPUT ;
    USE SIGNAL ;
    PORT
      LAYER M4 ;
        RECT  17.064 9.792 17.256 9.816 ;
    END
  END do0[144]
  PIN do0[145]
    DIRECTION OUTPUT ;
    USE SIGNAL ;
    PORT
      LAYER M4 ;
        RECT  17.064 9.84 17.256 9.864 ;
    END
  END do0[145]
  PIN do0[146]
    DIRECTION OUTPUT ;
    USE SIGNAL ;
    PORT
      LAYER M4 ;
        RECT  17.064 9.888 17.256 9.912 ;
    END
  END do0[146]
  PIN do0[147]
    DIRECTION OUTPUT ;
    USE SIGNAL ;
    PORT
      LAYER M4 ;
        RECT  17.064 9.936 17.256 9.96 ;
    END
  END do0[147]
  PIN do0[148]
    DIRECTION OUTPUT ;
    USE SIGNAL ;
    PORT
      LAYER M4 ;
        RECT  17.064 9.984 17.256 10.008 ;
    END
  END do0[148]
  PIN do0[149]
    DIRECTION OUTPUT ;
    USE SIGNAL ;
    PORT
      LAYER M4 ;
        RECT  17.064 10.032 17.256 10.056 ;
    END
  END do0[149]
  PIN do0[14]
    DIRECTION OUTPUT ;
    USE SIGNAL ;
    PORT
      LAYER M4 ;
        RECT  17.064 3.552 17.256 3.576 ;
    END
  END do0[14]
  PIN do0[150]
    DIRECTION OUTPUT ;
    USE SIGNAL ;
    PORT
      LAYER M4 ;
        RECT  17.064 10.08 17.256 10.104 ;
    END
  END do0[150]
  PIN do0[151]
    DIRECTION OUTPUT ;
    USE SIGNAL ;
    PORT
      LAYER M4 ;
        RECT  17.064 10.128 17.256 10.152 ;
    END
  END do0[151]
  PIN do0[152]
    DIRECTION OUTPUT ;
    USE SIGNAL ;
    PORT
      LAYER M4 ;
        RECT  17.064 10.176 17.256 10.2 ;
    END
  END do0[152]
  PIN do0[153]
    DIRECTION OUTPUT ;
    USE SIGNAL ;
    PORT
      LAYER M4 ;
        RECT  17.064 10.224 17.256 10.248 ;
    END
  END do0[153]
  PIN do0[154]
    DIRECTION OUTPUT ;
    USE SIGNAL ;
    PORT
      LAYER M4 ;
        RECT  17.064 10.272 17.256 10.296 ;
    END
  END do0[154]
  PIN do0[155]
    DIRECTION OUTPUT ;
    USE SIGNAL ;
    PORT
      LAYER M4 ;
        RECT  17.064 10.32 17.256 10.344 ;
    END
  END do0[155]
  PIN do0[156]
    DIRECTION OUTPUT ;
    USE SIGNAL ;
    PORT
      LAYER M4 ;
        RECT  17.064 10.368 17.256 10.392 ;
    END
  END do0[156]
  PIN do0[157]
    DIRECTION OUTPUT ;
    USE SIGNAL ;
    PORT
      LAYER M4 ;
        RECT  17.064 10.416 17.256 10.44 ;
    END
  END do0[157]
  PIN do0[158]
    DIRECTION OUTPUT ;
    USE SIGNAL ;
    PORT
      LAYER M4 ;
        RECT  17.064 10.464 17.256 10.488 ;
    END
  END do0[158]
  PIN do0[159]
    DIRECTION OUTPUT ;
    USE SIGNAL ;
    PORT
      LAYER M4 ;
        RECT  17.064 10.512 17.256 10.536 ;
    END
  END do0[159]
  PIN do0[15]
    DIRECTION OUTPUT ;
    USE SIGNAL ;
    PORT
      LAYER M4 ;
        RECT  17.064 3.6 17.256 3.624 ;
    END
  END do0[15]
  PIN do0[160]
    DIRECTION OUTPUT ;
    USE SIGNAL ;
    PORT
      LAYER M4 ;
        RECT  17.064 10.56 17.256 10.584 ;
    END
  END do0[160]
  PIN do0[161]
    DIRECTION OUTPUT ;
    USE SIGNAL ;
    PORT
      LAYER M4 ;
        RECT  17.064 10.608 17.256 10.632 ;
    END
  END do0[161]
  PIN do0[162]
    DIRECTION OUTPUT ;
    USE SIGNAL ;
    PORT
      LAYER M4 ;
        RECT  17.064 10.656 17.256 10.68 ;
    END
  END do0[162]
  PIN do0[163]
    DIRECTION OUTPUT ;
    USE SIGNAL ;
    PORT
      LAYER M4 ;
        RECT  17.064 10.704 17.256 10.728 ;
    END
  END do0[163]
  PIN do0[164]
    DIRECTION OUTPUT ;
    USE SIGNAL ;
    PORT
      LAYER M4 ;
        RECT  17.064 10.752 17.256 10.776 ;
    END
  END do0[164]
  PIN do0[165]
    DIRECTION OUTPUT ;
    USE SIGNAL ;
    PORT
      LAYER M4 ;
        RECT  17.064 10.8 17.256 10.824 ;
    END
  END do0[165]
  PIN do0[166]
    DIRECTION OUTPUT ;
    USE SIGNAL ;
    PORT
      LAYER M4 ;
        RECT  17.064 10.848 17.256 10.872 ;
    END
  END do0[166]
  PIN do0[167]
    DIRECTION OUTPUT ;
    USE SIGNAL ;
    PORT
      LAYER M4 ;
        RECT  17.064 10.896 17.256 10.92 ;
    END
  END do0[167]
  PIN do0[168]
    DIRECTION OUTPUT ;
    USE SIGNAL ;
    PORT
      LAYER M4 ;
        RECT  17.064 10.944 17.256 10.968 ;
    END
  END do0[168]
  PIN do0[169]
    DIRECTION OUTPUT ;
    USE SIGNAL ;
    PORT
      LAYER M4 ;
        RECT  17.064 10.992 17.256 11.016 ;
    END
  END do0[169]
  PIN do0[16]
    DIRECTION OUTPUT ;
    USE SIGNAL ;
    PORT
      LAYER M4 ;
        RECT  17.064 3.648 17.256 3.672 ;
    END
  END do0[16]
  PIN do0[170]
    DIRECTION OUTPUT ;
    USE SIGNAL ;
    PORT
      LAYER M4 ;
        RECT  17.064 11.04 17.256 11.064 ;
    END
  END do0[170]
  PIN do0[171]
    DIRECTION OUTPUT ;
    USE SIGNAL ;
    PORT
      LAYER M4 ;
        RECT  17.064 11.088 17.256 11.112 ;
    END
  END do0[171]
  PIN do0[172]
    DIRECTION OUTPUT ;
    USE SIGNAL ;
    PORT
      LAYER M4 ;
        RECT  17.064 11.136 17.256 11.16 ;
    END
  END do0[172]
  PIN do0[173]
    DIRECTION OUTPUT ;
    USE SIGNAL ;
    PORT
      LAYER M4 ;
        RECT  17.064 11.184 17.256 11.208 ;
    END
  END do0[173]
  PIN do0[174]
    DIRECTION OUTPUT ;
    USE SIGNAL ;
    PORT
      LAYER M4 ;
        RECT  17.064 11.232 17.256 11.256 ;
    END
  END do0[174]
  PIN do0[175]
    DIRECTION OUTPUT ;
    USE SIGNAL ;
    PORT
      LAYER M4 ;
        RECT  17.064 11.28 17.256 11.304 ;
    END
  END do0[175]
  PIN do0[176]
    DIRECTION OUTPUT ;
    USE SIGNAL ;
    PORT
      LAYER M4 ;
        RECT  17.064 11.328 17.256 11.352 ;
    END
  END do0[176]
  PIN do0[177]
    DIRECTION OUTPUT ;
    USE SIGNAL ;
    PORT
      LAYER M4 ;
        RECT  17.064 11.376 17.256 11.4 ;
    END
  END do0[177]
  PIN do0[178]
    DIRECTION OUTPUT ;
    USE SIGNAL ;
    PORT
      LAYER M4 ;
        RECT  17.064 11.424 17.256 11.448 ;
    END
  END do0[178]
  PIN do0[179]
    DIRECTION OUTPUT ;
    USE SIGNAL ;
    PORT
      LAYER M4 ;
        RECT  17.064 11.472 17.256 11.496 ;
    END
  END do0[179]
  PIN do0[17]
    DIRECTION OUTPUT ;
    USE SIGNAL ;
    PORT
      LAYER M4 ;
        RECT  17.064 3.696 17.256 3.72 ;
    END
  END do0[17]
  PIN do0[180]
    DIRECTION OUTPUT ;
    USE SIGNAL ;
    PORT
      LAYER M4 ;
        RECT  17.064 11.52 17.256 11.544 ;
    END
  END do0[180]
  PIN do0[181]
    DIRECTION OUTPUT ;
    USE SIGNAL ;
    PORT
      LAYER M4 ;
        RECT  17.064 11.568 17.256 11.592 ;
    END
  END do0[181]
  PIN do0[182]
    DIRECTION OUTPUT ;
    USE SIGNAL ;
    PORT
      LAYER M4 ;
        RECT  17.064 11.616 17.256 11.64 ;
    END
  END do0[182]
  PIN do0[183]
    DIRECTION OUTPUT ;
    USE SIGNAL ;
    PORT
      LAYER M4 ;
        RECT  17.064 11.664 17.256 11.688 ;
    END
  END do0[183]
  PIN do0[184]
    DIRECTION OUTPUT ;
    USE SIGNAL ;
    PORT
      LAYER M4 ;
        RECT  17.064 11.712 17.256 11.736 ;
    END
  END do0[184]
  PIN do0[185]
    DIRECTION OUTPUT ;
    USE SIGNAL ;
    PORT
      LAYER M4 ;
        RECT  17.064 11.76 17.256 11.784 ;
    END
  END do0[185]
  PIN do0[186]
    DIRECTION OUTPUT ;
    USE SIGNAL ;
    PORT
      LAYER M4 ;
        RECT  17.064 11.808 17.256 11.832 ;
    END
  END do0[186]
  PIN do0[187]
    DIRECTION OUTPUT ;
    USE SIGNAL ;
    PORT
      LAYER M4 ;
        RECT  17.064 11.856 17.256 11.88 ;
    END
  END do0[187]
  PIN do0[188]
    DIRECTION OUTPUT ;
    USE SIGNAL ;
    PORT
      LAYER M4 ;
        RECT  17.064 11.904 17.256 11.928 ;
    END
  END do0[188]
  PIN do0[189]
    DIRECTION OUTPUT ;
    USE SIGNAL ;
    PORT
      LAYER M4 ;
        RECT  17.064 11.952 17.256 11.976 ;
    END
  END do0[189]
  PIN do0[18]
    DIRECTION OUTPUT ;
    USE SIGNAL ;
    PORT
      LAYER M4 ;
        RECT  17.064 3.744 17.256 3.768 ;
    END
  END do0[18]
  PIN do0[190]
    DIRECTION OUTPUT ;
    USE SIGNAL ;
    PORT
      LAYER M4 ;
        RECT  17.064 12 17.256 12.024 ;
    END
  END do0[190]
  PIN do0[191]
    DIRECTION OUTPUT ;
    USE SIGNAL ;
    PORT
      LAYER M4 ;
        RECT  17.064 12.048 17.256 12.072 ;
    END
  END do0[191]
  PIN do0[192]
    DIRECTION OUTPUT ;
    USE SIGNAL ;
    PORT
      LAYER M4 ;
        RECT  17.064 12.096 17.256 12.12 ;
    END
  END do0[192]
  PIN do0[193]
    DIRECTION OUTPUT ;
    USE SIGNAL ;
    PORT
      LAYER M4 ;
        RECT  17.064 12.144 17.256 12.168 ;
    END
  END do0[193]
  PIN do0[194]
    DIRECTION OUTPUT ;
    USE SIGNAL ;
    PORT
      LAYER M4 ;
        RECT  17.064 12.192 17.256 12.216 ;
    END
  END do0[194]
  PIN do0[195]
    DIRECTION OUTPUT ;
    USE SIGNAL ;
    PORT
      LAYER M4 ;
        RECT  17.064 12.24 17.256 12.264 ;
    END
  END do0[195]
  PIN do0[196]
    DIRECTION OUTPUT ;
    USE SIGNAL ;
    PORT
      LAYER M4 ;
        RECT  17.064 12.288 17.256 12.312 ;
    END
  END do0[196]
  PIN do0[197]
    DIRECTION OUTPUT ;
    USE SIGNAL ;
    PORT
      LAYER M4 ;
        RECT  17.064 12.336 17.256 12.36 ;
    END
  END do0[197]
  PIN do0[198]
    DIRECTION OUTPUT ;
    USE SIGNAL ;
    PORT
      LAYER M4 ;
        RECT  17.064 12.384 17.256 12.408 ;
    END
  END do0[198]
  PIN do0[199]
    DIRECTION OUTPUT ;
    USE SIGNAL ;
    PORT
      LAYER M4 ;
        RECT  17.064 12.432 17.256 12.456 ;
    END
  END do0[199]
  PIN do0[19]
    DIRECTION OUTPUT ;
    USE SIGNAL ;
    PORT
      LAYER M4 ;
        RECT  17.064 3.792 17.256 3.816 ;
    END
  END do0[19]
  PIN do0[1]
    DIRECTION OUTPUT ;
    USE SIGNAL ;
    PORT
      LAYER M4 ;
        RECT  17.064 2.928 17.256 2.952 ;
    END
  END do0[1]
  PIN do0[200]
    DIRECTION OUTPUT ;
    USE SIGNAL ;
    PORT
      LAYER M4 ;
        RECT  17.064 12.48 17.256 12.504 ;
    END
  END do0[200]
  PIN do0[201]
    DIRECTION OUTPUT ;
    USE SIGNAL ;
    PORT
      LAYER M4 ;
        RECT  17.064 12.528 17.256 12.552 ;
    END
  END do0[201]
  PIN do0[202]
    DIRECTION OUTPUT ;
    USE SIGNAL ;
    PORT
      LAYER M4 ;
        RECT  17.064 12.576 17.256 12.6 ;
    END
  END do0[202]
  PIN do0[203]
    DIRECTION OUTPUT ;
    USE SIGNAL ;
    PORT
      LAYER M4 ;
        RECT  17.064 12.624 17.256 12.648 ;
    END
  END do0[203]
  PIN do0[204]
    DIRECTION OUTPUT ;
    USE SIGNAL ;
    PORT
      LAYER M4 ;
        RECT  17.064 12.672 17.256 12.696 ;
    END
  END do0[204]
  PIN do0[205]
    DIRECTION OUTPUT ;
    USE SIGNAL ;
    PORT
      LAYER M4 ;
        RECT  17.064 12.72 17.256 12.744 ;
    END
  END do0[205]
  PIN do0[206]
    DIRECTION OUTPUT ;
    USE SIGNAL ;
    PORT
      LAYER M4 ;
        RECT  17.064 12.768 17.256 12.792 ;
    END
  END do0[206]
  PIN do0[207]
    DIRECTION OUTPUT ;
    USE SIGNAL ;
    PORT
      LAYER M4 ;
        RECT  17.064 12.816 17.256 12.84 ;
    END
  END do0[207]
  PIN do0[208]
    DIRECTION OUTPUT ;
    USE SIGNAL ;
    PORT
      LAYER M4 ;
        RECT  17.064 12.864 17.256 12.888 ;
    END
  END do0[208]
  PIN do0[209]
    DIRECTION OUTPUT ;
    USE SIGNAL ;
    PORT
      LAYER M4 ;
        RECT  17.064 12.912 17.256 12.936 ;
    END
  END do0[209]
  PIN do0[20]
    DIRECTION OUTPUT ;
    USE SIGNAL ;
    PORT
      LAYER M4 ;
        RECT  17.064 3.84 17.256 3.864 ;
    END
  END do0[20]
  PIN do0[210]
    DIRECTION OUTPUT ;
    USE SIGNAL ;
    PORT
      LAYER M4 ;
        RECT  17.064 12.96 17.256 12.984 ;
    END
  END do0[210]
  PIN do0[211]
    DIRECTION OUTPUT ;
    USE SIGNAL ;
    PORT
      LAYER M4 ;
        RECT  17.064 13.008 17.256 13.032 ;
    END
  END do0[211]
  PIN do0[212]
    DIRECTION OUTPUT ;
    USE SIGNAL ;
    PORT
      LAYER M4 ;
        RECT  17.064 13.056 17.256 13.08 ;
    END
  END do0[212]
  PIN do0[213]
    DIRECTION OUTPUT ;
    USE SIGNAL ;
    PORT
      LAYER M4 ;
        RECT  17.064 13.104 17.256 13.128 ;
    END
  END do0[213]
  PIN do0[214]
    DIRECTION OUTPUT ;
    USE SIGNAL ;
    PORT
      LAYER M4 ;
        RECT  17.064 13.152 17.256 13.176 ;
    END
  END do0[214]
  PIN do0[215]
    DIRECTION OUTPUT ;
    USE SIGNAL ;
    PORT
      LAYER M4 ;
        RECT  17.064 13.2 17.256 13.224 ;
    END
  END do0[215]
  PIN do0[216]
    DIRECTION OUTPUT ;
    USE SIGNAL ;
    PORT
      LAYER M4 ;
        RECT  17.064 13.248 17.256 13.272 ;
    END
  END do0[216]
  PIN do0[217]
    DIRECTION OUTPUT ;
    USE SIGNAL ;
    PORT
      LAYER M4 ;
        RECT  17.064 13.296 17.256 13.32 ;
    END
  END do0[217]
  PIN do0[218]
    DIRECTION OUTPUT ;
    USE SIGNAL ;
    PORT
      LAYER M4 ;
        RECT  17.064 13.344 17.256 13.368 ;
    END
  END do0[218]
  PIN do0[219]
    DIRECTION OUTPUT ;
    USE SIGNAL ;
    PORT
      LAYER M4 ;
        RECT  17.064 13.392 17.256 13.416 ;
    END
  END do0[219]
  PIN do0[21]
    DIRECTION OUTPUT ;
    USE SIGNAL ;
    PORT
      LAYER M4 ;
        RECT  17.064 3.888 17.256 3.912 ;
    END
  END do0[21]
  PIN do0[220]
    DIRECTION OUTPUT ;
    USE SIGNAL ;
    PORT
      LAYER M4 ;
        RECT  17.064 13.44 17.256 13.464 ;
    END
  END do0[220]
  PIN do0[221]
    DIRECTION OUTPUT ;
    USE SIGNAL ;
    PORT
      LAYER M4 ;
        RECT  17.064 13.488 17.256 13.512 ;
    END
  END do0[221]
  PIN do0[222]
    DIRECTION OUTPUT ;
    USE SIGNAL ;
    PORT
      LAYER M4 ;
        RECT  17.064 13.536 17.256 13.56 ;
    END
  END do0[222]
  PIN do0[223]
    DIRECTION OUTPUT ;
    USE SIGNAL ;
    PORT
      LAYER M4 ;
        RECT  17.064 13.584 17.256 13.608 ;
    END
  END do0[223]
  PIN do0[224]
    DIRECTION OUTPUT ;
    USE SIGNAL ;
    PORT
      LAYER M4 ;
        RECT  17.064 13.632 17.256 13.656 ;
    END
  END do0[224]
  PIN do0[225]
    DIRECTION OUTPUT ;
    USE SIGNAL ;
    PORT
      LAYER M4 ;
        RECT  17.064 13.68 17.256 13.704 ;
    END
  END do0[225]
  PIN do0[226]
    DIRECTION OUTPUT ;
    USE SIGNAL ;
    PORT
      LAYER M4 ;
        RECT  17.064 13.728 17.256 13.752 ;
    END
  END do0[226]
  PIN do0[227]
    DIRECTION OUTPUT ;
    USE SIGNAL ;
    PORT
      LAYER M4 ;
        RECT  17.064 13.776 17.256 13.8 ;
    END
  END do0[227]
  PIN do0[228]
    DIRECTION OUTPUT ;
    USE SIGNAL ;
    PORT
      LAYER M4 ;
        RECT  17.064 13.824 17.256 13.848 ;
    END
  END do0[228]
  PIN do0[229]
    DIRECTION OUTPUT ;
    USE SIGNAL ;
    PORT
      LAYER M4 ;
        RECT  17.064 13.872 17.256 13.896 ;
    END
  END do0[229]
  PIN do0[22]
    DIRECTION OUTPUT ;
    USE SIGNAL ;
    PORT
      LAYER M4 ;
        RECT  17.064 3.936 17.256 3.96 ;
    END
  END do0[22]
  PIN do0[230]
    DIRECTION OUTPUT ;
    USE SIGNAL ;
    PORT
      LAYER M4 ;
        RECT  17.064 13.92 17.256 13.944 ;
    END
  END do0[230]
  PIN do0[231]
    DIRECTION OUTPUT ;
    USE SIGNAL ;
    PORT
      LAYER M4 ;
        RECT  17.064 13.968 17.256 13.992 ;
    END
  END do0[231]
  PIN do0[232]
    DIRECTION OUTPUT ;
    USE SIGNAL ;
    PORT
      LAYER M4 ;
        RECT  17.064 14.016 17.256 14.04 ;
    END
  END do0[232]
  PIN do0[233]
    DIRECTION OUTPUT ;
    USE SIGNAL ;
    PORT
      LAYER M4 ;
        RECT  17.064 14.064 17.256 14.088 ;
    END
  END do0[233]
  PIN do0[234]
    DIRECTION OUTPUT ;
    USE SIGNAL ;
    PORT
      LAYER M4 ;
        RECT  17.064 14.112 17.256 14.136 ;
    END
  END do0[234]
  PIN do0[235]
    DIRECTION OUTPUT ;
    USE SIGNAL ;
    PORT
      LAYER M4 ;
        RECT  17.064 14.16 17.256 14.184 ;
    END
  END do0[235]
  PIN do0[236]
    DIRECTION OUTPUT ;
    USE SIGNAL ;
    PORT
      LAYER M4 ;
        RECT  17.064 14.208 17.256 14.232 ;
    END
  END do0[236]
  PIN do0[237]
    DIRECTION OUTPUT ;
    USE SIGNAL ;
    PORT
      LAYER M4 ;
        RECT  17.064 14.256 17.256 14.28 ;
    END
  END do0[237]
  PIN do0[238]
    DIRECTION OUTPUT ;
    USE SIGNAL ;
    PORT
      LAYER M4 ;
        RECT  17.064 14.304 17.256 14.328 ;
    END
  END do0[238]
  PIN do0[239]
    DIRECTION OUTPUT ;
    USE SIGNAL ;
    PORT
      LAYER M4 ;
        RECT  17.064 14.352 17.256 14.376 ;
    END
  END do0[239]
  PIN do0[23]
    DIRECTION OUTPUT ;
    USE SIGNAL ;
    PORT
      LAYER M4 ;
        RECT  17.064 3.984 17.256 4.008 ;
    END
  END do0[23]
  PIN do0[240]
    DIRECTION OUTPUT ;
    USE SIGNAL ;
    PORT
      LAYER M4 ;
        RECT  17.064 14.4 17.256 14.424 ;
    END
  END do0[240]
  PIN do0[241]
    DIRECTION OUTPUT ;
    USE SIGNAL ;
    PORT
      LAYER M4 ;
        RECT  17.064 14.448 17.256 14.472 ;
    END
  END do0[241]
  PIN do0[242]
    DIRECTION OUTPUT ;
    USE SIGNAL ;
    PORT
      LAYER M4 ;
        RECT  17.064 14.496 17.256 14.52 ;
    END
  END do0[242]
  PIN do0[243]
    DIRECTION OUTPUT ;
    USE SIGNAL ;
    PORT
      LAYER M4 ;
        RECT  17.064 14.544 17.256 14.568 ;
    END
  END do0[243]
  PIN do0[244]
    DIRECTION OUTPUT ;
    USE SIGNAL ;
    PORT
      LAYER M4 ;
        RECT  17.064 14.592 17.256 14.616 ;
    END
  END do0[244]
  PIN do0[245]
    DIRECTION OUTPUT ;
    USE SIGNAL ;
    PORT
      LAYER M4 ;
        RECT  17.064 14.64 17.256 14.664 ;
    END
  END do0[245]
  PIN do0[246]
    DIRECTION OUTPUT ;
    USE SIGNAL ;
    PORT
      LAYER M4 ;
        RECT  17.064 14.688 17.256 14.712 ;
    END
  END do0[246]
  PIN do0[247]
    DIRECTION OUTPUT ;
    USE SIGNAL ;
    PORT
      LAYER M4 ;
        RECT  17.064 14.736 17.256 14.76 ;
    END
  END do0[247]
  PIN do0[248]
    DIRECTION OUTPUT ;
    USE SIGNAL ;
    PORT
      LAYER M4 ;
        RECT  17.064 14.784 17.256 14.808 ;
    END
  END do0[248]
  PIN do0[249]
    DIRECTION OUTPUT ;
    USE SIGNAL ;
    PORT
      LAYER M4 ;
        RECT  17.064 14.832 17.256 14.856 ;
    END
  END do0[249]
  PIN do0[24]
    DIRECTION OUTPUT ;
    USE SIGNAL ;
    PORT
      LAYER M4 ;
        RECT  17.064 4.032 17.256 4.056 ;
    END
  END do0[24]
  PIN do0[250]
    DIRECTION OUTPUT ;
    USE SIGNAL ;
    PORT
      LAYER M4 ;
        RECT  17.064 14.88 17.256 14.904 ;
    END
  END do0[250]
  PIN do0[251]
    DIRECTION OUTPUT ;
    USE SIGNAL ;
    PORT
      LAYER M4 ;
        RECT  17.064 14.928 17.256 14.952 ;
    END
  END do0[251]
  PIN do0[252]
    DIRECTION OUTPUT ;
    USE SIGNAL ;
    PORT
      LAYER M4 ;
        RECT  17.064 14.976 17.256 15 ;
    END
  END do0[252]
  PIN do0[253]
    DIRECTION OUTPUT ;
    USE SIGNAL ;
    PORT
      LAYER M4 ;
        RECT  17.064 15.024 17.256 15.048 ;
    END
  END do0[253]
  PIN do0[254]
    DIRECTION OUTPUT ;
    USE SIGNAL ;
    PORT
      LAYER M4 ;
        RECT  17.064 15.072 17.256 15.096 ;
    END
  END do0[254]
  PIN do0[255]
    DIRECTION OUTPUT ;
    USE SIGNAL ;
    PORT
      LAYER M4 ;
        RECT  17.064 15.12 17.256 15.144 ;
    END
  END do0[255]
  PIN do0[256]
    DIRECTION OUTPUT ;
    USE SIGNAL ;
    PORT
      LAYER M4 ;
        RECT  17.064 15.168 17.256 15.192 ;
    END
  END do0[256]
  PIN do0[257]
    DIRECTION OUTPUT ;
    USE SIGNAL ;
    PORT
      LAYER M4 ;
        RECT  17.064 15.216 17.256 15.24 ;
    END
  END do0[257]
  PIN do0[258]
    DIRECTION OUTPUT ;
    USE SIGNAL ;
    PORT
      LAYER M4 ;
        RECT  17.064 15.264 17.256 15.288 ;
    END
  END do0[258]
  PIN do0[259]
    DIRECTION OUTPUT ;
    USE SIGNAL ;
    PORT
      LAYER M4 ;
        RECT  17.064 15.312 17.256 15.336 ;
    END
  END do0[259]
  PIN do0[25]
    DIRECTION OUTPUT ;
    USE SIGNAL ;
    PORT
      LAYER M4 ;
        RECT  17.064 4.08 17.256 4.104 ;
    END
  END do0[25]
  PIN do0[260]
    DIRECTION OUTPUT ;
    USE SIGNAL ;
    PORT
      LAYER M4 ;
        RECT  17.064 15.36 17.256 15.384 ;
    END
  END do0[260]
  PIN do0[261]
    DIRECTION OUTPUT ;
    USE SIGNAL ;
    PORT
      LAYER M4 ;
        RECT  17.064 15.408 17.256 15.432 ;
    END
  END do0[261]
  PIN do0[262]
    DIRECTION OUTPUT ;
    USE SIGNAL ;
    PORT
      LAYER M4 ;
        RECT  17.064 15.456 17.256 15.48 ;
    END
  END do0[262]
  PIN do0[263]
    DIRECTION OUTPUT ;
    USE SIGNAL ;
    PORT
      LAYER M4 ;
        RECT  17.064 15.504 17.256 15.528 ;
    END
  END do0[263]
  PIN do0[264]
    DIRECTION OUTPUT ;
    USE SIGNAL ;
    PORT
      LAYER M4 ;
        RECT  17.064 15.552 17.256 15.576 ;
    END
  END do0[264]
  PIN do0[265]
    DIRECTION OUTPUT ;
    USE SIGNAL ;
    PORT
      LAYER M4 ;
        RECT  17.064 15.6 17.256 15.624 ;
    END
  END do0[265]
  PIN do0[266]
    DIRECTION OUTPUT ;
    USE SIGNAL ;
    PORT
      LAYER M4 ;
        RECT  17.064 15.648 17.256 15.672 ;
    END
  END do0[266]
  PIN do0[267]
    DIRECTION OUTPUT ;
    USE SIGNAL ;
    PORT
      LAYER M4 ;
        RECT  17.064 15.696 17.256 15.72 ;
    END
  END do0[267]
  PIN do0[268]
    DIRECTION OUTPUT ;
    USE SIGNAL ;
    PORT
      LAYER M4 ;
        RECT  17.064 15.744 17.256 15.768 ;
    END
  END do0[268]
  PIN do0[269]
    DIRECTION OUTPUT ;
    USE SIGNAL ;
    PORT
      LAYER M4 ;
        RECT  17.064 15.792 17.256 15.816 ;
    END
  END do0[269]
  PIN do0[26]
    DIRECTION OUTPUT ;
    USE SIGNAL ;
    PORT
      LAYER M4 ;
        RECT  17.064 4.128 17.256 4.152 ;
    END
  END do0[26]
  PIN do0[270]
    DIRECTION OUTPUT ;
    USE SIGNAL ;
    PORT
      LAYER M4 ;
        RECT  17.064 15.84 17.256 15.864 ;
    END
  END do0[270]
  PIN do0[271]
    DIRECTION OUTPUT ;
    USE SIGNAL ;
    PORT
      LAYER M4 ;
        RECT  17.064 15.888 17.256 15.912 ;
    END
  END do0[271]
  PIN do0[272]
    DIRECTION OUTPUT ;
    USE SIGNAL ;
    PORT
      LAYER M4 ;
        RECT  17.064 15.936 17.256 15.96 ;
    END
  END do0[272]
  PIN do0[273]
    DIRECTION OUTPUT ;
    USE SIGNAL ;
    PORT
      LAYER M4 ;
        RECT  17.064 15.984 17.256 16.008 ;
    END
  END do0[273]
  PIN do0[274]
    DIRECTION OUTPUT ;
    USE SIGNAL ;
    PORT
      LAYER M4 ;
        RECT  17.064 16.032 17.256 16.056 ;
    END
  END do0[274]
  PIN do0[275]
    DIRECTION OUTPUT ;
    USE SIGNAL ;
    PORT
      LAYER M4 ;
        RECT  17.064 16.08 17.256 16.104 ;
    END
  END do0[275]
  PIN do0[276]
    DIRECTION OUTPUT ;
    USE SIGNAL ;
    PORT
      LAYER M4 ;
        RECT  17.064 16.128 17.256 16.152 ;
    END
  END do0[276]
  PIN do0[277]
    DIRECTION OUTPUT ;
    USE SIGNAL ;
    PORT
      LAYER M4 ;
        RECT  17.064 16.176 17.256 16.2 ;
    END
  END do0[277]
  PIN do0[278]
    DIRECTION OUTPUT ;
    USE SIGNAL ;
    PORT
      LAYER M4 ;
        RECT  17.064 16.224 17.256 16.248 ;
    END
  END do0[278]
  PIN do0[279]
    DIRECTION OUTPUT ;
    USE SIGNAL ;
    PORT
      LAYER M4 ;
        RECT  17.064 16.272 17.256 16.296 ;
    END
  END do0[279]
  PIN do0[27]
    DIRECTION OUTPUT ;
    USE SIGNAL ;
    PORT
      LAYER M4 ;
        RECT  17.064 4.176 17.256 4.2 ;
    END
  END do0[27]
  PIN do0[280]
    DIRECTION OUTPUT ;
    USE SIGNAL ;
    PORT
      LAYER M4 ;
        RECT  17.064 16.32 17.256 16.344 ;
    END
  END do0[280]
  PIN do0[281]
    DIRECTION OUTPUT ;
    USE SIGNAL ;
    PORT
      LAYER M4 ;
        RECT  17.064 16.368 17.256 16.392 ;
    END
  END do0[281]
  PIN do0[282]
    DIRECTION OUTPUT ;
    USE SIGNAL ;
    PORT
      LAYER M4 ;
        RECT  17.064 16.416 17.256 16.44 ;
    END
  END do0[282]
  PIN do0[283]
    DIRECTION OUTPUT ;
    USE SIGNAL ;
    PORT
      LAYER M4 ;
        RECT  17.064 16.464 17.256 16.488 ;
    END
  END do0[283]
  PIN do0[284]
    DIRECTION OUTPUT ;
    USE SIGNAL ;
    PORT
      LAYER M4 ;
        RECT  17.064 16.512 17.256 16.536 ;
    END
  END do0[284]
  PIN do0[285]
    DIRECTION OUTPUT ;
    USE SIGNAL ;
    PORT
      LAYER M4 ;
        RECT  17.064 16.56 17.256 16.584 ;
    END
  END do0[285]
  PIN do0[286]
    DIRECTION OUTPUT ;
    USE SIGNAL ;
    PORT
      LAYER M4 ;
        RECT  17.064 16.608 17.256 16.632 ;
    END
  END do0[286]
  PIN do0[287]
    DIRECTION OUTPUT ;
    USE SIGNAL ;
    PORT
      LAYER M4 ;
        RECT  17.064 16.656 17.256 16.68 ;
    END
  END do0[287]
  PIN do0[288]
    DIRECTION OUTPUT ;
    USE SIGNAL ;
    PORT
      LAYER M4 ;
        RECT  17.064 16.704 17.256 16.728 ;
    END
  END do0[288]
  PIN do0[289]
    DIRECTION OUTPUT ;
    USE SIGNAL ;
    PORT
      LAYER M4 ;
        RECT  17.064 16.752 17.256 16.776 ;
    END
  END do0[289]
  PIN do0[28]
    DIRECTION OUTPUT ;
    USE SIGNAL ;
    PORT
      LAYER M4 ;
        RECT  17.064 4.224 17.256 4.248 ;
    END
  END do0[28]
  PIN do0[290]
    DIRECTION OUTPUT ;
    USE SIGNAL ;
    PORT
      LAYER M4 ;
        RECT  17.064 16.8 17.256 16.824 ;
    END
  END do0[290]
  PIN do0[291]
    DIRECTION OUTPUT ;
    USE SIGNAL ;
    PORT
      LAYER M4 ;
        RECT  17.064 16.848 17.256 16.872 ;
    END
  END do0[291]
  PIN do0[292]
    DIRECTION OUTPUT ;
    USE SIGNAL ;
    PORT
      LAYER M4 ;
        RECT  17.064 16.896 17.256 16.92 ;
    END
  END do0[292]
  PIN do0[293]
    DIRECTION OUTPUT ;
    USE SIGNAL ;
    PORT
      LAYER M4 ;
        RECT  17.064 16.944 17.256 16.968 ;
    END
  END do0[293]
  PIN do0[294]
    DIRECTION OUTPUT ;
    USE SIGNAL ;
    PORT
      LAYER M4 ;
        RECT  17.064 16.992 17.256 17.016 ;
    END
  END do0[294]
  PIN do0[295]
    DIRECTION OUTPUT ;
    USE SIGNAL ;
    PORT
      LAYER M4 ;
        RECT  17.064 17.04 17.256 17.064 ;
    END
  END do0[295]
  PIN do0[296]
    DIRECTION OUTPUT ;
    USE SIGNAL ;
    PORT
      LAYER M4 ;
        RECT  17.064 17.088 17.256 17.112 ;
    END
  END do0[296]
  PIN do0[297]
    DIRECTION OUTPUT ;
    USE SIGNAL ;
    PORT
      LAYER M4 ;
        RECT  17.064 17.136 17.256 17.16 ;
    END
  END do0[297]
  PIN do0[298]
    DIRECTION OUTPUT ;
    USE SIGNAL ;
    PORT
      LAYER M4 ;
        RECT  17.064 17.184 17.256 17.208 ;
    END
  END do0[298]
  PIN do0[299]
    DIRECTION OUTPUT ;
    USE SIGNAL ;
    PORT
      LAYER M4 ;
        RECT  17.064 17.232 17.256 17.256 ;
    END
  END do0[299]
  PIN do0[29]
    DIRECTION OUTPUT ;
    USE SIGNAL ;
    PORT
      LAYER M4 ;
        RECT  17.064 4.272 17.256 4.296 ;
    END
  END do0[29]
  PIN do0[2]
    DIRECTION OUTPUT ;
    USE SIGNAL ;
    PORT
      LAYER M4 ;
        RECT  17.064 2.976 17.256 3 ;
    END
  END do0[2]
  PIN do0[300]
    DIRECTION OUTPUT ;
    USE SIGNAL ;
    PORT
      LAYER M4 ;
        RECT  17.064 17.28 17.256 17.304 ;
    END
  END do0[300]
  PIN do0[301]
    DIRECTION OUTPUT ;
    USE SIGNAL ;
    PORT
      LAYER M4 ;
        RECT  17.064 17.328 17.256 17.352 ;
    END
  END do0[301]
  PIN do0[302]
    DIRECTION OUTPUT ;
    USE SIGNAL ;
    PORT
      LAYER M4 ;
        RECT  17.064 17.376 17.256 17.4 ;
    END
  END do0[302]
  PIN do0[303]
    DIRECTION OUTPUT ;
    USE SIGNAL ;
    PORT
      LAYER M4 ;
        RECT  17.064 17.424 17.256 17.448 ;
    END
  END do0[303]
  PIN do0[304]
    DIRECTION OUTPUT ;
    USE SIGNAL ;
    PORT
      LAYER M4 ;
        RECT  17.064 17.472 17.256 17.496 ;
    END
  END do0[304]
  PIN do0[305]
    DIRECTION OUTPUT ;
    USE SIGNAL ;
    PORT
      LAYER M4 ;
        RECT  17.064 17.52 17.256 17.544 ;
    END
  END do0[305]
  PIN do0[306]
    DIRECTION OUTPUT ;
    USE SIGNAL ;
    PORT
      LAYER M4 ;
        RECT  17.064 17.568 17.256 17.592 ;
    END
  END do0[306]
  PIN do0[307]
    DIRECTION OUTPUT ;
    USE SIGNAL ;
    PORT
      LAYER M4 ;
        RECT  17.064 17.616 17.256 17.64 ;
    END
  END do0[307]
  PIN do0[308]
    DIRECTION OUTPUT ;
    USE SIGNAL ;
    PORT
      LAYER M4 ;
        RECT  17.064 17.664 17.256 17.688 ;
    END
  END do0[308]
  PIN do0[309]
    DIRECTION OUTPUT ;
    USE SIGNAL ;
    PORT
      LAYER M4 ;
        RECT  17.064 17.712 17.256 17.736 ;
    END
  END do0[309]
  PIN do0[30]
    DIRECTION OUTPUT ;
    USE SIGNAL ;
    PORT
      LAYER M4 ;
        RECT  17.064 4.32 17.256 4.344 ;
    END
  END do0[30]
  PIN do0[310]
    DIRECTION OUTPUT ;
    USE SIGNAL ;
    PORT
      LAYER M4 ;
        RECT  17.064 17.76 17.256 17.784 ;
    END
  END do0[310]
  PIN do0[311]
    DIRECTION OUTPUT ;
    USE SIGNAL ;
    PORT
      LAYER M4 ;
        RECT  17.064 17.808 17.256 17.832 ;
    END
  END do0[311]
  PIN do0[312]
    DIRECTION OUTPUT ;
    USE SIGNAL ;
    PORT
      LAYER M4 ;
        RECT  17.064 17.856 17.256 17.88 ;
    END
  END do0[312]
  PIN do0[313]
    DIRECTION OUTPUT ;
    USE SIGNAL ;
    PORT
      LAYER M4 ;
        RECT  17.064 17.904 17.256 17.928 ;
    END
  END do0[313]
  PIN do0[314]
    DIRECTION OUTPUT ;
    USE SIGNAL ;
    PORT
      LAYER M4 ;
        RECT  17.064 17.952 17.256 17.976 ;
    END
  END do0[314]
  PIN do0[315]
    DIRECTION OUTPUT ;
    USE SIGNAL ;
    PORT
      LAYER M4 ;
        RECT  17.064 18 17.256 18.024 ;
    END
  END do0[315]
  PIN do0[316]
    DIRECTION OUTPUT ;
    USE SIGNAL ;
    PORT
      LAYER M4 ;
        RECT  17.064 18.048 17.256 18.072 ;
    END
  END do0[316]
  PIN do0[317]
    DIRECTION OUTPUT ;
    USE SIGNAL ;
    PORT
      LAYER M4 ;
        RECT  17.064 18.096 17.256 18.12 ;
    END
  END do0[317]
  PIN do0[318]
    DIRECTION OUTPUT ;
    USE SIGNAL ;
    PORT
      LAYER M4 ;
        RECT  17.064 18.144 17.256 18.168 ;
    END
  END do0[318]
  PIN do0[319]
    DIRECTION OUTPUT ;
    USE SIGNAL ;
    PORT
      LAYER M4 ;
        RECT  17.064 18.192 17.256 18.216 ;
    END
  END do0[319]
  PIN do0[31]
    DIRECTION OUTPUT ;
    USE SIGNAL ;
    PORT
      LAYER M4 ;
        RECT  17.064 4.368 17.256 4.392 ;
    END
  END do0[31]
  PIN do0[320]
    DIRECTION OUTPUT ;
    USE SIGNAL ;
    PORT
      LAYER M4 ;
        RECT  17.064 18.24 17.256 18.264 ;
    END
  END do0[320]
  PIN do0[321]
    DIRECTION OUTPUT ;
    USE SIGNAL ;
    PORT
      LAYER M4 ;
        RECT  17.064 18.288 17.256 18.312 ;
    END
  END do0[321]
  PIN do0[322]
    DIRECTION OUTPUT ;
    USE SIGNAL ;
    PORT
      LAYER M4 ;
        RECT  17.064 18.336 17.256 18.36 ;
    END
  END do0[322]
  PIN do0[323]
    DIRECTION OUTPUT ;
    USE SIGNAL ;
    PORT
      LAYER M4 ;
        RECT  17.064 18.384 17.256 18.408 ;
    END
  END do0[323]
  PIN do0[324]
    DIRECTION OUTPUT ;
    USE SIGNAL ;
    PORT
      LAYER M4 ;
        RECT  17.064 18.432 17.256 18.456 ;
    END
  END do0[324]
  PIN do0[325]
    DIRECTION OUTPUT ;
    USE SIGNAL ;
    PORT
      LAYER M4 ;
        RECT  17.064 18.48 17.256 18.504 ;
    END
  END do0[325]
  PIN do0[326]
    DIRECTION OUTPUT ;
    USE SIGNAL ;
    PORT
      LAYER M4 ;
        RECT  17.064 18.528 17.256 18.552 ;
    END
  END do0[326]
  PIN do0[327]
    DIRECTION OUTPUT ;
    USE SIGNAL ;
    PORT
      LAYER M4 ;
        RECT  17.064 18.576 17.256 18.6 ;
    END
  END do0[327]
  PIN do0[328]
    DIRECTION OUTPUT ;
    USE SIGNAL ;
    PORT
      LAYER M4 ;
        RECT  17.064 18.624 17.256 18.648 ;
    END
  END do0[328]
  PIN do0[329]
    DIRECTION OUTPUT ;
    USE SIGNAL ;
    PORT
      LAYER M4 ;
        RECT  17.064 18.672 17.256 18.696 ;
    END
  END do0[329]
  PIN do0[32]
    DIRECTION OUTPUT ;
    USE SIGNAL ;
    PORT
      LAYER M4 ;
        RECT  17.064 4.416 17.256 4.44 ;
    END
  END do0[32]
  PIN do0[330]
    DIRECTION OUTPUT ;
    USE SIGNAL ;
    PORT
      LAYER M4 ;
        RECT  17.064 18.72 17.256 18.744 ;
    END
  END do0[330]
  PIN do0[331]
    DIRECTION OUTPUT ;
    USE SIGNAL ;
    PORT
      LAYER M4 ;
        RECT  17.064 18.768 17.256 18.792 ;
    END
  END do0[331]
  PIN do0[332]
    DIRECTION OUTPUT ;
    USE SIGNAL ;
    PORT
      LAYER M4 ;
        RECT  17.064 18.816 17.256 18.84 ;
    END
  END do0[332]
  PIN do0[333]
    DIRECTION OUTPUT ;
    USE SIGNAL ;
    PORT
      LAYER M4 ;
        RECT  17.064 18.864 17.256 18.888 ;
    END
  END do0[333]
  PIN do0[334]
    DIRECTION OUTPUT ;
    USE SIGNAL ;
    PORT
      LAYER M4 ;
        RECT  17.064 18.912 17.256 18.936 ;
    END
  END do0[334]
  PIN do0[335]
    DIRECTION OUTPUT ;
    USE SIGNAL ;
    PORT
      LAYER M4 ;
        RECT  17.064 18.96 17.256 18.984 ;
    END
  END do0[335]
  PIN do0[336]
    DIRECTION OUTPUT ;
    USE SIGNAL ;
    PORT
      LAYER M4 ;
        RECT  17.064 19.008 17.256 19.032 ;
    END
  END do0[336]
  PIN do0[337]
    DIRECTION OUTPUT ;
    USE SIGNAL ;
    PORT
      LAYER M4 ;
        RECT  17.064 19.056 17.256 19.08 ;
    END
  END do0[337]
  PIN do0[338]
    DIRECTION OUTPUT ;
    USE SIGNAL ;
    PORT
      LAYER M4 ;
        RECT  17.064 19.104 17.256 19.128 ;
    END
  END do0[338]
  PIN do0[339]
    DIRECTION OUTPUT ;
    USE SIGNAL ;
    PORT
      LAYER M4 ;
        RECT  17.064 19.152 17.256 19.176 ;
    END
  END do0[339]
  PIN do0[33]
    DIRECTION OUTPUT ;
    USE SIGNAL ;
    PORT
      LAYER M4 ;
        RECT  17.064 4.464 17.256 4.488 ;
    END
  END do0[33]
  PIN do0[340]
    DIRECTION OUTPUT ;
    USE SIGNAL ;
    PORT
      LAYER M4 ;
        RECT  17.064 19.2 17.256 19.224 ;
    END
  END do0[340]
  PIN do0[341]
    DIRECTION OUTPUT ;
    USE SIGNAL ;
    PORT
      LAYER M4 ;
        RECT  17.064 19.248 17.256 19.272 ;
    END
  END do0[341]
  PIN do0[342]
    DIRECTION OUTPUT ;
    USE SIGNAL ;
    PORT
      LAYER M4 ;
        RECT  17.064 19.296 17.256 19.32 ;
    END
  END do0[342]
  PIN do0[343]
    DIRECTION OUTPUT ;
    USE SIGNAL ;
    PORT
      LAYER M4 ;
        RECT  17.064 19.344 17.256 19.368 ;
    END
  END do0[343]
  PIN do0[344]
    DIRECTION OUTPUT ;
    USE SIGNAL ;
    PORT
      LAYER M4 ;
        RECT  17.064 19.392 17.256 19.416 ;
    END
  END do0[344]
  PIN do0[345]
    DIRECTION OUTPUT ;
    USE SIGNAL ;
    PORT
      LAYER M4 ;
        RECT  17.064 19.44 17.256 19.464 ;
    END
  END do0[345]
  PIN do0[346]
    DIRECTION OUTPUT ;
    USE SIGNAL ;
    PORT
      LAYER M4 ;
        RECT  17.064 19.488 17.256 19.512 ;
    END
  END do0[346]
  PIN do0[347]
    DIRECTION OUTPUT ;
    USE SIGNAL ;
    PORT
      LAYER M4 ;
        RECT  17.064 19.536 17.256 19.56 ;
    END
  END do0[347]
  PIN do0[348]
    DIRECTION OUTPUT ;
    USE SIGNAL ;
    PORT
      LAYER M4 ;
        RECT  17.064 19.584 17.256 19.608 ;
    END
  END do0[348]
  PIN do0[349]
    DIRECTION OUTPUT ;
    USE SIGNAL ;
    PORT
      LAYER M4 ;
        RECT  17.064 19.632 17.256 19.656 ;
    END
  END do0[349]
  PIN do0[34]
    DIRECTION OUTPUT ;
    USE SIGNAL ;
    PORT
      LAYER M4 ;
        RECT  17.064 4.512 17.256 4.536 ;
    END
  END do0[34]
  PIN do0[350]
    DIRECTION OUTPUT ;
    USE SIGNAL ;
    PORT
      LAYER M4 ;
        RECT  17.064 19.68 17.256 19.704 ;
    END
  END do0[350]
  PIN do0[351]
    DIRECTION OUTPUT ;
    USE SIGNAL ;
    PORT
      LAYER M4 ;
        RECT  17.064 19.728 17.256 19.752 ;
    END
  END do0[351]
  PIN do0[352]
    DIRECTION OUTPUT ;
    USE SIGNAL ;
    PORT
      LAYER M4 ;
        RECT  17.064 19.776 17.256 19.8 ;
    END
  END do0[352]
  PIN do0[353]
    DIRECTION OUTPUT ;
    USE SIGNAL ;
    PORT
      LAYER M4 ;
        RECT  17.064 19.824 17.256 19.848 ;
    END
  END do0[353]
  PIN do0[354]
    DIRECTION OUTPUT ;
    USE SIGNAL ;
    PORT
      LAYER M4 ;
        RECT  17.064 19.872 17.256 19.896 ;
    END
  END do0[354]
  PIN do0[355]
    DIRECTION OUTPUT ;
    USE SIGNAL ;
    PORT
      LAYER M4 ;
        RECT  17.064 19.92 17.256 19.944 ;
    END
  END do0[355]
  PIN do0[356]
    DIRECTION OUTPUT ;
    USE SIGNAL ;
    PORT
      LAYER M4 ;
        RECT  17.064 19.968 17.256 19.992 ;
    END
  END do0[356]
  PIN do0[357]
    DIRECTION OUTPUT ;
    USE SIGNAL ;
    PORT
      LAYER M4 ;
        RECT  17.064 20.016 17.256 20.04 ;
    END
  END do0[357]
  PIN do0[358]
    DIRECTION OUTPUT ;
    USE SIGNAL ;
    PORT
      LAYER M4 ;
        RECT  17.064 20.064 17.256 20.088 ;
    END
  END do0[358]
  PIN do0[359]
    DIRECTION OUTPUT ;
    USE SIGNAL ;
    PORT
      LAYER M4 ;
        RECT  17.064 20.112 17.256 20.136 ;
    END
  END do0[359]
  PIN do0[35]
    DIRECTION OUTPUT ;
    USE SIGNAL ;
    PORT
      LAYER M4 ;
        RECT  17.064 4.56 17.256 4.584 ;
    END
  END do0[35]
  PIN do0[360]
    DIRECTION OUTPUT ;
    USE SIGNAL ;
    PORT
      LAYER M4 ;
        RECT  17.064 20.16 17.256 20.184 ;
    END
  END do0[360]
  PIN do0[361]
    DIRECTION OUTPUT ;
    USE SIGNAL ;
    PORT
      LAYER M4 ;
        RECT  17.064 20.208 17.256 20.232 ;
    END
  END do0[361]
  PIN do0[362]
    DIRECTION OUTPUT ;
    USE SIGNAL ;
    PORT
      LAYER M4 ;
        RECT  17.064 20.256 17.256 20.28 ;
    END
  END do0[362]
  PIN do0[363]
    DIRECTION OUTPUT ;
    USE SIGNAL ;
    PORT
      LAYER M4 ;
        RECT  17.064 20.304 17.256 20.328 ;
    END
  END do0[363]
  PIN do0[364]
    DIRECTION OUTPUT ;
    USE SIGNAL ;
    PORT
      LAYER M4 ;
        RECT  17.064 20.352 17.256 20.376 ;
    END
  END do0[364]
  PIN do0[365]
    DIRECTION OUTPUT ;
    USE SIGNAL ;
    PORT
      LAYER M4 ;
        RECT  17.064 20.4 17.256 20.424 ;
    END
  END do0[365]
  PIN do0[366]
    DIRECTION OUTPUT ;
    USE SIGNAL ;
    PORT
      LAYER M4 ;
        RECT  17.064 20.448 17.256 20.472 ;
    END
  END do0[366]
  PIN do0[367]
    DIRECTION OUTPUT ;
    USE SIGNAL ;
    PORT
      LAYER M4 ;
        RECT  17.064 20.496 17.256 20.52 ;
    END
  END do0[367]
  PIN do0[368]
    DIRECTION OUTPUT ;
    USE SIGNAL ;
    PORT
      LAYER M4 ;
        RECT  17.064 20.544 17.256 20.568 ;
    END
  END do0[368]
  PIN do0[369]
    DIRECTION OUTPUT ;
    USE SIGNAL ;
    PORT
      LAYER M4 ;
        RECT  17.064 20.592 17.256 20.616 ;
    END
  END do0[369]
  PIN do0[36]
    DIRECTION OUTPUT ;
    USE SIGNAL ;
    PORT
      LAYER M4 ;
        RECT  17.064 4.608 17.256 4.632 ;
    END
  END do0[36]
  PIN do0[370]
    DIRECTION OUTPUT ;
    USE SIGNAL ;
    PORT
      LAYER M4 ;
        RECT  17.064 20.64 17.256 20.664 ;
    END
  END do0[370]
  PIN do0[371]
    DIRECTION OUTPUT ;
    USE SIGNAL ;
    PORT
      LAYER M4 ;
        RECT  17.064 20.688 17.256 20.712 ;
    END
  END do0[371]
  PIN do0[372]
    DIRECTION OUTPUT ;
    USE SIGNAL ;
    PORT
      LAYER M4 ;
        RECT  17.064 20.736 17.256 20.76 ;
    END
  END do0[372]
  PIN do0[373]
    DIRECTION OUTPUT ;
    USE SIGNAL ;
    PORT
      LAYER M4 ;
        RECT  17.064 20.784 17.256 20.808 ;
    END
  END do0[373]
  PIN do0[374]
    DIRECTION OUTPUT ;
    USE SIGNAL ;
    PORT
      LAYER M4 ;
        RECT  17.064 20.832 17.256 20.856 ;
    END
  END do0[374]
  PIN do0[375]
    DIRECTION OUTPUT ;
    USE SIGNAL ;
    PORT
      LAYER M4 ;
        RECT  17.064 20.88 17.256 20.904 ;
    END
  END do0[375]
  PIN do0[376]
    DIRECTION OUTPUT ;
    USE SIGNAL ;
    PORT
      LAYER M4 ;
        RECT  17.064 20.928 17.256 20.952 ;
    END
  END do0[376]
  PIN do0[377]
    DIRECTION OUTPUT ;
    USE SIGNAL ;
    PORT
      LAYER M4 ;
        RECT  17.064 20.976 17.256 21 ;
    END
  END do0[377]
  PIN do0[378]
    DIRECTION OUTPUT ;
    USE SIGNAL ;
    PORT
      LAYER M4 ;
        RECT  17.064 21.024 17.256 21.048 ;
    END
  END do0[378]
  PIN do0[379]
    DIRECTION OUTPUT ;
    USE SIGNAL ;
    PORT
      LAYER M4 ;
        RECT  17.064 21.072 17.256 21.096 ;
    END
  END do0[379]
  PIN do0[37]
    DIRECTION OUTPUT ;
    USE SIGNAL ;
    PORT
      LAYER M4 ;
        RECT  17.064 4.656 17.256 4.68 ;
    END
  END do0[37]
  PIN do0[380]
    DIRECTION OUTPUT ;
    USE SIGNAL ;
    PORT
      LAYER M4 ;
        RECT  17.064 21.12 17.256 21.144 ;
    END
  END do0[380]
  PIN do0[381]
    DIRECTION OUTPUT ;
    USE SIGNAL ;
    PORT
      LAYER M4 ;
        RECT  17.064 21.168 17.256 21.192 ;
    END
  END do0[381]
  PIN do0[382]
    DIRECTION OUTPUT ;
    USE SIGNAL ;
    PORT
      LAYER M4 ;
        RECT  17.064 21.216 17.256 21.24 ;
    END
  END do0[382]
  PIN do0[383]
    DIRECTION OUTPUT ;
    USE SIGNAL ;
    PORT
      LAYER M4 ;
        RECT  17.064 21.264 17.256 21.288 ;
    END
  END do0[383]
  PIN do0[384]
    DIRECTION OUTPUT ;
    USE SIGNAL ;
    PORT
      LAYER M4 ;
        RECT  17.064 21.312 17.256 21.336 ;
    END
  END do0[384]
  PIN do0[385]
    DIRECTION OUTPUT ;
    USE SIGNAL ;
    PORT
      LAYER M4 ;
        RECT  17.064 21.36 17.256 21.384 ;
    END
  END do0[385]
  PIN do0[386]
    DIRECTION OUTPUT ;
    USE SIGNAL ;
    PORT
      LAYER M4 ;
        RECT  17.064 21.408 17.256 21.432 ;
    END
  END do0[386]
  PIN do0[387]
    DIRECTION OUTPUT ;
    USE SIGNAL ;
    PORT
      LAYER M4 ;
        RECT  17.064 21.456 17.256 21.48 ;
    END
  END do0[387]
  PIN do0[388]
    DIRECTION OUTPUT ;
    USE SIGNAL ;
    PORT
      LAYER M4 ;
        RECT  17.064 21.504 17.256 21.528 ;
    END
  END do0[388]
  PIN do0[389]
    DIRECTION OUTPUT ;
    USE SIGNAL ;
    PORT
      LAYER M4 ;
        RECT  17.064 21.552 17.256 21.576 ;
    END
  END do0[389]
  PIN do0[38]
    DIRECTION OUTPUT ;
    USE SIGNAL ;
    PORT
      LAYER M4 ;
        RECT  17.064 4.704 17.256 4.728 ;
    END
  END do0[38]
  PIN do0[390]
    DIRECTION OUTPUT ;
    USE SIGNAL ;
    PORT
      LAYER M4 ;
        RECT  17.064 21.6 17.256 21.624 ;
    END
  END do0[390]
  PIN do0[391]
    DIRECTION OUTPUT ;
    USE SIGNAL ;
    PORT
      LAYER M4 ;
        RECT  17.064 21.648 17.256 21.672 ;
    END
  END do0[391]
  PIN do0[392]
    DIRECTION OUTPUT ;
    USE SIGNAL ;
    PORT
      LAYER M4 ;
        RECT  17.064 21.696 17.256 21.72 ;
    END
  END do0[392]
  PIN do0[393]
    DIRECTION OUTPUT ;
    USE SIGNAL ;
    PORT
      LAYER M4 ;
        RECT  17.064 21.744 17.256 21.768 ;
    END
  END do0[393]
  PIN do0[394]
    DIRECTION OUTPUT ;
    USE SIGNAL ;
    PORT
      LAYER M4 ;
        RECT  17.064 21.792 17.256 21.816 ;
    END
  END do0[394]
  PIN do0[395]
    DIRECTION OUTPUT ;
    USE SIGNAL ;
    PORT
      LAYER M4 ;
        RECT  17.064 21.84 17.256 21.864 ;
    END
  END do0[395]
  PIN do0[396]
    DIRECTION OUTPUT ;
    USE SIGNAL ;
    PORT
      LAYER M4 ;
        RECT  17.064 21.888 17.256 21.912 ;
    END
  END do0[396]
  PIN do0[397]
    DIRECTION OUTPUT ;
    USE SIGNAL ;
    PORT
      LAYER M4 ;
        RECT  17.064 21.936 17.256 21.96 ;
    END
  END do0[397]
  PIN do0[398]
    DIRECTION OUTPUT ;
    USE SIGNAL ;
    PORT
      LAYER M4 ;
        RECT  17.064 21.984 17.256 22.008 ;
    END
  END do0[398]
  PIN do0[399]
    DIRECTION OUTPUT ;
    USE SIGNAL ;
    PORT
      LAYER M4 ;
        RECT  17.064 22.032 17.256 22.056 ;
    END
  END do0[399]
  PIN do0[39]
    DIRECTION OUTPUT ;
    USE SIGNAL ;
    PORT
      LAYER M4 ;
        RECT  17.064 4.752 17.256 4.776 ;
    END
  END do0[39]
  PIN do0[3]
    DIRECTION OUTPUT ;
    USE SIGNAL ;
    PORT
      LAYER M4 ;
        RECT  17.064 3.024 17.256 3.048 ;
    END
  END do0[3]
  PIN do0[400]
    DIRECTION OUTPUT ;
    USE SIGNAL ;
    PORT
      LAYER M4 ;
        RECT  17.064 22.08 17.256 22.104 ;
    END
  END do0[400]
  PIN do0[401]
    DIRECTION OUTPUT ;
    USE SIGNAL ;
    PORT
      LAYER M4 ;
        RECT  17.064 22.128 17.256 22.152 ;
    END
  END do0[401]
  PIN do0[402]
    DIRECTION OUTPUT ;
    USE SIGNAL ;
    PORT
      LAYER M4 ;
        RECT  17.064 22.176 17.256 22.2 ;
    END
  END do0[402]
  PIN do0[403]
    DIRECTION OUTPUT ;
    USE SIGNAL ;
    PORT
      LAYER M4 ;
        RECT  17.064 22.224 17.256 22.248 ;
    END
  END do0[403]
  PIN do0[404]
    DIRECTION OUTPUT ;
    USE SIGNAL ;
    PORT
      LAYER M4 ;
        RECT  17.064 22.272 17.256 22.296 ;
    END
  END do0[404]
  PIN do0[405]
    DIRECTION OUTPUT ;
    USE SIGNAL ;
    PORT
      LAYER M4 ;
        RECT  17.064 22.32 17.256 22.344 ;
    END
  END do0[405]
  PIN do0[406]
    DIRECTION OUTPUT ;
    USE SIGNAL ;
    PORT
      LAYER M4 ;
        RECT  17.064 22.368 17.256 22.392 ;
    END
  END do0[406]
  PIN do0[407]
    DIRECTION OUTPUT ;
    USE SIGNAL ;
    PORT
      LAYER M4 ;
        RECT  17.064 22.416 17.256 22.44 ;
    END
  END do0[407]
  PIN do0[408]
    DIRECTION OUTPUT ;
    USE SIGNAL ;
    PORT
      LAYER M4 ;
        RECT  17.064 22.464 17.256 22.488 ;
    END
  END do0[408]
  PIN do0[409]
    DIRECTION OUTPUT ;
    USE SIGNAL ;
    PORT
      LAYER M4 ;
        RECT  17.064 22.512 17.256 22.536 ;
    END
  END do0[409]
  PIN do0[40]
    DIRECTION OUTPUT ;
    USE SIGNAL ;
    PORT
      LAYER M4 ;
        RECT  17.064 4.8 17.256 4.824 ;
    END
  END do0[40]
  PIN do0[410]
    DIRECTION OUTPUT ;
    USE SIGNAL ;
    PORT
      LAYER M4 ;
        RECT  17.064 22.56 17.256 22.584 ;
    END
  END do0[410]
  PIN do0[411]
    DIRECTION OUTPUT ;
    USE SIGNAL ;
    PORT
      LAYER M4 ;
        RECT  17.064 22.608 17.256 22.632 ;
    END
  END do0[411]
  PIN do0[412]
    DIRECTION OUTPUT ;
    USE SIGNAL ;
    PORT
      LAYER M4 ;
        RECT  17.064 22.656 17.256 22.68 ;
    END
  END do0[412]
  PIN do0[413]
    DIRECTION OUTPUT ;
    USE SIGNAL ;
    PORT
      LAYER M4 ;
        RECT  17.064 22.704 17.256 22.728 ;
    END
  END do0[413]
  PIN do0[414]
    DIRECTION OUTPUT ;
    USE SIGNAL ;
    PORT
      LAYER M4 ;
        RECT  17.064 22.752 17.256 22.776 ;
    END
  END do0[414]
  PIN do0[415]
    DIRECTION OUTPUT ;
    USE SIGNAL ;
    PORT
      LAYER M4 ;
        RECT  17.064 22.8 17.256 22.824 ;
    END
  END do0[415]
  PIN do0[416]
    DIRECTION OUTPUT ;
    USE SIGNAL ;
    PORT
      LAYER M4 ;
        RECT  17.064 22.848 17.256 22.872 ;
    END
  END do0[416]
  PIN do0[417]
    DIRECTION OUTPUT ;
    USE SIGNAL ;
    PORT
      LAYER M4 ;
        RECT  17.064 22.896 17.256 22.92 ;
    END
  END do0[417]
  PIN do0[418]
    DIRECTION OUTPUT ;
    USE SIGNAL ;
    PORT
      LAYER M4 ;
        RECT  17.064 22.944 17.256 22.968 ;
    END
  END do0[418]
  PIN do0[419]
    DIRECTION OUTPUT ;
    USE SIGNAL ;
    PORT
      LAYER M4 ;
        RECT  17.064 22.992 17.256 23.016 ;
    END
  END do0[419]
  PIN do0[41]
    DIRECTION OUTPUT ;
    USE SIGNAL ;
    PORT
      LAYER M4 ;
        RECT  17.064 4.848 17.256 4.872 ;
    END
  END do0[41]
  PIN do0[420]
    DIRECTION OUTPUT ;
    USE SIGNAL ;
    PORT
      LAYER M4 ;
        RECT  17.064 23.04 17.256 23.064 ;
    END
  END do0[420]
  PIN do0[421]
    DIRECTION OUTPUT ;
    USE SIGNAL ;
    PORT
      LAYER M4 ;
        RECT  17.064 23.088 17.256 23.112 ;
    END
  END do0[421]
  PIN do0[422]
    DIRECTION OUTPUT ;
    USE SIGNAL ;
    PORT
      LAYER M4 ;
        RECT  17.064 23.136 17.256 23.16 ;
    END
  END do0[422]
  PIN do0[423]
    DIRECTION OUTPUT ;
    USE SIGNAL ;
    PORT
      LAYER M4 ;
        RECT  17.064 23.184 17.256 23.208 ;
    END
  END do0[423]
  PIN do0[424]
    DIRECTION OUTPUT ;
    USE SIGNAL ;
    PORT
      LAYER M4 ;
        RECT  17.064 23.232 17.256 23.256 ;
    END
  END do0[424]
  PIN do0[425]
    DIRECTION OUTPUT ;
    USE SIGNAL ;
    PORT
      LAYER M4 ;
        RECT  17.064 23.28 17.256 23.304 ;
    END
  END do0[425]
  PIN do0[426]
    DIRECTION OUTPUT ;
    USE SIGNAL ;
    PORT
      LAYER M4 ;
        RECT  17.064 23.328 17.256 23.352 ;
    END
  END do0[426]
  PIN do0[427]
    DIRECTION OUTPUT ;
    USE SIGNAL ;
    PORT
      LAYER M4 ;
        RECT  17.064 23.376 17.256 23.4 ;
    END
  END do0[427]
  PIN do0[428]
    DIRECTION OUTPUT ;
    USE SIGNAL ;
    PORT
      LAYER M4 ;
        RECT  17.064 23.424 17.256 23.448 ;
    END
  END do0[428]
  PIN do0[429]
    DIRECTION OUTPUT ;
    USE SIGNAL ;
    PORT
      LAYER M4 ;
        RECT  17.064 23.472 17.256 23.496 ;
    END
  END do0[429]
  PIN do0[42]
    DIRECTION OUTPUT ;
    USE SIGNAL ;
    PORT
      LAYER M4 ;
        RECT  17.064 4.896 17.256 4.92 ;
    END
  END do0[42]
  PIN do0[430]
    DIRECTION OUTPUT ;
    USE SIGNAL ;
    PORT
      LAYER M4 ;
        RECT  17.064 23.52 17.256 23.544 ;
    END
  END do0[430]
  PIN do0[431]
    DIRECTION OUTPUT ;
    USE SIGNAL ;
    PORT
      LAYER M4 ;
        RECT  17.064 23.568 17.256 23.592 ;
    END
  END do0[431]
  PIN do0[432]
    DIRECTION OUTPUT ;
    USE SIGNAL ;
    PORT
      LAYER M4 ;
        RECT  17.064 23.616 17.256 23.64 ;
    END
  END do0[432]
  PIN do0[433]
    DIRECTION OUTPUT ;
    USE SIGNAL ;
    PORT
      LAYER M4 ;
        RECT  17.064 23.664 17.256 23.688 ;
    END
  END do0[433]
  PIN do0[434]
    DIRECTION OUTPUT ;
    USE SIGNAL ;
    PORT
      LAYER M4 ;
        RECT  17.064 23.712 17.256 23.736 ;
    END
  END do0[434]
  PIN do0[435]
    DIRECTION OUTPUT ;
    USE SIGNAL ;
    PORT
      LAYER M4 ;
        RECT  17.064 23.76 17.256 23.784 ;
    END
  END do0[435]
  PIN do0[436]
    DIRECTION OUTPUT ;
    USE SIGNAL ;
    PORT
      LAYER M4 ;
        RECT  17.064 23.808 17.256 23.832 ;
    END
  END do0[436]
  PIN do0[437]
    DIRECTION OUTPUT ;
    USE SIGNAL ;
    PORT
      LAYER M4 ;
        RECT  17.064 23.856 17.256 23.88 ;
    END
  END do0[437]
  PIN do0[438]
    DIRECTION OUTPUT ;
    USE SIGNAL ;
    PORT
      LAYER M4 ;
        RECT  17.064 23.904 17.256 23.928 ;
    END
  END do0[438]
  PIN do0[439]
    DIRECTION OUTPUT ;
    USE SIGNAL ;
    PORT
      LAYER M4 ;
        RECT  17.064 23.952 17.256 23.976 ;
    END
  END do0[439]
  PIN do0[43]
    DIRECTION OUTPUT ;
    USE SIGNAL ;
    PORT
      LAYER M4 ;
        RECT  17.064 4.944 17.256 4.968 ;
    END
  END do0[43]
  PIN do0[440]
    DIRECTION OUTPUT ;
    USE SIGNAL ;
    PORT
      LAYER M4 ;
        RECT  17.064 24 17.256 24.024 ;
    END
  END do0[440]
  PIN do0[441]
    DIRECTION OUTPUT ;
    USE SIGNAL ;
    PORT
      LAYER M4 ;
        RECT  17.064 24.048 17.256 24.072 ;
    END
  END do0[441]
  PIN do0[442]
    DIRECTION OUTPUT ;
    USE SIGNAL ;
    PORT
      LAYER M4 ;
        RECT  17.064 24.096 17.256 24.12 ;
    END
  END do0[442]
  PIN do0[443]
    DIRECTION OUTPUT ;
    USE SIGNAL ;
    PORT
      LAYER M4 ;
        RECT  17.064 24.144 17.256 24.168 ;
    END
  END do0[443]
  PIN do0[444]
    DIRECTION OUTPUT ;
    USE SIGNAL ;
    PORT
      LAYER M4 ;
        RECT  17.064 24.192 17.256 24.216 ;
    END
  END do0[444]
  PIN do0[445]
    DIRECTION OUTPUT ;
    USE SIGNAL ;
    PORT
      LAYER M4 ;
        RECT  17.064 24.24 17.256 24.264 ;
    END
  END do0[445]
  PIN do0[446]
    DIRECTION OUTPUT ;
    USE SIGNAL ;
    PORT
      LAYER M4 ;
        RECT  17.064 24.288 17.256 24.312 ;
    END
  END do0[446]
  PIN do0[447]
    DIRECTION OUTPUT ;
    USE SIGNAL ;
    PORT
      LAYER M4 ;
        RECT  17.064 24.336 17.256 24.36 ;
    END
  END do0[447]
  PIN do0[448]
    DIRECTION OUTPUT ;
    USE SIGNAL ;
    PORT
      LAYER M4 ;
        RECT  17.064 24.384 17.256 24.408 ;
    END
  END do0[448]
  PIN do0[449]
    DIRECTION OUTPUT ;
    USE SIGNAL ;
    PORT
      LAYER M4 ;
        RECT  17.064 24.432 17.256 24.456 ;
    END
  END do0[449]
  PIN do0[44]
    DIRECTION OUTPUT ;
    USE SIGNAL ;
    PORT
      LAYER M4 ;
        RECT  17.064 4.992 17.256 5.016 ;
    END
  END do0[44]
  PIN do0[450]
    DIRECTION OUTPUT ;
    USE SIGNAL ;
    PORT
      LAYER M4 ;
        RECT  17.064 24.48 17.256 24.504 ;
    END
  END do0[450]
  PIN do0[451]
    DIRECTION OUTPUT ;
    USE SIGNAL ;
    PORT
      LAYER M4 ;
        RECT  17.064 24.528 17.256 24.552 ;
    END
  END do0[451]
  PIN do0[452]
    DIRECTION OUTPUT ;
    USE SIGNAL ;
    PORT
      LAYER M4 ;
        RECT  17.064 24.576 17.256 24.6 ;
    END
  END do0[452]
  PIN do0[453]
    DIRECTION OUTPUT ;
    USE SIGNAL ;
    PORT
      LAYER M4 ;
        RECT  17.064 24.624 17.256 24.648 ;
    END
  END do0[453]
  PIN do0[454]
    DIRECTION OUTPUT ;
    USE SIGNAL ;
    PORT
      LAYER M4 ;
        RECT  17.064 24.672 17.256 24.696 ;
    END
  END do0[454]
  PIN do0[455]
    DIRECTION OUTPUT ;
    USE SIGNAL ;
    PORT
      LAYER M4 ;
        RECT  17.064 24.72 17.256 24.744 ;
    END
  END do0[455]
  PIN do0[456]
    DIRECTION OUTPUT ;
    USE SIGNAL ;
    PORT
      LAYER M4 ;
        RECT  17.064 24.768 17.256 24.792 ;
    END
  END do0[456]
  PIN do0[457]
    DIRECTION OUTPUT ;
    USE SIGNAL ;
    PORT
      LAYER M4 ;
        RECT  17.064 24.816 17.256 24.84 ;
    END
  END do0[457]
  PIN do0[458]
    DIRECTION OUTPUT ;
    USE SIGNAL ;
    PORT
      LAYER M4 ;
        RECT  17.064 24.864 17.256 24.888 ;
    END
  END do0[458]
  PIN do0[459]
    DIRECTION OUTPUT ;
    USE SIGNAL ;
    PORT
      LAYER M4 ;
        RECT  17.064 24.912 17.256 24.936 ;
    END
  END do0[459]
  PIN do0[45]
    DIRECTION OUTPUT ;
    USE SIGNAL ;
    PORT
      LAYER M4 ;
        RECT  17.064 5.04 17.256 5.064 ;
    END
  END do0[45]
  PIN do0[460]
    DIRECTION OUTPUT ;
    USE SIGNAL ;
    PORT
      LAYER M4 ;
        RECT  17.064 24.96 17.256 24.984 ;
    END
  END do0[460]
  PIN do0[461]
    DIRECTION OUTPUT ;
    USE SIGNAL ;
    PORT
      LAYER M4 ;
        RECT  17.064 25.008 17.256 25.032 ;
    END
  END do0[461]
  PIN do0[462]
    DIRECTION OUTPUT ;
    USE SIGNAL ;
    PORT
      LAYER M4 ;
        RECT  17.064 25.056 17.256 25.08 ;
    END
  END do0[462]
  PIN do0[463]
    DIRECTION OUTPUT ;
    USE SIGNAL ;
    PORT
      LAYER M4 ;
        RECT  17.064 25.104 17.256 25.128 ;
    END
  END do0[463]
  PIN do0[464]
    DIRECTION OUTPUT ;
    USE SIGNAL ;
    PORT
      LAYER M4 ;
        RECT  17.064 25.152 17.256 25.176 ;
    END
  END do0[464]
  PIN do0[465]
    DIRECTION OUTPUT ;
    USE SIGNAL ;
    PORT
      LAYER M4 ;
        RECT  17.064 25.2 17.256 25.224 ;
    END
  END do0[465]
  PIN do0[466]
    DIRECTION OUTPUT ;
    USE SIGNAL ;
    PORT
      LAYER M4 ;
        RECT  17.064 25.248 17.256 25.272 ;
    END
  END do0[466]
  PIN do0[467]
    DIRECTION OUTPUT ;
    USE SIGNAL ;
    PORT
      LAYER M4 ;
        RECT  17.064 25.296 17.256 25.32 ;
    END
  END do0[467]
  PIN do0[468]
    DIRECTION OUTPUT ;
    USE SIGNAL ;
    PORT
      LAYER M4 ;
        RECT  17.064 25.344 17.256 25.368 ;
    END
  END do0[468]
  PIN do0[469]
    DIRECTION OUTPUT ;
    USE SIGNAL ;
    PORT
      LAYER M4 ;
        RECT  17.064 25.392 17.256 25.416 ;
    END
  END do0[469]
  PIN do0[46]
    DIRECTION OUTPUT ;
    USE SIGNAL ;
    PORT
      LAYER M4 ;
        RECT  17.064 5.088 17.256 5.112 ;
    END
  END do0[46]
  PIN do0[470]
    DIRECTION OUTPUT ;
    USE SIGNAL ;
    PORT
      LAYER M4 ;
        RECT  17.064 25.44 17.256 25.464 ;
    END
  END do0[470]
  PIN do0[471]
    DIRECTION OUTPUT ;
    USE SIGNAL ;
    PORT
      LAYER M4 ;
        RECT  17.064 25.488 17.256 25.512 ;
    END
  END do0[471]
  PIN do0[472]
    DIRECTION OUTPUT ;
    USE SIGNAL ;
    PORT
      LAYER M4 ;
        RECT  17.064 25.536 17.256 25.56 ;
    END
  END do0[472]
  PIN do0[473]
    DIRECTION OUTPUT ;
    USE SIGNAL ;
    PORT
      LAYER M4 ;
        RECT  17.064 25.584 17.256 25.608 ;
    END
  END do0[473]
  PIN do0[474]
    DIRECTION OUTPUT ;
    USE SIGNAL ;
    PORT
      LAYER M4 ;
        RECT  17.064 25.632 17.256 25.656 ;
    END
  END do0[474]
  PIN do0[475]
    DIRECTION OUTPUT ;
    USE SIGNAL ;
    PORT
      LAYER M4 ;
        RECT  17.064 25.68 17.256 25.704 ;
    END
  END do0[475]
  PIN do0[476]
    DIRECTION OUTPUT ;
    USE SIGNAL ;
    PORT
      LAYER M4 ;
        RECT  17.064 25.728 17.256 25.752 ;
    END
  END do0[476]
  PIN do0[477]
    DIRECTION OUTPUT ;
    USE SIGNAL ;
    PORT
      LAYER M4 ;
        RECT  17.064 25.776 17.256 25.8 ;
    END
  END do0[477]
  PIN do0[478]
    DIRECTION OUTPUT ;
    USE SIGNAL ;
    PORT
      LAYER M4 ;
        RECT  17.064 25.824 17.256 25.848 ;
    END
  END do0[478]
  PIN do0[479]
    DIRECTION OUTPUT ;
    USE SIGNAL ;
    PORT
      LAYER M4 ;
        RECT  17.064 25.872 17.256 25.896 ;
    END
  END do0[479]
  PIN do0[47]
    DIRECTION OUTPUT ;
    USE SIGNAL ;
    PORT
      LAYER M4 ;
        RECT  17.064 5.136 17.256 5.16 ;
    END
  END do0[47]
  PIN do0[480]
    DIRECTION OUTPUT ;
    USE SIGNAL ;
    PORT
      LAYER M4 ;
        RECT  17.064 25.92 17.256 25.944 ;
    END
  END do0[480]
  PIN do0[481]
    DIRECTION OUTPUT ;
    USE SIGNAL ;
    PORT
      LAYER M4 ;
        RECT  17.064 25.968 17.256 25.992 ;
    END
  END do0[481]
  PIN do0[482]
    DIRECTION OUTPUT ;
    USE SIGNAL ;
    PORT
      LAYER M4 ;
        RECT  17.064 26.016 17.256 26.04 ;
    END
  END do0[482]
  PIN do0[483]
    DIRECTION OUTPUT ;
    USE SIGNAL ;
    PORT
      LAYER M4 ;
        RECT  17.064 26.064 17.256 26.088 ;
    END
  END do0[483]
  PIN do0[484]
    DIRECTION OUTPUT ;
    USE SIGNAL ;
    PORT
      LAYER M4 ;
        RECT  17.064 26.112 17.256 26.136 ;
    END
  END do0[484]
  PIN do0[485]
    DIRECTION OUTPUT ;
    USE SIGNAL ;
    PORT
      LAYER M4 ;
        RECT  17.064 26.16 17.256 26.184 ;
    END
  END do0[485]
  PIN do0[486]
    DIRECTION OUTPUT ;
    USE SIGNAL ;
    PORT
      LAYER M4 ;
        RECT  17.064 26.208 17.256 26.232 ;
    END
  END do0[486]
  PIN do0[487]
    DIRECTION OUTPUT ;
    USE SIGNAL ;
    PORT
      LAYER M4 ;
        RECT  17.064 26.256 17.256 26.28 ;
    END
  END do0[487]
  PIN do0[488]
    DIRECTION OUTPUT ;
    USE SIGNAL ;
    PORT
      LAYER M4 ;
        RECT  17.064 26.304 17.256 26.328 ;
    END
  END do0[488]
  PIN do0[489]
    DIRECTION OUTPUT ;
    USE SIGNAL ;
    PORT
      LAYER M4 ;
        RECT  17.064 26.352 17.256 26.376 ;
    END
  END do0[489]
  PIN do0[48]
    DIRECTION OUTPUT ;
    USE SIGNAL ;
    PORT
      LAYER M4 ;
        RECT  17.064 5.184 17.256 5.208 ;
    END
  END do0[48]
  PIN do0[490]
    DIRECTION OUTPUT ;
    USE SIGNAL ;
    PORT
      LAYER M4 ;
        RECT  17.064 26.4 17.256 26.424 ;
    END
  END do0[490]
  PIN do0[491]
    DIRECTION OUTPUT ;
    USE SIGNAL ;
    PORT
      LAYER M4 ;
        RECT  17.064 26.448 17.256 26.472 ;
    END
  END do0[491]
  PIN do0[492]
    DIRECTION OUTPUT ;
    USE SIGNAL ;
    PORT
      LAYER M4 ;
        RECT  17.064 26.496 17.256 26.52 ;
    END
  END do0[492]
  PIN do0[493]
    DIRECTION OUTPUT ;
    USE SIGNAL ;
    PORT
      LAYER M4 ;
        RECT  17.064 26.544 17.256 26.568 ;
    END
  END do0[493]
  PIN do0[494]
    DIRECTION OUTPUT ;
    USE SIGNAL ;
    PORT
      LAYER M4 ;
        RECT  17.064 26.592 17.256 26.616 ;
    END
  END do0[494]
  PIN do0[495]
    DIRECTION OUTPUT ;
    USE SIGNAL ;
    PORT
      LAYER M4 ;
        RECT  17.064 26.64 17.256 26.664 ;
    END
  END do0[495]
  PIN do0[496]
    DIRECTION OUTPUT ;
    USE SIGNAL ;
    PORT
      LAYER M4 ;
        RECT  17.064 26.688 17.256 26.712 ;
    END
  END do0[496]
  PIN do0[497]
    DIRECTION OUTPUT ;
    USE SIGNAL ;
    PORT
      LAYER M4 ;
        RECT  17.064 26.736 17.256 26.76 ;
    END
  END do0[497]
  PIN do0[498]
    DIRECTION OUTPUT ;
    USE SIGNAL ;
    PORT
      LAYER M4 ;
        RECT  17.064 26.784 17.256 26.808 ;
    END
  END do0[498]
  PIN do0[499]
    DIRECTION OUTPUT ;
    USE SIGNAL ;
    PORT
      LAYER M4 ;
        RECT  17.064 26.832 17.256 26.856 ;
    END
  END do0[499]
  PIN do0[49]
    DIRECTION OUTPUT ;
    USE SIGNAL ;
    PORT
      LAYER M4 ;
        RECT  17.064 5.232 17.256 5.256 ;
    END
  END do0[49]
  PIN do0[4]
    DIRECTION OUTPUT ;
    USE SIGNAL ;
    PORT
      LAYER M4 ;
        RECT  17.064 3.072 17.256 3.096 ;
    END
  END do0[4]
  PIN do0[500]
    DIRECTION OUTPUT ;
    USE SIGNAL ;
    PORT
      LAYER M4 ;
        RECT  17.064 26.88 17.256 26.904 ;
    END
  END do0[500]
  PIN do0[501]
    DIRECTION OUTPUT ;
    USE SIGNAL ;
    PORT
      LAYER M4 ;
        RECT  17.064 26.928 17.256 26.952 ;
    END
  END do0[501]
  PIN do0[502]
    DIRECTION OUTPUT ;
    USE SIGNAL ;
    PORT
      LAYER M4 ;
        RECT  17.064 26.976 17.256 27 ;
    END
  END do0[502]
  PIN do0[503]
    DIRECTION OUTPUT ;
    USE SIGNAL ;
    PORT
      LAYER M4 ;
        RECT  17.064 27.024 17.256 27.048 ;
    END
  END do0[503]
  PIN do0[504]
    DIRECTION OUTPUT ;
    USE SIGNAL ;
    PORT
      LAYER M4 ;
        RECT  17.064 27.072 17.256 27.096 ;
    END
  END do0[504]
  PIN do0[505]
    DIRECTION OUTPUT ;
    USE SIGNAL ;
    PORT
      LAYER M4 ;
        RECT  17.064 27.12 17.256 27.144 ;
    END
  END do0[505]
  PIN do0[506]
    DIRECTION OUTPUT ;
    USE SIGNAL ;
    PORT
      LAYER M4 ;
        RECT  17.064 27.168 17.256 27.192 ;
    END
  END do0[506]
  PIN do0[507]
    DIRECTION OUTPUT ;
    USE SIGNAL ;
    PORT
      LAYER M4 ;
        RECT  17.064 27.216 17.256 27.24 ;
    END
  END do0[507]
  PIN do0[508]
    DIRECTION OUTPUT ;
    USE SIGNAL ;
    PORT
      LAYER M4 ;
        RECT  17.064 27.264 17.256 27.288 ;
    END
  END do0[508]
  PIN do0[509]
    DIRECTION OUTPUT ;
    USE SIGNAL ;
    PORT
      LAYER M4 ;
        RECT  17.064 27.312 17.256 27.336 ;
    END
  END do0[509]
  PIN do0[50]
    DIRECTION OUTPUT ;
    USE SIGNAL ;
    PORT
      LAYER M4 ;
        RECT  17.064 5.28 17.256 5.304 ;
    END
  END do0[50]
  PIN do0[510]
    DIRECTION OUTPUT ;
    USE SIGNAL ;
    PORT
      LAYER M4 ;
        RECT  17.064 27.36 17.256 27.384 ;
    END
  END do0[510]
  PIN do0[511]
    DIRECTION OUTPUT ;
    USE SIGNAL ;
    PORT
      LAYER M4 ;
        RECT  17.064 27.408 17.256 27.432 ;
    END
  END do0[511]
  PIN do0[512]
    DIRECTION OUTPUT ;
    USE SIGNAL ;
    PORT
      LAYER M4 ;
        RECT  17.064 27.456 17.256 27.48 ;
    END
  END do0[512]
  PIN do0[513]
    DIRECTION OUTPUT ;
    USE SIGNAL ;
    PORT
      LAYER M4 ;
        RECT  17.064 27.504 17.256 27.528 ;
    END
  END do0[513]
  PIN do0[51]
    DIRECTION OUTPUT ;
    USE SIGNAL ;
    PORT
      LAYER M4 ;
        RECT  17.064 5.328 17.256 5.352 ;
    END
  END do0[51]
  PIN do0[52]
    DIRECTION OUTPUT ;
    USE SIGNAL ;
    PORT
      LAYER M4 ;
        RECT  17.064 5.376 17.256 5.4 ;
    END
  END do0[52]
  PIN do0[53]
    DIRECTION OUTPUT ;
    USE SIGNAL ;
    PORT
      LAYER M4 ;
        RECT  17.064 5.424 17.256 5.448 ;
    END
  END do0[53]
  PIN do0[54]
    DIRECTION OUTPUT ;
    USE SIGNAL ;
    PORT
      LAYER M4 ;
        RECT  17.064 5.472 17.256 5.496 ;
    END
  END do0[54]
  PIN do0[55]
    DIRECTION OUTPUT ;
    USE SIGNAL ;
    PORT
      LAYER M4 ;
        RECT  17.064 5.52 17.256 5.544 ;
    END
  END do0[55]
  PIN do0[56]
    DIRECTION OUTPUT ;
    USE SIGNAL ;
    PORT
      LAYER M4 ;
        RECT  17.064 5.568 17.256 5.592 ;
    END
  END do0[56]
  PIN do0[57]
    DIRECTION OUTPUT ;
    USE SIGNAL ;
    PORT
      LAYER M4 ;
        RECT  17.064 5.616 17.256 5.64 ;
    END
  END do0[57]
  PIN do0[58]
    DIRECTION OUTPUT ;
    USE SIGNAL ;
    PORT
      LAYER M4 ;
        RECT  17.064 5.664 17.256 5.688 ;
    END
  END do0[58]
  PIN do0[59]
    DIRECTION OUTPUT ;
    USE SIGNAL ;
    PORT
      LAYER M4 ;
        RECT  17.064 5.712 17.256 5.736 ;
    END
  END do0[59]
  PIN do0[5]
    DIRECTION OUTPUT ;
    USE SIGNAL ;
    PORT
      LAYER M4 ;
        RECT  17.064 3.12 17.256 3.144 ;
    END
  END do0[5]
  PIN do0[60]
    DIRECTION OUTPUT ;
    USE SIGNAL ;
    PORT
      LAYER M4 ;
        RECT  17.064 5.76 17.256 5.784 ;
    END
  END do0[60]
  PIN do0[61]
    DIRECTION OUTPUT ;
    USE SIGNAL ;
    PORT
      LAYER M4 ;
        RECT  17.064 5.808 17.256 5.832 ;
    END
  END do0[61]
  PIN do0[62]
    DIRECTION OUTPUT ;
    USE SIGNAL ;
    PORT
      LAYER M4 ;
        RECT  17.064 5.856 17.256 5.88 ;
    END
  END do0[62]
  PIN do0[63]
    DIRECTION OUTPUT ;
    USE SIGNAL ;
    PORT
      LAYER M4 ;
        RECT  17.064 5.904 17.256 5.928 ;
    END
  END do0[63]
  PIN do0[64]
    DIRECTION OUTPUT ;
    USE SIGNAL ;
    PORT
      LAYER M4 ;
        RECT  17.064 5.952 17.256 5.976 ;
    END
  END do0[64]
  PIN do0[65]
    DIRECTION OUTPUT ;
    USE SIGNAL ;
    PORT
      LAYER M4 ;
        RECT  17.064 6 17.256 6.024 ;
    END
  END do0[65]
  PIN do0[66]
    DIRECTION OUTPUT ;
    USE SIGNAL ;
    PORT
      LAYER M4 ;
        RECT  17.064 6.048 17.256 6.072 ;
    END
  END do0[66]
  PIN do0[67]
    DIRECTION OUTPUT ;
    USE SIGNAL ;
    PORT
      LAYER M4 ;
        RECT  17.064 6.096 17.256 6.12 ;
    END
  END do0[67]
  PIN do0[68]
    DIRECTION OUTPUT ;
    USE SIGNAL ;
    PORT
      LAYER M4 ;
        RECT  17.064 6.144 17.256 6.168 ;
    END
  END do0[68]
  PIN do0[69]
    DIRECTION OUTPUT ;
    USE SIGNAL ;
    PORT
      LAYER M4 ;
        RECT  17.064 6.192 17.256 6.216 ;
    END
  END do0[69]
  PIN do0[6]
    DIRECTION OUTPUT ;
    USE SIGNAL ;
    PORT
      LAYER M4 ;
        RECT  17.064 3.168 17.256 3.192 ;
    END
  END do0[6]
  PIN do0[70]
    DIRECTION OUTPUT ;
    USE SIGNAL ;
    PORT
      LAYER M4 ;
        RECT  17.064 6.24 17.256 6.264 ;
    END
  END do0[70]
  PIN do0[71]
    DIRECTION OUTPUT ;
    USE SIGNAL ;
    PORT
      LAYER M4 ;
        RECT  17.064 6.288 17.256 6.312 ;
    END
  END do0[71]
  PIN do0[72]
    DIRECTION OUTPUT ;
    USE SIGNAL ;
    PORT
      LAYER M4 ;
        RECT  17.064 6.336 17.256 6.36 ;
    END
  END do0[72]
  PIN do0[73]
    DIRECTION OUTPUT ;
    USE SIGNAL ;
    PORT
      LAYER M4 ;
        RECT  17.064 6.384 17.256 6.408 ;
    END
  END do0[73]
  PIN do0[74]
    DIRECTION OUTPUT ;
    USE SIGNAL ;
    PORT
      LAYER M4 ;
        RECT  17.064 6.432 17.256 6.456 ;
    END
  END do0[74]
  PIN do0[75]
    DIRECTION OUTPUT ;
    USE SIGNAL ;
    PORT
      LAYER M4 ;
        RECT  17.064 6.48 17.256 6.504 ;
    END
  END do0[75]
  PIN do0[76]
    DIRECTION OUTPUT ;
    USE SIGNAL ;
    PORT
      LAYER M4 ;
        RECT  17.064 6.528 17.256 6.552 ;
    END
  END do0[76]
  PIN do0[77]
    DIRECTION OUTPUT ;
    USE SIGNAL ;
    PORT
      LAYER M4 ;
        RECT  17.064 6.576 17.256 6.6 ;
    END
  END do0[77]
  PIN do0[78]
    DIRECTION OUTPUT ;
    USE SIGNAL ;
    PORT
      LAYER M4 ;
        RECT  17.064 6.624 17.256 6.648 ;
    END
  END do0[78]
  PIN do0[79]
    DIRECTION OUTPUT ;
    USE SIGNAL ;
    PORT
      LAYER M4 ;
        RECT  17.064 6.672 17.256 6.696 ;
    END
  END do0[79]
  PIN do0[7]
    DIRECTION OUTPUT ;
    USE SIGNAL ;
    PORT
      LAYER M4 ;
        RECT  17.064 3.216 17.256 3.24 ;
    END
  END do0[7]
  PIN do0[80]
    DIRECTION OUTPUT ;
    USE SIGNAL ;
    PORT
      LAYER M4 ;
        RECT  17.064 6.72 17.256 6.744 ;
    END
  END do0[80]
  PIN do0[81]
    DIRECTION OUTPUT ;
    USE SIGNAL ;
    PORT
      LAYER M4 ;
        RECT  17.064 6.768 17.256 6.792 ;
    END
  END do0[81]
  PIN do0[82]
    DIRECTION OUTPUT ;
    USE SIGNAL ;
    PORT
      LAYER M4 ;
        RECT  17.064 6.816 17.256 6.84 ;
    END
  END do0[82]
  PIN do0[83]
    DIRECTION OUTPUT ;
    USE SIGNAL ;
    PORT
      LAYER M4 ;
        RECT  17.064 6.864 17.256 6.888 ;
    END
  END do0[83]
  PIN do0[84]
    DIRECTION OUTPUT ;
    USE SIGNAL ;
    PORT
      LAYER M4 ;
        RECT  17.064 6.912 17.256 6.936 ;
    END
  END do0[84]
  PIN do0[85]
    DIRECTION OUTPUT ;
    USE SIGNAL ;
    PORT
      LAYER M4 ;
        RECT  17.064 6.96 17.256 6.984 ;
    END
  END do0[85]
  PIN do0[86]
    DIRECTION OUTPUT ;
    USE SIGNAL ;
    PORT
      LAYER M4 ;
        RECT  17.064 7.008 17.256 7.032 ;
    END
  END do0[86]
  PIN do0[87]
    DIRECTION OUTPUT ;
    USE SIGNAL ;
    PORT
      LAYER M4 ;
        RECT  17.064 7.056 17.256 7.08 ;
    END
  END do0[87]
  PIN do0[88]
    DIRECTION OUTPUT ;
    USE SIGNAL ;
    PORT
      LAYER M4 ;
        RECT  17.064 7.104 17.256 7.128 ;
    END
  END do0[88]
  PIN do0[89]
    DIRECTION OUTPUT ;
    USE SIGNAL ;
    PORT
      LAYER M4 ;
        RECT  17.064 7.152 17.256 7.176 ;
    END
  END do0[89]
  PIN do0[8]
    DIRECTION OUTPUT ;
    USE SIGNAL ;
    PORT
      LAYER M4 ;
        RECT  17.064 3.264 17.256 3.288 ;
    END
  END do0[8]
  PIN do0[90]
    DIRECTION OUTPUT ;
    USE SIGNAL ;
    PORT
      LAYER M4 ;
        RECT  17.064 7.2 17.256 7.224 ;
    END
  END do0[90]
  PIN do0[91]
    DIRECTION OUTPUT ;
    USE SIGNAL ;
    PORT
      LAYER M4 ;
        RECT  17.064 7.248 17.256 7.272 ;
    END
  END do0[91]
  PIN do0[92]
    DIRECTION OUTPUT ;
    USE SIGNAL ;
    PORT
      LAYER M4 ;
        RECT  17.064 7.296 17.256 7.32 ;
    END
  END do0[92]
  PIN do0[93]
    DIRECTION OUTPUT ;
    USE SIGNAL ;
    PORT
      LAYER M4 ;
        RECT  17.064 7.344 17.256 7.368 ;
    END
  END do0[93]
  PIN do0[94]
    DIRECTION OUTPUT ;
    USE SIGNAL ;
    PORT
      LAYER M4 ;
        RECT  17.064 7.392 17.256 7.416 ;
    END
  END do0[94]
  PIN do0[95]
    DIRECTION OUTPUT ;
    USE SIGNAL ;
    PORT
      LAYER M4 ;
        RECT  17.064 7.44 17.256 7.464 ;
    END
  END do0[95]
  PIN do0[96]
    DIRECTION OUTPUT ;
    USE SIGNAL ;
    PORT
      LAYER M4 ;
        RECT  17.064 7.488 17.256 7.512 ;
    END
  END do0[96]
  PIN do0[97]
    DIRECTION OUTPUT ;
    USE SIGNAL ;
    PORT
      LAYER M4 ;
        RECT  17.064 7.536 17.256 7.56 ;
    END
  END do0[97]
  PIN do0[98]
    DIRECTION OUTPUT ;
    USE SIGNAL ;
    PORT
      LAYER M4 ;
        RECT  17.064 7.584 17.256 7.608 ;
    END
  END do0[98]
  PIN do0[99]
    DIRECTION OUTPUT ;
    USE SIGNAL ;
    PORT
      LAYER M4 ;
        RECT  17.064 7.632 17.256 7.656 ;
    END
  END do0[99]
  PIN do0[9]
    DIRECTION OUTPUT ;
    USE SIGNAL ;
    PORT
      LAYER M4 ;
        RECT  17.064 3.312 17.256 3.336 ;
    END
  END do0[9]
  PIN fi0[0]
    DIRECTION INPUT ;
    USE SIGNAL ;
    PORT
      LAYER M4 ;
        RECT  0 2.688 0.192 2.712 ;
    END
  END fi0[0]
  PIN fo0[0]
    DIRECTION OUTPUT ;
    USE SIGNAL ;
    PORT
      LAYER M4 ;
        RECT  17.064 2.688 17.256 2.712 ;
    END
  END fo0[0]
  PIN VDD
    DIRECTION INOUT ;
    USE POWER ;
    PORT
      LAYER M7 ;
        RECT  6.256 0.531 6.544 29.439 ;
      LAYER M6 ;
        RECT  0 28.572 0.032 28.86 ;
        RECT  0 23.172 0.032 23.46 ;
        RECT  0 17.772 0.032 18.06 ;
        RECT  0 12.372 0.032 12.66 ;
        RECT  0 6.972 0.032 7.26 ;
        RECT  0 1.572 0.032 1.86 ;
      LAYER M2 ;
        RECT  0 29.421 0.018 29.439 ;
        RECT  0 28.881 0.018 28.899 ;
        RECT  0 28.341 0.018 28.359 ;
        RECT  0 27.801 0.018 27.819 ;
        RECT  0 27.261 0.018 27.279 ;
        RECT  0 26.721 0.018 26.739 ;
        RECT  0 26.181 0.018 26.199 ;
        RECT  0 25.641 0.018 25.659 ;
        RECT  0 25.101 0.018 25.119 ;
        RECT  0 24.561 0.018 24.579 ;
        RECT  0 24.021 0.018 24.039 ;
        RECT  0 23.481 0.018 23.499 ;
        RECT  0 22.941 0.018 22.959 ;
        RECT  0 22.401 0.018 22.419 ;
        RECT  0 21.861 0.018 21.879 ;
        RECT  0 21.321 0.018 21.339 ;
        RECT  0 20.781 0.018 20.799 ;
        RECT  0 20.241 0.018 20.259 ;
        RECT  0 19.701 0.018 19.719 ;
        RECT  0 19.161 0.018 19.179 ;
        RECT  0 18.621 0.018 18.639 ;
        RECT  0 18.081 0.018 18.099 ;
        RECT  0 17.541 0.018 17.559 ;
        RECT  0 17.001 0.018 17.019 ;
        RECT  0 16.461 0.018 16.479 ;
        RECT  0 15.921 0.018 15.939 ;
        RECT  0 15.381 0.018 15.399 ;
        RECT  0 14.841 0.018 14.859 ;
        RECT  0 14.301 0.018 14.319 ;
        RECT  0 13.761 0.018 13.779 ;
        RECT  0 13.221 0.018 13.239 ;
        RECT  0 12.681 0.018 12.699 ;
        RECT  0 12.141 0.018 12.159 ;
        RECT  0 11.601 0.018 11.619 ;
        RECT  0 11.061 0.018 11.079 ;
        RECT  0 10.521 0.018 10.539 ;
        RECT  0 9.981 0.018 9.999 ;
        RECT  0 9.441 0.018 9.459 ;
        RECT  0 8.901 0.018 8.919 ;
        RECT  0 8.361 0.018 8.379 ;
        RECT  0 7.821 0.018 7.839 ;
        RECT  0 7.281 0.018 7.299 ;
        RECT  0 6.741 0.018 6.759 ;
        RECT  0 6.201 0.018 6.219 ;
        RECT  0 5.661 0.018 5.679 ;
        RECT  0 5.121 0.018 5.139 ;
        RECT  0 4.581 0.018 4.599 ;
        RECT  0 4.041 0.018 4.059 ;
        RECT  0 3.501 0.018 3.519 ;
        RECT  0 2.961 0.018 2.979 ;
        RECT  0 2.421 0.018 2.439 ;
        RECT  0 1.881 0.018 1.899 ;
        RECT  0 1.341 0.018 1.359 ;
        RECT  0 0.801 0.018 0.819 ;
      LAYER M1 ;
        RECT  0 29.421 0.018 29.439 ;
        RECT  0 28.881 0.018 28.899 ;
        RECT  0 28.341 0.018 28.359 ;
        RECT  0 27.801 0.018 27.819 ;
        RECT  0 27.261 0.018 27.279 ;
        RECT  0 26.721 0.018 26.739 ;
        RECT  0 26.181 0.018 26.199 ;
        RECT  0 25.641 0.018 25.659 ;
        RECT  0 25.101 0.018 25.119 ;
        RECT  0 24.561 0.018 24.579 ;
        RECT  0 24.021 0.018 24.039 ;
        RECT  0 23.481 0.018 23.499 ;
        RECT  0 22.941 0.018 22.959 ;
        RECT  0 22.401 0.018 22.419 ;
        RECT  0 21.861 0.018 21.879 ;
        RECT  0 21.321 0.018 21.339 ;
        RECT  0 20.781 0.018 20.799 ;
        RECT  0 20.241 0.018 20.259 ;
        RECT  0 19.701 0.018 19.719 ;
        RECT  0 19.161 0.018 19.179 ;
        RECT  0 18.621 0.018 18.639 ;
        RECT  0 18.081 0.018 18.099 ;
        RECT  0 17.541 0.018 17.559 ;
        RECT  0 17.001 0.018 17.019 ;
        RECT  0 16.461 0.018 16.479 ;
        RECT  0 15.921 0.018 15.939 ;
        RECT  0 15.381 0.018 15.399 ;
        RECT  0 14.841 0.018 14.859 ;
        RECT  0 14.301 0.018 14.319 ;
        RECT  0 13.761 0.018 13.779 ;
        RECT  0 13.221 0.018 13.239 ;
        RECT  0 12.681 0.018 12.699 ;
        RECT  0 12.141 0.018 12.159 ;
        RECT  0 11.601 0.018 11.619 ;
        RECT  0 11.061 0.018 11.079 ;
        RECT  0 10.521 0.018 10.539 ;
        RECT  0 9.981 0.018 9.999 ;
        RECT  0 9.441 0.018 9.459 ;
        RECT  0 8.901 0.018 8.919 ;
        RECT  0 8.361 0.018 8.379 ;
        RECT  0 7.821 0.018 7.839 ;
        RECT  0 7.281 0.018 7.299 ;
        RECT  0 6.741 0.018 6.759 ;
        RECT  0 6.201 0.018 6.219 ;
        RECT  0 5.661 0.018 5.679 ;
        RECT  0 5.121 0.018 5.139 ;
        RECT  0 4.581 0.018 4.599 ;
        RECT  0 4.041 0.018 4.059 ;
        RECT  0 3.501 0.018 3.519 ;
        RECT  0 2.961 0.018 2.979 ;
        RECT  0 2.421 0.018 2.439 ;
        RECT  0 1.881 0.018 1.899 ;
        RECT  0 1.341 0.018 1.359 ;
        RECT  0 0.801 0.018 0.819 ;
    END
  END VDD
  PIN VSS
    DIRECTION INOUT ;
    USE GROUND ;
    PORT
      LAYER M7 ;
        RECT  11.656 0.531 11.944 29.439 ;
        RECT  0.856 0.531 1.144 29.439 ;
      LAYER M6 ;
        RECT  0 27.996 0.032 28.284 ;
        RECT  0 22.596 0.032 22.884 ;
        RECT  0 17.196 0.032 17.484 ;
        RECT  0 11.796 0.032 12.084 ;
        RECT  0 6.396 0.032 6.684 ;
        RECT  0 0.996 0.032 1.284 ;
      LAYER M2 ;
        RECT  0 29.151 0.018 29.169 ;
        RECT  0 28.611 0.018 28.629 ;
        RECT  0 28.071 0.018 28.089 ;
        RECT  0 27.531 0.018 27.549 ;
        RECT  0 26.991 0.018 27.009 ;
        RECT  0 26.451 0.018 26.469 ;
        RECT  0 25.911 0.018 25.929 ;
        RECT  0 25.371 0.018 25.389 ;
        RECT  0 24.831 0.018 24.849 ;
        RECT  0 24.291 0.018 24.309 ;
        RECT  0 23.751 0.018 23.769 ;
        RECT  0 23.211 0.018 23.229 ;
        RECT  0 22.671 0.018 22.689 ;
        RECT  0 22.131 0.018 22.149 ;
        RECT  0 21.591 0.018 21.609 ;
        RECT  0 21.051 0.018 21.069 ;
        RECT  0 20.511 0.018 20.529 ;
        RECT  0 19.971 0.018 19.989 ;
        RECT  0 19.431 0.018 19.449 ;
        RECT  0 18.891 0.018 18.909 ;
        RECT  0 18.351 0.018 18.369 ;
        RECT  0 17.811 0.018 17.829 ;
        RECT  0 17.271 0.018 17.289 ;
        RECT  0 16.731 0.018 16.749 ;
        RECT  0 16.191 0.018 16.209 ;
        RECT  0 15.651 0.018 15.669 ;
        RECT  0 15.111 0.018 15.129 ;
        RECT  0 14.571 0.018 14.589 ;
        RECT  0 14.031 0.018 14.049 ;
        RECT  0 13.491 0.018 13.509 ;
        RECT  0 12.951 0.018 12.969 ;
        RECT  0 12.411 0.018 12.429 ;
        RECT  0 11.871 0.018 11.889 ;
        RECT  0 11.331 0.018 11.349 ;
        RECT  0 10.791 0.018 10.809 ;
        RECT  0 10.251 0.018 10.269 ;
        RECT  0 9.711 0.018 9.729 ;
        RECT  0 9.171 0.018 9.189 ;
        RECT  0 8.631 0.018 8.649 ;
        RECT  0 8.091 0.018 8.109 ;
        RECT  0 7.551 0.018 7.569 ;
        RECT  0 7.011 0.018 7.029 ;
        RECT  0 6.471 0.018 6.489 ;
        RECT  0 5.931 0.018 5.949 ;
        RECT  0 5.391 0.018 5.409 ;
        RECT  0 4.851 0.018 4.869 ;
        RECT  0 4.311 0.018 4.329 ;
        RECT  0 3.771 0.018 3.789 ;
        RECT  0 3.231 0.018 3.249 ;
        RECT  0 2.691 0.018 2.709 ;
        RECT  0 2.151 0.018 2.169 ;
        RECT  0 1.611 0.018 1.629 ;
        RECT  0 1.071 0.018 1.089 ;
        RECT  0 0.531 0.018 0.549 ;
      LAYER M1 ;
        RECT  0 29.151 0.018 29.169 ;
        RECT  0 28.611 0.018 28.629 ;
        RECT  0 28.071 0.018 28.089 ;
        RECT  0 27.531 0.018 27.549 ;
        RECT  0 26.991 0.018 27.009 ;
        RECT  0 26.451 0.018 26.469 ;
        RECT  0 25.911 0.018 25.929 ;
        RECT  0 25.371 0.018 25.389 ;
        RECT  0 24.831 0.018 24.849 ;
        RECT  0 24.291 0.018 24.309 ;
        RECT  0 23.751 0.018 23.769 ;
        RECT  0 23.211 0.018 23.229 ;
        RECT  0 22.671 0.018 22.689 ;
        RECT  0 22.131 0.018 22.149 ;
        RECT  0 21.591 0.018 21.609 ;
        RECT  0 21.051 0.018 21.069 ;
        RECT  0 20.511 0.018 20.529 ;
        RECT  0 19.971 0.018 19.989 ;
        RECT  0 19.431 0.018 19.449 ;
        RECT  0 18.891 0.018 18.909 ;
        RECT  0 18.351 0.018 18.369 ;
        RECT  0 17.811 0.018 17.829 ;
        RECT  0 17.271 0.018 17.289 ;
        RECT  0 16.731 0.018 16.749 ;
        RECT  0 16.191 0.018 16.209 ;
        RECT  0 15.651 0.018 15.669 ;
        RECT  0 15.111 0.018 15.129 ;
        RECT  0 14.571 0.018 14.589 ;
        RECT  0 14.031 0.018 14.049 ;
        RECT  0 13.491 0.018 13.509 ;
        RECT  0 12.951 0.018 12.969 ;
        RECT  0 12.411 0.018 12.429 ;
        RECT  0 11.871 0.018 11.889 ;
        RECT  0 11.331 0.018 11.349 ;
        RECT  0 10.791 0.018 10.809 ;
        RECT  0 10.251 0.018 10.269 ;
        RECT  0 9.711 0.018 9.729 ;
        RECT  0 9.171 0.018 9.189 ;
        RECT  0 8.631 0.018 8.649 ;
        RECT  0 8.091 0.018 8.109 ;
        RECT  0 7.551 0.018 7.569 ;
        RECT  0 7.011 0.018 7.029 ;
        RECT  0 6.471 0.018 6.489 ;
        RECT  0 5.931 0.018 5.949 ;
        RECT  0 5.391 0.018 5.409 ;
        RECT  0 4.851 0.018 4.869 ;
        RECT  0 4.311 0.018 4.329 ;
        RECT  0 3.771 0.018 3.789 ;
        RECT  0 3.231 0.018 3.249 ;
        RECT  0 2.691 0.018 2.709 ;
        RECT  0 2.151 0.018 2.169 ;
        RECT  0 1.611 0.018 1.629 ;
        RECT  0 1.071 0.018 1.089 ;
        RECT  0 0.531 0.018 0.549 ;
    END
  END VSS
  OBS
    LAYER RVTN ;
     RECT  0 0.54 17.226 0.675 ;
     RECT  0 0.945 17.226 1.215 ;
     RECT  0 1.485 17.226 1.755 ;
     RECT  0 2.025 17.226 2.295 ;
     RECT  0 2.565 17.226 2.835 ;
     RECT  0 3.105 17.226 3.375 ;
     RECT  0 3.645 17.226 3.915 ;
     RECT  0 4.185 17.226 4.455 ;
     RECT  0 4.725 17.226 4.995 ;
     RECT  0 5.265 17.226 5.535 ;
     RECT  0 5.805 17.226 6.075 ;
     RECT  0 6.345 17.226 6.615 ;
     RECT  0 6.885 17.226 7.155 ;
     RECT  0 7.425 17.226 7.695 ;
     RECT  0 7.965 17.226 8.235 ;
     RECT  0 8.505 17.226 8.775 ;
     RECT  0 9.045 17.226 9.315 ;
     RECT  0 9.585 17.226 9.855 ;
     RECT  0 10.125 17.226 10.395 ;
     RECT  0 10.665 17.226 10.935 ;
     RECT  0 11.205 17.226 11.475 ;
     RECT  0 11.745 17.226 12.015 ;
     RECT  0 12.285 17.226 12.555 ;
     RECT  0 12.825 17.226 13.095 ;
     RECT  0 13.365 17.226 13.635 ;
     RECT  0 13.905 17.226 14.175 ;
     RECT  0 14.445 17.226 14.715 ;
     RECT  0 14.985 17.226 15.255 ;
     RECT  0 15.525 17.226 15.795 ;
     RECT  0 16.065 17.226 16.335 ;
     RECT  0 16.605 17.226 16.875 ;
     RECT  0 17.145 17.226 17.415 ;
     RECT  0 17.685 17.226 17.955 ;
     RECT  0 18.225 17.226 18.495 ;
     RECT  0 18.765 17.226 19.035 ;
     RECT  0 19.305 17.226 19.575 ;
     RECT  0 19.845 17.226 20.115 ;
     RECT  0 20.385 17.226 20.655 ;
     RECT  0 20.925 17.226 21.195 ;
     RECT  0 21.465 17.226 21.735 ;
     RECT  0 22.005 17.226 22.275 ;
     RECT  0 22.545 17.226 22.815 ;
     RECT  0 23.085 17.226 23.355 ;
     RECT  0 23.625 17.226 23.895 ;
     RECT  0 24.165 17.226 24.435 ;
     RECT  0 24.705 17.226 24.975 ;
     RECT  0 25.245 17.226 25.515 ;
     RECT  0 25.785 17.226 26.055 ;
     RECT  0 26.325 17.226 26.595 ;
     RECT  0 26.865 17.226 27.135 ;
     RECT  0 27.405 17.226 27.675 ;
     RECT  0 27.945 17.226 28.215 ;
     RECT  0 28.485 17.226 28.755 ;
     RECT  0 29.025 17.226 29.295 ;
    LAYER RVTP ;
     RECT  0 0.675 17.226 0.945 ;
     RECT  0 1.215 17.226 1.485 ;
     RECT  0 1.755 17.226 2.025 ;
     RECT  0 2.295 17.226 2.565 ;
     RECT  0 2.835 17.226 3.105 ;
     RECT  0 3.375 17.226 3.645 ;
     RECT  0 3.915 17.226 4.185 ;
     RECT  0 4.455 17.226 4.725 ;
     RECT  0 4.995 17.226 5.265 ;
     RECT  0 5.535 17.226 5.805 ;
     RECT  0 6.075 17.226 6.345 ;
     RECT  0 6.615 17.226 6.885 ;
     RECT  0 7.155 17.226 7.425 ;
     RECT  0 7.695 17.226 7.965 ;
     RECT  0 8.235 17.226 8.505 ;
     RECT  0 8.775 17.226 9.045 ;
     RECT  0 9.315 17.226 9.585 ;
     RECT  0 9.855 17.226 10.125 ;
     RECT  0 10.395 17.226 10.665 ;
     RECT  0 10.935 17.226 11.205 ;
     RECT  0 11.475 17.226 11.745 ;
     RECT  0 12.015 17.226 12.285 ;
     RECT  0 12.555 17.226 12.825 ;
     RECT  0 13.095 17.226 13.365 ;
     RECT  0 13.635 17.226 13.905 ;
     RECT  0 14.175 17.226 14.445 ;
     RECT  0 14.715 17.226 14.985 ;
     RECT  0 15.255 17.226 15.525 ;
     RECT  0 15.795 17.226 16.065 ;
     RECT  0 16.335 17.226 16.605 ;
     RECT  0 16.875 17.226 17.145 ;
     RECT  0 17.415 17.226 17.685 ;
     RECT  0 17.955 17.226 18.225 ;
     RECT  0 18.495 17.226 18.765 ;
     RECT  0 19.035 17.226 19.305 ;
     RECT  0 19.575 17.226 19.845 ;
     RECT  0 20.115 17.226 20.385 ;
     RECT  0 20.655 17.226 20.925 ;
     RECT  0 21.195 17.226 21.465 ;
     RECT  0 21.735 17.226 22.005 ;
     RECT  0 22.275 17.226 22.545 ;
     RECT  0 22.815 17.226 23.085 ;
     RECT  0 23.355 17.226 23.625 ;
     RECT  0 23.895 17.226 24.165 ;
     RECT  0 24.435 17.226 24.705 ;
     RECT  0 24.975 17.226 25.245 ;
     RECT  0 25.515 17.226 25.785 ;
     RECT  0 26.055 17.226 26.325 ;
     RECT  0 26.595 17.226 26.865 ;
     RECT  0 27.135 17.226 27.405 ;
     RECT  0 27.675 17.226 27.945 ;
     RECT  0 28.215 17.226 28.485 ;
     RECT  0 28.755 17.226 29.025 ;
     RECT  0 29.295 17.226 29.43 ;
    LAYER M1 ;
     RECT  0 0.531 17.226 29.439 ;
    LAYER M2 ;
     RECT  0 0.531 17.226 29.439 ;
    LAYER M3 ;
     RECT  0.255 0.523 0.345 0.793 ;
     RECT  5.655 0.523 5.745 0.793 ;
     RECT  11.055 0.523 11.145 0.793 ;
     RECT  16.455 0.523 16.545 0.793 ;
     RECT  11.055 0.793 11.337 1.831 ;
     RECT  3.096 1.831 3.114 1.921 ;
     RECT  5.655 0.793 5.937 1.957 ;
     RECT  10.98 1.831 11.337 1.957 ;
     RECT  5.655 1.957 6.678 1.993 ;
     RECT  15.444 1.957 15.462 2.029 ;
     RECT  5.655 1.993 6.858 2.065 ;
     RECT  0.255 0.793 0.537 2.101 ;
     RECT  1.728 1.687 2.358 2.101 ;
     RECT  3.096 1.921 3.438 2.101 ;
     RECT  15.372 2.029 15.462 2.101 ;
     RECT  16.455 0.793 16.737 2.101 ;
     RECT  0.255 2.101 3.546 2.191 ;
     RECT  5.655 2.065 7.398 2.191 ;
     RECT  8.64 2.065 8.658 2.191 ;
     RECT  10.98 1.957 12.222 2.191 ;
     RECT  15.048 2.101 15.462 2.191 ;
     RECT  16.455 2.101 16.902 2.191 ;
     RECT  4.428 2.065 4.446 2.203 ;
     RECT  5.616 2.191 7.65 2.203 ;
     RECT  4.428 2.203 7.65 2.227 ;
     RECT  14.256 2.065 14.274 2.299 ;
     RECT  0.255 2.191 3.69 2.371 ;
     RECT  4.428 2.227 7.722 2.371 ;
     RECT  8.64 2.191 9.018 2.371 ;
     RECT  8.64 2.371 9.306 2.443 ;
     RECT  8.64 2.443 9.378 2.461 ;
     RECT  10.26 2.191 12.222 2.461 ;
     RECT  15.048 2.191 16.902 2.461 ;
     RECT  0.255 2.371 7.722 2.497 ;
     RECT  8.64 2.461 12.222 2.497 ;
     RECT  0.255 2.497 12.222 2.587 ;
     RECT  0.108 2.587 12.222 2.605 ;
     RECT  13.572 2.299 14.274 2.605 ;
     RECT  15.048 2.461 17.046 2.605 ;
     RECT  13.572 2.605 17.046 2.641 ;
     RECT  0.108 2.605 12.402 2.683 ;
     RECT  0.036 2.683 12.402 2.867 ;
     RECT  10.332 2.867 12.402 2.911 ;
     RECT  13.572 2.641 17.118 2.911 ;
     RECT  10.332 2.911 12.582 3.001 ;
     RECT  13.32 2.911 17.118 3.001 ;
     RECT  0.036 2.867 9.486 3.299 ;
     RECT  10.332 3.001 17.118 3.685 ;
     RECT  0.036 3.299 8.982 3.875 ;
     RECT  10.008 3.685 17.118 3.917 ;
     RECT  10.116 3.917 17.118 4.109 ;
     RECT  10.152 4.109 17.118 4.181 ;
     RECT  0.036 3.875 6.03 4.301 ;
     RECT  6.84 3.875 8.982 4.351 ;
     RECT  6.84 4.351 9.306 4.379 ;
     RECT  8.568 4.379 9.306 4.415 ;
     RECT  5.58 4.301 6.03 4.765 ;
     RECT  6.84 4.379 7.542 4.765 ;
     RECT  10.152 4.181 16.974 4.843 ;
     RECT  8.748 4.415 9.306 5.131 ;
     RECT  10.044 4.843 16.974 5.131 ;
     RECT  5.58 4.765 7.542 5.161 ;
     RECT  8.748 5.131 16.974 5.161 ;
     RECT  5.58 5.161 17.046 5.261 ;
     RECT  0.036 4.301 4.806 5.269 ;
     RECT  5.58 5.261 9.306 5.269 ;
     RECT  10.044 5.261 17.046 5.597 ;
     RECT  0.036 5.269 9.306 5.981 ;
     RECT  7.632 5.981 9.306 6.151 ;
     RECT  10.044 5.597 16.974 6.151 ;
     RECT  7.632 6.151 16.974 6.889 ;
     RECT  7.596 6.889 16.974 7.223 ;
     RECT  0.036 5.981 6.858 7.231 ;
     RECT  0.036 7.231 7.47 7.969 ;
     RECT  8.316 7.223 16.974 7.969 ;
     RECT  0.036 7.969 16.974 8.429 ;
     RECT  8.64 8.429 16.974 8.537 ;
     RECT  8.748 8.537 16.974 8.909 ;
     RECT  0.036 8.429 7.758 9.239 ;
     RECT  8.82 8.909 16.974 9.391 ;
     RECT  2.268 9.239 7.758 9.419 ;
     RECT  8.82 9.391 17.046 9.419 ;
     RECT  8.82 9.419 9.198 9.653 ;
     RECT  4.824 9.419 7.758 9.691 ;
     RECT  8.82 9.653 9.162 9.691 ;
     RECT  9.972 9.419 17.046 9.815 ;
     RECT  0.036 9.239 1.494 9.851 ;
     RECT  10.188 9.815 17.046 10.049 ;
     RECT  4.824 9.691 9.162 10.061 ;
     RECT  10.26 10.049 17.046 10.121 ;
     RECT  0.144 9.851 1.494 10.165 ;
     RECT  2.268 9.419 3.978 10.165 ;
     RECT  0.144 10.165 3.978 10.171 ;
     RECT  4.824 10.061 9.126 10.171 ;
     RECT  10.8 10.121 17.046 10.391 ;
     RECT  10.8 10.391 17.01 10.637 ;
     RECT  10.8 10.637 16.974 10.661 ;
     RECT  0.144 10.171 9.126 10.795 ;
     RECT  0.036 10.795 9.126 10.831 ;
     RECT  0.036 10.831 9.63 10.843 ;
     RECT  10.8 10.661 11.538 10.867 ;
     RECT  0.036 10.843 9.702 11.011 ;
     RECT  10.584 10.867 11.538 11.011 ;
     RECT  0.036 11.011 11.538 11.611 ;
     RECT  12.276 10.661 16.974 11.611 ;
     RECT  0.036 11.611 16.974 11.939 ;
     RECT  0.036 11.939 12.402 11.981 ;
     RECT  13.248 11.939 16.974 12.289 ;
     RECT  13.248 12.289 17.046 12.353 ;
     RECT  14.508 12.353 17.046 12.389 ;
     RECT  14.508 12.389 17.01 12.479 ;
     RECT  7.92 11.981 12.402 12.763 ;
     RECT  13.248 12.353 13.77 12.763 ;
     RECT  7.92 12.763 13.77 13.019 ;
     RECT  0.036 11.981 7.182 13.135 ;
     RECT  7.992 13.019 13.77 13.135 ;
     RECT  0.036 13.135 7.254 13.181 ;
     RECT  0.036 13.181 7.182 13.199 ;
     RECT  14.652 12.479 17.01 13.325 ;
     RECT  7.992 13.135 13.806 13.369 ;
     RECT  14.652 13.325 16.974 13.369 ;
     RECT  7.992 13.369 16.974 13.421 ;
     RECT  7.992 13.421 13.986 14.059 ;
     RECT  7.956 14.059 13.986 14.099 ;
     RECT  0.036 13.199 7.11 14.107 ;
     RECT  7.956 14.099 13.878 14.107 ;
     RECT  0.036 14.107 13.878 14.243 ;
     RECT  14.796 13.421 16.974 14.521 ;
     RECT  14.724 14.521 16.974 14.827 ;
     RECT  13.428 14.243 13.878 14.953 ;
     RECT  14.652 14.827 16.974 14.953 ;
     RECT  0.036 14.243 12.69 14.971 ;
     RECT  13.428 14.953 16.974 14.971 ;
     RECT  0.036 14.971 16.974 15.017 ;
     RECT  0.036 15.017 11.337 15.179 ;
     RECT  12.06 15.017 16.974 15.187 ;
     RECT  12.06 15.187 17.046 15.533 ;
     RECT  12.06 15.533 16.974 15.827 ;
     RECT  12.06 15.827 12.762 16.061 ;
     RECT  0.036 15.179 2.898 16.105 ;
     RECT  3.672 15.179 11.337 16.105 ;
     RECT  0.036 16.105 2.934 16.141 ;
     RECT  3.672 16.105 11.754 16.141 ;
     RECT  12.492 16.061 12.762 16.555 ;
     RECT  13.5 15.827 16.974 16.555 ;
     RECT  12.492 16.555 16.974 16.637 ;
     RECT  12.492 16.637 16.938 16.799 ;
     RECT  0.036 16.141 11.754 16.835 ;
     RECT  8.532 16.835 11.754 16.951 ;
     RECT  12.492 16.799 14.094 16.951 ;
     RECT  8.532 16.951 14.094 17.069 ;
     RECT  14.832 16.799 16.938 17.419 ;
     RECT  14.832 17.419 16.974 17.519 ;
     RECT  12.564 17.069 14.094 17.581 ;
     RECT  14.832 17.519 16.902 17.581 ;
     RECT  12.564 17.581 16.902 17.609 ;
     RECT  0.036 16.835 7.794 17.851 ;
     RECT  8.604 17.069 11.754 17.851 ;
     RECT  0.036 17.851 11.754 17.995 ;
     RECT  12.852 17.609 16.902 18.391 ;
     RECT  0.036 17.995 11.898 18.455 ;
     RECT  2.556 18.455 11.898 18.527 ;
     RECT  2.556 18.527 5.958 18.563 ;
     RECT  6.696 18.527 11.898 18.661 ;
     RECT  12.852 18.391 16.974 18.661 ;
     RECT  6.696 18.661 16.974 18.797 ;
     RECT  0.036 18.455 1.818 19.201 ;
     RECT  2.556 18.563 5.937 19.201 ;
     RECT  0.036 19.201 5.937 19.483 ;
     RECT  6.696 18.797 8.55 19.483 ;
     RECT  10.008 18.797 16.974 19.499 ;
     RECT  0.036 19.483 8.55 19.579 ;
     RECT  9.324 19.543 9.45 19.579 ;
     RECT  0.036 19.579 9.45 19.643 ;
     RECT  2.844 19.643 9.45 20.317 ;
     RECT  10.476 19.499 16.974 20.317 ;
     RECT  2.844 20.317 16.974 20.525 ;
     RECT  0.036 19.643 2.07 20.587 ;
     RECT  2.844 20.525 12.87 20.587 ;
     RECT  0.036 20.587 12.87 21.403 ;
     RECT  13.644 20.525 16.974 21.403 ;
     RECT  0.036 21.403 16.974 21.695 ;
     RECT  3.096 21.695 16.974 21.725 ;
     RECT  3.996 21.725 16.974 22.469 ;
     RECT  5.22 22.469 16.974 22.541 ;
     RECT  0.036 21.695 2.322 22.549 ;
     RECT  3.096 21.725 3.186 22.549 ;
     RECT  0.036 22.549 3.186 22.555 ;
     RECT  3.996 22.469 4.266 22.555 ;
     RECT  0.036 22.555 4.266 22.739 ;
     RECT  5.22 22.541 12.042 22.739 ;
     RECT  5.508 22.739 11.97 22.883 ;
     RECT  12.888 22.541 16.974 23.161 ;
     RECT  5.508 22.883 11.79 23.189 ;
     RECT  5.508 23.189 11.718 23.279 ;
     RECT  12.888 23.161 17.01 23.279 ;
     RECT  2.664 22.739 4.266 23.323 ;
     RECT  12.888 23.279 16.974 23.323 ;
     RECT  2.664 23.323 4.662 23.521 ;
     RECT  2.664 23.521 4.77 23.629 ;
     RECT  0.036 22.739 1.674 23.659 ;
     RECT  0.036 23.659 1.782 23.665 ;
     RECT  2.664 23.629 4.806 23.665 ;
     RECT  12.852 23.323 16.974 23.899 ;
     RECT  12.564 23.899 16.974 24.043 ;
     RECT  12.564 24.043 17.046 24.133 ;
     RECT  0.036 23.665 4.806 24.139 ;
     RECT  5.655 23.279 11.502 24.139 ;
     RECT  0.036 24.139 11.502 24.169 ;
     RECT  12.276 24.133 17.046 24.169 ;
     RECT  0.036 24.169 17.046 24.871 ;
     RECT  0.036 24.871 17.118 26.627 ;
     RECT  0.036 26.627 17.01 26.789 ;
     RECT  0.036 26.789 16.974 27.509 ;
     RECT  0.036 27.509 14.382 27.599 ;
     RECT  15.192 27.509 16.974 27.599 ;
     RECT  0.036 27.599 8.226 27.629 ;
     RECT  0.144 27.629 8.226 27.635 ;
     RECT  9.18 27.599 12.006 27.677 ;
     RECT  9.18 27.677 11.934 27.707 ;
     RECT  0.144 27.635 3.798 27.869 ;
     RECT  4.752 27.635 8.226 27.869 ;
     RECT  9.18 27.707 11.538 27.869 ;
     RECT  12.852 27.599 14.382 27.869 ;
     RECT  15.192 27.599 16.902 27.869 ;
     RECT  4.752 27.869 7.11 27.905 ;
     RECT  10.368 27.869 11.43 27.917 ;
     RECT  4.752 27.905 4.77 27.941 ;
     RECT  5.655 27.905 7.11 27.941 ;
     RECT  13.32 27.869 14.382 27.941 ;
     RECT  15.192 27.869 15.21 27.941 ;
     RECT  5.655 27.941 7.002 27.965 ;
     RECT  9.18 27.869 9.198 27.965 ;
     RECT  10.512 27.917 11.43 28.013 ;
     RECT  7.956 27.869 7.974 28.049 ;
     RECT  0.144 27.869 3.294 28.139 ;
     RECT  5.655 27.965 6.894 28.139 ;
     RECT  11.055 28.013 11.43 28.139 ;
     RECT  16.455 27.869 16.794 28.139 ;
     RECT  0.144 28.139 2.07 28.175 ;
     RECT  13.68 27.941 14.382 28.175 ;
     RECT  13.68 28.175 13.698 28.349 ;
     RECT  0.144 28.175 1.278 28.409 ;
     RECT  2.052 28.175 2.07 28.409 ;
     RECT  0.144 28.409 1.134 28.553 ;
     RECT  0.144 28.553 0.594 28.679 ;
     RECT  0.255 28.679 0.537 29.177 ;
     RECT  5.655 28.139 5.937 29.177 ;
     RECT  11.055 28.139 11.337 29.177 ;
     RECT  16.455 28.139 16.737 29.177 ;
     RECT  0.447 29.177 0.537 29.447 ;
     RECT  5.847 29.177 5.937 29.447 ;
     RECT  11.247 29.177 11.337 29.447 ;
     RECT  16.647 29.177 16.737 29.447 ;
    LAYER M4 ;
     RECT  0.025 2.688 0.037 9.72 ;
     RECT  0.025 10.8 0.037 19.992 ;
     RECT  0.025 21.072 0.037 27.624 ;
     RECT  0.037 2.688 0.097 27.624 ;
     RECT  0.097 2.592 0.248 27.624 ;
     RECT  0.248 0.528 0.352 29.172 ;
     RECT  0.352 0.798 0.44 29.172 ;
     RECT  0.44 0.798 0.544 29.442 ;
     RECT  0.544 2.352 2.041 27.624 ;
     RECT  2.041 2.352 2.437 27.72 ;
     RECT  2.437 2.304 3.661 27.72 ;
     RECT  3.661 2.208 5.648 27.72 ;
     RECT  5.648 0.528 5.752 29.172 ;
     RECT  5.752 0.798 5.84 29.172 ;
     RECT  5.84 0.798 5.944 29.442 ;
     RECT  5.944 1.968 6.659 3.96 ;
     RECT  6.659 1.968 6.851 2.28 ;
     RECT  5.944 4.944 6.973 27.912 ;
     RECT  6.659 3.312 7.333 3.96 ;
     RECT  6.973 4.944 7.333 27.96 ;
     RECT  6.851 2.256 7.957 2.28 ;
     RECT  7.333 3.312 7.957 27.96 ;
     RECT  7.957 2.256 8.533 27.96 ;
     RECT  8.533 2.208 9.029 27.96 ;
     RECT  9.029 2.448 9.209 27.96 ;
     RECT  9.209 2.448 9.389 27.768 ;
     RECT  9.389 2.496 10.357 27.768 ;
     RECT  10.357 2.496 11.048 27.912 ;
     RECT  11.048 0.528 11.152 29.172 ;
     RECT  11.152 0.798 11.24 29.172 ;
     RECT  11.24 0.798 11.344 29.442 ;
     RECT  11.344 2.784 13.093 27.768 ;
     RECT  13.093 2.304 13.601 27.768 ;
     RECT  13.601 2.784 13.628 27.768 ;
     RECT  13.628 2.784 13.715 28.344 ;
     RECT  13.715 2.784 15.293 27.768 ;
     RECT  15.293 2.784 16.448 27.72 ;
     RECT  16.448 0.528 16.552 29.172 ;
     RECT  16.552 0.798 16.64 29.172 ;
     RECT  16.64 0.798 16.744 29.442 ;
     RECT  16.744 2.688 17.1 27.528 ;
    LAYER M5 ;
     RECT  0.24 0.517 0.36 0.787 ;
     RECT  5.64 0.517 5.76 0.787 ;
     RECT  11.04 0.517 11.16 0.787 ;
     RECT  16.44 0.517 16.56 0.787 ;
     RECT  5.64 0.787 5.952 1.957 ;
     RECT  5.64 1.957 6.84 2.245 ;
     RECT  13.104 1.973 13.128 2.339 ;
     RECT  1.632 2.293 1.656 2.387 ;
     RECT  5.64 2.245 7.464 2.475 ;
     RECT  5.64 2.475 6.648 2.509 ;
     RECT  8.544 2.159 8.568 2.533 ;
     RECT  0.24 0.787 0.552 2.549 ;
     RECT  7.968 2.533 8.568 2.617 ;
     RECT  0.24 2.549 0.744 2.677 ;
     RECT  0.048 2.677 0.744 2.819 ;
     RECT  16.44 0.787 16.752 2.965 ;
     RECT  13.776 2.869 13.8 3.059 ;
     RECT  8.544 2.617 8.568 3.253 ;
     RECT  11.04 0.787 11.352 3.311 ;
     RECT  0.144 2.819 0.744 3.445 ;
     RECT  5.64 2.509 5.952 3.551 ;
     RECT  8.544 3.253 8.664 3.563 ;
     RECT  14.88 2.965 14.904 3.627 ;
     RECT  11.04 3.311 11.448 3.685 ;
     RECT  13.008 3.541 13.704 3.685 ;
     RECT  16.44 2.965 16.872 3.685 ;
     RECT  10.944 3.685 13.704 3.701 ;
     RECT  16.44 3.685 16.968 3.701 ;
     RECT  16.32 3.701 16.968 3.769 ;
     RECT  16.32 3.769 16.752 3.789 ;
     RECT  10.272 3.701 13.704 3.819 ;
     RECT  13.008 3.819 13.704 4.011 ;
     RECT  14.832 4.021 14.856 4.115 ;
     RECT  10.272 3.819 12.024 4.211 ;
     RECT  7.968 3.893 7.992 4.259 ;
     RECT  5.088 3.551 5.952 4.297 ;
     RECT  0.144 3.445 0.792 4.307 ;
     RECT  13.008 4.011 13.56 4.331 ;
     RECT  7.344 4.511 7.368 4.595 ;
     RECT  10.272 4.211 11.736 4.895 ;
     RECT  2.256 3.493 2.28 4.917 ;
     RECT  3.936 4.243 3.96 5.077 ;
     RECT  16.44 3.789 16.752 5.125 ;
     RECT  8.544 4.981 8.568 5.139 ;
     RECT  9.696 4.895 11.736 5.139 ;
     RECT  16.44 5.125 16.872 5.139 ;
     RECT  8.544 5.139 11.736 5.173 ;
     RECT  16.32 5.139 16.872 5.173 ;
     RECT  8.544 5.173 12.552 5.227 ;
     RECT  16.32 5.173 16.968 5.227 ;
     RECT  0.24 4.307 0.792 5.301 ;
     RECT  2.16 4.917 2.28 5.301 ;
     RECT  10.272 5.227 12.552 5.315 ;
     RECT  16.44 5.227 16.968 5.315 ;
     RECT  5.376 4.297 5.952 5.317 ;
     RECT  3.936 5.077 4.392 5.429 ;
     RECT  5.376 5.317 6.648 5.429 ;
     RECT  13.536 4.331 13.56 5.483 ;
     RECT  3.936 5.429 6.648 5.603 ;
     RECT  8.544 5.227 8.568 5.605 ;
     RECT  5.088 5.603 6.648 5.739 ;
     RECT  0.144 5.301 0.792 5.813 ;
     RECT  2.16 5.301 2.472 5.813 ;
     RECT  0.144 5.813 2.472 5.845 ;
     RECT  3.936 5.603 3.96 5.845 ;
     RECT  8.4 5.605 8.568 5.867 ;
     RECT  8.544 5.867 8.568 6.025 ;
     RECT  14.928 5.845 14.952 6.187 ;
     RECT  5.088 5.739 5.952 6.227 ;
     RECT  11.04 5.315 12.552 6.227 ;
     RECT  9.696 6.191 9.816 6.239 ;
     RECT  0.144 5.845 3.96 6.323 ;
     RECT  9.12 6.239 9.816 6.323 ;
     RECT  9.792 6.323 9.816 6.371 ;
     RECT  0.144 6.323 0.744 6.419 ;
     RECT  0.144 6.419 0.696 6.467 ;
     RECT  14.256 6.261 14.28 6.563 ;
     RECT  1.872 6.323 3.96 6.661 ;
     RECT  13.68 6.773 14.088 6.899 ;
     RECT  12.528 6.227 12.552 6.925 ;
     RECT  1.872 6.661 4.008 6.947 ;
     RECT  1.872 6.947 2.472 6.995 ;
     RECT  3.744 6.947 4.008 7.139 ;
     RECT  11.04 6.227 11.544 7.343 ;
     RECT  7.44 7.237 7.464 7.381 ;
     RECT  11.04 7.343 12.024 7.427 ;
     RECT  0.24 6.467 0.696 7.477 ;
     RECT  0.24 7.477 0.744 7.573 ;
     RECT  3.936 7.139 4.008 7.621 ;
     RECT  16.44 5.315 16.752 7.621 ;
     RECT  2.304 6.995 2.472 7.715 ;
     RECT  0.144 7.573 0.744 7.861 ;
     RECT  5.64 6.227 5.952 7.861 ;
     RECT  14.064 6.899 14.088 7.861 ;
     RECT  0.144 7.861 0.888 7.891 ;
     RECT  11.04 7.427 11.352 7.909 ;
     RECT  7.44 7.381 8.328 7.957 ;
     RECT  10.8 7.909 11.352 8.111 ;
     RECT  13.968 7.861 14.088 8.111 ;
     RECT  15.072 7.861 15.096 8.111 ;
     RECT  3.936 7.621 4.392 8.181 ;
     RECT  5.64 7.861 6.312 8.181 ;
     RECT  7.44 7.957 8.856 8.181 ;
     RECT  10.752 8.111 11.352 8.197 ;
     RECT  3.936 8.181 6.312 8.245 ;
     RECT  7.44 8.181 9.096 8.245 ;
     RECT  2.928 8.245 6.312 8.293 ;
     RECT  7.44 8.245 9.144 8.293 ;
     RECT  0.144 7.891 0.936 8.373 ;
     RECT  2.928 8.293 9.144 8.377 ;
     RECT  13.968 8.111 15.096 8.427 ;
     RECT  16.44 7.621 16.872 8.483 ;
     RECT  0.144 8.373 1.032 8.501 ;
     RECT  10.272 8.197 11.352 8.543 ;
     RECT  0.144 8.501 1.176 8.581 ;
     RECT  0.144 8.581 1.656 8.653 ;
     RECT  0.24 8.653 1.656 8.747 ;
     RECT  2.928 8.377 7.752 8.747 ;
     RECT  13.968 8.427 14.28 8.773 ;
     RECT  2.928 8.747 7.416 8.819 ;
     RECT  8.736 8.377 9.144 8.869 ;
     RECT  10.272 8.543 11.448 8.869 ;
     RECT  13.68 8.773 14.28 8.875 ;
     RECT  5.136 8.819 7.416 9.097 ;
     RECT  14.256 8.875 14.28 9.155 ;
     RECT  8.736 8.869 11.448 9.195 ;
     RECT  2.928 8.819 3.576 9.205 ;
     RECT  2.256 9.205 3.576 9.323 ;
     RECT  10.272 9.195 11.448 9.337 ;
     RECT  2.256 9.323 2.28 9.395 ;
     RECT  5.328 9.097 7.416 9.395 ;
     RECT  16.44 8.483 16.752 9.445 ;
     RECT  10.848 9.337 11.448 9.493 ;
     RECT  16.44 9.445 16.872 9.635 ;
     RECT  3.408 9.323 3.576 9.707 ;
     RECT  0.24 8.747 1.176 9.733 ;
     RECT  5.328 9.395 6.312 9.771 ;
     RECT  5.52 9.771 6.312 9.779 ;
     RECT  3.936 9.781 3.96 9.865 ;
     RECT  0.144 9.733 1.176 9.925 ;
     RECT  10.848 9.493 12.024 9.971 ;
     RECT  7.392 9.395 7.416 9.973 ;
     RECT  0.144 9.925 1.224 10.09 ;
     RECT  8.736 9.195 9.144 10.155 ;
     RECT  0.144 10.09 1.272 10.261 ;
     RECT  13.104 8.949 13.128 10.355 ;
     RECT  0.048 10.261 1.272 10.421 ;
     RECT  7.392 9.973 7.464 10.453 ;
     RECT  0.048 10.421 1.512 10.539 ;
     RECT  4.512 10.597 4.536 10.681 ;
     RECT  5.64 9.779 6.312 10.741 ;
     RECT  7.392 10.453 8.664 10.741 ;
     RECT  0.144 10.539 1.512 10.787 ;
     RECT  9.696 10.549 9.72 10.883 ;
     RECT  10.848 9.971 11.448 10.893 ;
     RECT  5.64 10.741 8.664 10.957 ;
     RECT  16.44 9.635 16.752 11.029 ;
     RECT  16.44 11.029 16.872 11.125 ;
     RECT  13.68 10.613 13.704 11.171 ;
     RECT  16.32 11.125 16.968 11.209 ;
     RECT  16.32 11.209 16.872 11.219 ;
     RECT  10.848 10.893 11.352 11.253 ;
     RECT  2.928 11.221 2.952 11.413 ;
     RECT  3.936 11.039 4.248 11.413 ;
     RECT  2.928 11.413 4.248 11.499 ;
     RECT  5.64 10.957 8.184 11.603 ;
     RECT  12.528 11.509 12.552 11.603 ;
     RECT  7.92 11.603 8.184 11.795 ;
     RECT  5.64 11.603 6.888 11.843 ;
     RECT  0.24 10.787 0.984 11.845 ;
     RECT  3.696 11.499 4.248 12.035 ;
     RECT  10.272 11.253 11.352 12.035 ;
     RECT  16.44 11.219 16.872 12.181 ;
     RECT  2.208 12.115 2.232 12.191 ;
     RECT  2.16 12.191 2.232 12.203 ;
     RECT  16.32 12.181 16.872 12.213 ;
     RECT  9.696 12.143 9.72 12.227 ;
     RECT  8.688 11.941 8.712 12.267 ;
     RECT  16.32 12.213 16.968 12.267 ;
     RECT  2.16 12.203 2.184 12.275 ;
     RECT  0.144 11.845 0.984 12.277 ;
     RECT  4.272 12.213 4.296 12.301 ;
     RECT  16.44 12.267 16.968 12.323 ;
     RECT  11.04 12.035 11.352 12.709 ;
     RECT  12.768 11.797 12.792 12.709 ;
     RECT  5.64 11.843 6.264 12.757 ;
     RECT  0.144 12.277 1.56 12.779 ;
     RECT  11.04 12.709 12.792 12.853 ;
     RECT  11.04 12.853 13.704 13.043 ;
     RECT  4.56 12.757 6.264 13.045 ;
     RECT  4.56 13.045 6.744 13.163 ;
     RECT  16.44 12.323 16.872 13.267 ;
     RECT  15.888 13.267 16.872 13.285 ;
     RECT  0.144 12.779 0.936 13.355 ;
     RECT  15.888 13.285 16.968 13.355 ;
     RECT  16.44 13.355 16.968 13.369 ;
     RECT  5.136 13.163 6.744 13.419 ;
     RECT  5.136 13.419 6.264 13.427 ;
     RECT  14.064 13.381 14.088 13.547 ;
     RECT  7.968 13.237 7.992 13.763 ;
     RECT  11.04 13.043 12.936 13.811 ;
     RECT  9.696 13.295 9.72 13.813 ;
     RECT  11.04 13.811 11.352 13.813 ;
     RECT  9.696 13.813 11.352 13.907 ;
     RECT  8.544 13.919 8.568 14.005 ;
     RECT  12.528 13.811 12.936 14.005 ;
     RECT  8.544 14.005 8.664 14.089 ;
     RECT  12.528 14.005 13.704 14.123 ;
     RECT  9.696 13.907 10.008 14.197 ;
     RECT  9.12 14.197 10.008 14.281 ;
     RECT  0.144 13.355 0.888 14.325 ;
     RECT  16.44 13.369 16.752 14.341 ;
     RECT  12.528 14.123 12.552 14.387 ;
     RECT  5.64 13.427 6.264 14.437 ;
     RECT  7.392 14.005 7.464 14.437 ;
     RECT  9.936 14.281 10.008 14.713 ;
     RECT  5.64 14.437 7.464 14.76 ;
     RECT  0.144 14.325 1.08 14.837 ;
     RECT  13.824 14.709 14.28 14.867 ;
     RECT  9.984 14.713 10.008 14.869 ;
     RECT  11.04 13.907 11.352 14.869 ;
     RECT  0.144 14.837 1.272 14.901 ;
     RECT  13.824 14.867 14.088 14.955 ;
     RECT  9.984 14.869 11.352 15.147 ;
     RECT  5.64 14.76 8.04 15.157 ;
     RECT  5.088 15.157 8.04 15.301 ;
     RECT  5.088 15.301 8.328 15.625 ;
     RECT  5.088 15.625 6.888 15.659 ;
     RECT  14.064 14.955 14.088 15.779 ;
     RECT  10.08 15.147 11.352 15.979 ;
     RECT  7.968 15.625 8.328 15.983 ;
     RECT  7.968 15.983 8.568 16.067 ;
     RECT  0.144 14.901 1.32 16.115 ;
     RECT  0.144 16.115 0.696 16.163 ;
     RECT  5.088 15.659 6.84 16.163 ;
     RECT  5.088 16.163 5.952 16.165 ;
     RECT  10.128 15.979 11.352 16.235 ;
     RECT  4.992 16.165 5.952 16.261 ;
     RECT  4.848 16.261 5.952 16.739 ;
     RECT  10.176 16.235 11.352 16.799 ;
     RECT  10.176 16.799 11.448 16.883 ;
     RECT  13.68 16.943 13.704 17.027 ;
     RECT  2.16 16.991 2.184 17.075 ;
     RECT  9.12 17.077 9.144 17.161 ;
     RECT  13.104 17.077 13.128 17.171 ;
     RECT  0.144 16.163 0.552 17.267 ;
     RECT  10.176 16.883 11.352 17.267 ;
     RECT  7.968 16.067 7.992 17.317 ;
     RECT  0.24 17.267 0.552 17.589 ;
     RECT  7.968 17.317 8.376 17.589 ;
     RECT  16.44 14.341 16.872 17.603 ;
     RECT  0.24 17.589 0.648 17.653 ;
     RECT  2.256 17.509 2.28 17.699 ;
     RECT  4.944 16.739 5.952 17.699 ;
     RECT  7.44 17.589 8.376 17.699 ;
     RECT  0.24 17.653 0.696 17.701 ;
     RECT  10.272 17.267 11.352 17.707 ;
     RECT  7.968 17.699 8.376 17.891 ;
     RECT  7.968 17.891 7.992 18.227 ;
     RECT  0.24 17.701 0.792 18.373 ;
     RECT  10.848 17.707 11.352 18.419 ;
     RECT  11.04 18.419 11.352 18.805 ;
     RECT  5.64 17.699 5.952 18.911 ;
     RECT  7.44 18.863 7.464 18.947 ;
     RECT  5.088 18.911 5.952 18.995 ;
     RECT  13.68 18.911 13.704 18.995 ;
     RECT  0.144 18.373 0.792 19.081 ;
     RECT  16.44 17.603 16.752 19.141 ;
     RECT  16.44 19.141 16.872 19.283 ;
     RECT  9.696 19.253 9.72 19.427 ;
     RECT  11.04 18.805 11.88 20.021 ;
     RECT  10.944 20.021 11.88 20.149 ;
     RECT  16.44 19.283 16.752 20.255 ;
     RECT  10.944 20.149 12.552 20.277 ;
     RECT  16.44 20.255 16.968 20.277 ;
     RECT  10.752 20.277 12.552 20.339 ;
     RECT  15.888 20.277 16.968 20.365 ;
     RECT  12.528 20.339 12.552 20.395 ;
     RECT  0.144 19.081 0.744 20.533 ;
     RECT  7.968 19.333 7.992 20.533 ;
     RECT  5.64 18.995 5.952 20.581 ;
     RECT  7.296 20.533 7.992 20.617 ;
     RECT  0.048 20.533 0.744 20.677 ;
     RECT  0.048 20.677 0.792 20.691 ;
     RECT  0.048 20.691 1.08 20.779 ;
     RECT  9.552 20.485 9.576 20.965 ;
     RECT  10.752 20.339 11.448 20.965 ;
     RECT  16.32 20.365 16.968 20.965 ;
     RECT  16.32 20.965 17.064 21.049 ;
     RECT  9.552 20.965 11.448 21.075 ;
     RECT  2.256 20.917 2.28 21.107 ;
     RECT  5.136 20.581 5.952 21.109 ;
     RECT  9.072 21.075 11.448 21.155 ;
     RECT  7.872 20.617 7.992 21.215 ;
     RECT  9.072 21.155 9.72 21.215 ;
     RECT  2.208 21.237 2.232 21.267 ;
     RECT  7.872 21.215 9.72 21.299 ;
     RECT  16.32 21.049 16.968 21.365 ;
     RECT  2.112 21.267 2.232 21.395 ;
     RECT  3.936 21.109 3.96 21.397 ;
     RECT  5.136 21.109 6.36 21.397 ;
     RECT  16.272 21.365 16.968 21.453 ;
     RECT  3.936 21.397 6.36 21.483 ;
     RECT  12.528 21.407 12.552 21.491 ;
     RECT  4.56 21.483 6.36 21.547 ;
     RECT  4.56 21.547 4.584 21.675 ;
     RECT  5.64 21.547 6.36 21.675 ;
     RECT  7.872 21.299 7.992 21.683 ;
     RECT  0.144 20.779 1.08 21.877 ;
     RECT  14.832 21.829 14.856 21.931 ;
     RECT  0.144 21.877 1.848 21.971 ;
     RECT  16.44 21.453 16.968 21.971 ;
     RECT  7.008 21.935 7.032 22.019 ;
     RECT  9.12 21.299 9.72 22.367 ;
     RECT  10.848 21.155 11.448 22.367 ;
     RECT  9.12 22.367 11.448 22.403 ;
     RECT  9.6 22.403 11.448 22.451 ;
     RECT  10.944 22.451 11.448 22.453 ;
     RECT  0.144 21.971 1.224 22.547 ;
     RECT  10.944 22.453 12.024 22.547 ;
     RECT  16.44 21.971 16.872 22.547 ;
     RECT  14.64 22.117 14.664 22.965 ;
     RECT  5.64 21.675 5.952 22.981 ;
     RECT  8.016 22.741 8.04 22.981 ;
     RECT  5.64 22.981 6.888 22.995 ;
     RECT  9.6 22.451 9.816 23.019 ;
     RECT  14.256 22.965 14.664 23.123 ;
     RECT  5.64 22.995 6.984 23.267 ;
     RECT  16.44 22.547 16.752 23.365 ;
     RECT  10.944 22.547 11.352 23.411 ;
     RECT  16.032 23.365 16.752 23.509 ;
     RECT  0.144 22.547 1.032 23.541 ;
     RECT  9.6 23.019 9.624 23.541 ;
     RECT  8.016 22.981 8.136 23.605 ;
     RECT  16.032 23.509 16.872 23.605 ;
     RECT  2.304 22.837 2.328 23.669 ;
     RECT  7.968 23.605 8.136 23.669 ;
     RECT  9.12 23.541 9.624 23.669 ;
     RECT  7.968 23.669 9.624 23.689 ;
     RECT  2.304 23.669 2.376 23.757 ;
     RECT  2.304 23.757 2.328 23.787 ;
     RECT  8.496 23.689 9.624 23.787 ;
     RECT  0.144 23.541 1.128 23.795 ;
     RECT  16.032 23.605 16.968 23.915 ;
     RECT  8.496 23.787 9.144 23.987 ;
     RECT  7.44 23.989 7.464 24.083 ;
     RECT  8.496 23.987 8.52 24.083 ;
     RECT  3.936 24.373 3.96 24.457 ;
     RECT  0.24 23.795 1.128 24.469 ;
     RECT  0.24 24.469 1.224 24.517 ;
     RECT  5.64 23.267 5.952 24.613 ;
     RECT  16.32 23.915 16.968 24.623 ;
     RECT  16.32 24.623 17.064 24.683 ;
     RECT  5.136 24.613 6.264 24.697 ;
     RECT  16.44 24.683 17.064 24.707 ;
     RECT  11.04 23.411 11.352 24.757 ;
     RECT  14.256 23.123 14.28 24.805 ;
     RECT  5.52 24.697 6.264 24.821 ;
     RECT  0.24 24.517 2.28 24.851 ;
     RECT  0.24 24.851 2.088 24.853 ;
     RECT  5.52 24.821 6.888 24.899 ;
     RECT  10.272 24.757 11.352 24.939 ;
     RECT  13.632 24.805 14.28 24.939 ;
     RECT  12.528 24.037 12.552 24.949 ;
     RECT  12.528 24.949 12.6 25.067 ;
     RECT  5.64 24.899 6.888 25.199 ;
     RECT  9.696 25.141 9.72 25.235 ;
     RECT  5.64 25.199 6.984 25.283 ;
     RECT  8.544 25.269 8.568 25.299 ;
     RECT  8.544 25.299 8.616 25.381 ;
     RECT  8.544 25.381 8.712 25.465 ;
     RECT  14.256 24.939 14.28 25.475 ;
     RECT  11.04 24.939 11.352 25.589 ;
     RECT  12.528 25.067 12.552 25.589 ;
     RECT  0.144 24.853 2.088 25.619 ;
     RECT  11.04 25.589 12.552 25.643 ;
     RECT  11.04 25.643 11.976 25.715 ;
     RECT  0.144 25.619 1.08 25.963 ;
     RECT  2.064 25.619 2.088 26.291 ;
     RECT  8.544 25.465 8.568 26.387 ;
     RECT  11.04 25.715 11.352 26.389 ;
     RECT  16.44 24.707 16.872 26.451 ;
     RECT  7.44 25.429 7.464 26.483 ;
     RECT  5.64 25.283 6.072 26.485 ;
     RECT  9.696 26.421 9.72 26.485 ;
     RECT  10.944 26.389 11.352 26.485 ;
     RECT  16.32 26.451 16.872 26.485 ;
     RECT  9.696 26.485 11.352 26.531 ;
     RECT  16.32 26.485 17.064 26.579 ;
     RECT  10.272 26.531 11.352 26.603 ;
     RECT  5.52 26.485 6.072 26.613 ;
     RECT  14.256 26.613 14.28 26.677 ;
     RECT  5.472 26.613 6.072 26.707 ;
     RECT  5.472 26.707 6.168 26.771 ;
     RECT  7.968 26.677 7.992 26.771 ;
     RECT  5.64 26.771 6.168 26.795 ;
     RECT  13.104 26.229 13.128 26.819 ;
     RECT  14.16 26.677 14.28 26.819 ;
     RECT  0.24 25.963 1.08 26.867 ;
     RECT  16.32 26.579 16.872 26.923 ;
     RECT  0.24 26.867 0.696 26.997 ;
     RECT  0.144 26.997 0.696 27.085 ;
     RECT  0.24 27.085 0.696 27.092 ;
     RECT  11.04 26.603 11.352 27.119 ;
     RECT  0.24 27.092 0.648 27.179 ;
     RECT  11.04 27.119 11.448 27.203 ;
     RECT  16.44 26.923 16.872 27.299 ;
     RECT  13.68 27.551 13.704 28.459 ;
     RECT  0.24 27.179 0.552 29.183 ;
     RECT  5.64 26.795 5.952 29.183 ;
     RECT  11.04 27.203 11.352 29.183 ;
     RECT  16.44 27.299 16.752 29.183 ;
     RECT  0.432 29.183 0.552 29.453 ;
     RECT  5.832 29.183 5.952 29.453 ;
     RECT  11.232 29.183 11.352 29.453 ;
     RECT  16.632 29.183 16.752 29.453 ;
    LAYER M6 ;
     RECT  0 0.996 0.037 1.86 ;
     RECT  0 11.796 0.037 12.66 ;
     RECT  0 22.596 0.053 23.46 ;
     RECT  0.037 0.996 0.133 2.72 ;
     RECT  0 6.396 0.133 7.26 ;
     RECT  0.037 10.496 0.133 12.66 ;
     RECT  0 17.196 0.133 18.06 ;
     RECT  0.037 20.736 0.133 20.768 ;
     RECT  0.053 22.596 0.133 24.544 ;
     RECT  0 27.996 0.133 28.86 ;
     RECT  0.133 0.996 8.579 28.86 ;
     RECT  8.579 3.328 10.883 28.86 ;
     RECT  10.883 3.328 11.459 14.944 ;
     RECT  10.883 16.832 11.459 28.86 ;
     RECT  11.459 16.96 11.891 28.86 ;
     RECT  11.891 20.352 12.563 28.86 ;
     RECT  11.459 3.584 13.043 14.944 ;
     RECT  8.579 0.996 13.139 2.016 ;
     RECT  13.043 5.44 13.139 14.944 ;
     RECT  13.139 5.44 13.571 9.12 ;
     RECT  13.139 10.624 13.715 14.944 ;
     RECT  11.891 16.96 13.715 18.976 ;
     RECT  13.715 11.796 13.859 14.944 ;
     RECT  13.859 11.796 14.099 14.752 ;
     RECT  12.563 22.596 14.195 28.86 ;
     RECT  13.571 6.144 14.291 9.12 ;
     RECT  14.099 14.72 14.291 14.752 ;
     RECT  14.195 22.596 14.291 26.656 ;
     RECT  14.291 22.596 14.821 23.46 ;
     RECT  13.043 3.584 14.867 4.064 ;
     RECT  14.867 3.584 14.915 3.616 ;
     RECT  14.291 6.144 14.963 8.416 ;
     RECT  14.963 6.396 15.107 8.416 ;
     RECT  14.099 11.796 15.877 12.66 ;
     RECT  14.821 21.888 16.021 23.46 ;
     RECT  15.877 20.288 16.261 20.32 ;
     RECT  16.021 21.888 16.261 23.904 ;
     RECT  15.107 6.396 16.309 7.26 ;
     RECT  15.877 11.796 16.309 13.344 ;
     RECT  16.261 20.288 16.309 23.904 ;
     RECT  14.195 27.996 16.309 28.86 ;
     RECT  13.139 0.996 16.56 1.86 ;
     RECT  16.309 5.184 16.56 7.26 ;
     RECT  13.715 17.196 16.56 18.06 ;
     RECT  16.309 26.496 16.56 28.86 ;
     RECT  16.56 1.572 16.752 1.86 ;
     RECT  16.56 6.972 16.752 7.26 ;
     RECT  16.56 17.772 16.752 18.06 ;
     RECT  16.309 20.288 16.752 24.672 ;
     RECT  16.56 28.572 16.752 28.86 ;
     RECT  16.56 26.496 16.883 26.912 ;
     RECT  16.309 3.712 16.979 3.744 ;
     RECT  16.56 5.184 16.979 5.216 ;
     RECT  16.309 11.136 16.979 13.344 ;
     RECT  16.752 20.288 16.979 21.92 ;
     RECT  16.752 23.744 16.979 24.672 ;
     RECT  16.979 20.992 17.075 21.024 ;
     RECT  16.979 24.64 17.075 24.672 ;
     RECT  16.883 26.496 17.075 26.528 ;
    LAYER M7 ;
     RECT  0.856 0.531 1.144 1.973 ;
     RECT  0.512 1.973 1.144 2.165 ;
     RECT  0.512 2.165 1.696 2.347 ;
     RECT  6.256 0.531 6.544 2.677 ;
     RECT  0.512 2.347 1.144 3.627 ;
     RECT  6.256 2.677 7.648 5.173 ;
     RECT  6.016 5.173 7.648 8.053 ;
     RECT  5.888 8.053 7.648 8.235 ;
     RECT  11.656 0.531 11.944 8.821 ;
     RECT  2.88 8.949 2.912 9.131 ;
     RECT  2.944 9.269 2.976 9.451 ;
     RECT  5.952 8.235 7.648 11.253 ;
     RECT  5.696 11.253 7.648 11.509 ;
     RECT  3.712 9.717 4.256 11.563 ;
     RECT  5.696 11.509 7.968 11.563 ;
     RECT  5.952 11.563 7.968 12.267 ;
     RECT  11.656 8.821 12.512 13.163 ;
     RECT  6.256 12.267 7.968 13.803 ;
     RECT  0.856 3.627 1.144 13.941 ;
     RECT  0.512 13.941 1.144 14.763 ;
     RECT  6.256 13.803 7.648 15.595 ;
     RECT  0.856 14.763 1.144 16.885 ;
     RECT  0.856 16.885 2.208 17.131 ;
     RECT  4.8 16.309 4.832 20.085 ;
     RECT  6.256 15.595 7.328 20.587 ;
     RECT  3.968 20.085 4.832 21.109 ;
     RECT  6.256 20.587 6.544 21.109 ;
     RECT  3.968 21.109 6.544 21.163 ;
     RECT  0.856 17.131 1.144 21.301 ;
     RECT  0.856 21.301 1.888 21.995 ;
     RECT  9.984 15.733 10.016 22.965 ;
     RECT  9.792 22.965 10.272 23.851 ;
     RECT  9.984 23.851 10.272 23.979 ;
     RECT  0.856 21.995 1.144 24.501 ;
     RECT  9.984 23.979 10.016 24.939 ;
     RECT  5.056 21.163 6.544 25.963 ;
     RECT  6.144 25.963 6.544 27.627 ;
     RECT  0.064 24.501 1.144 28.459 ;
     RECT  0.856 28.459 1.144 29.439 ;
     RECT  6.256 27.627 6.544 29.439 ;
     RECT  11.656 13.163 11.944 29.439 ;
  END
END dsfd_stnh_514x1
END LIBRARY
